# OpenTallas memory compiler (tools/mem_compiler), ASAP7 abstract view
VERSION 5.7 ;
BUSBITCHARS "[]" ;
DIVIDERCHAR "/" ;
PROPERTYDEFINITIONS
  MACRO width INTEGER ;
  MACRO depth INTEGER ;
  MACRO banks INTEGER ;
END PROPERTYDEFINITIONS
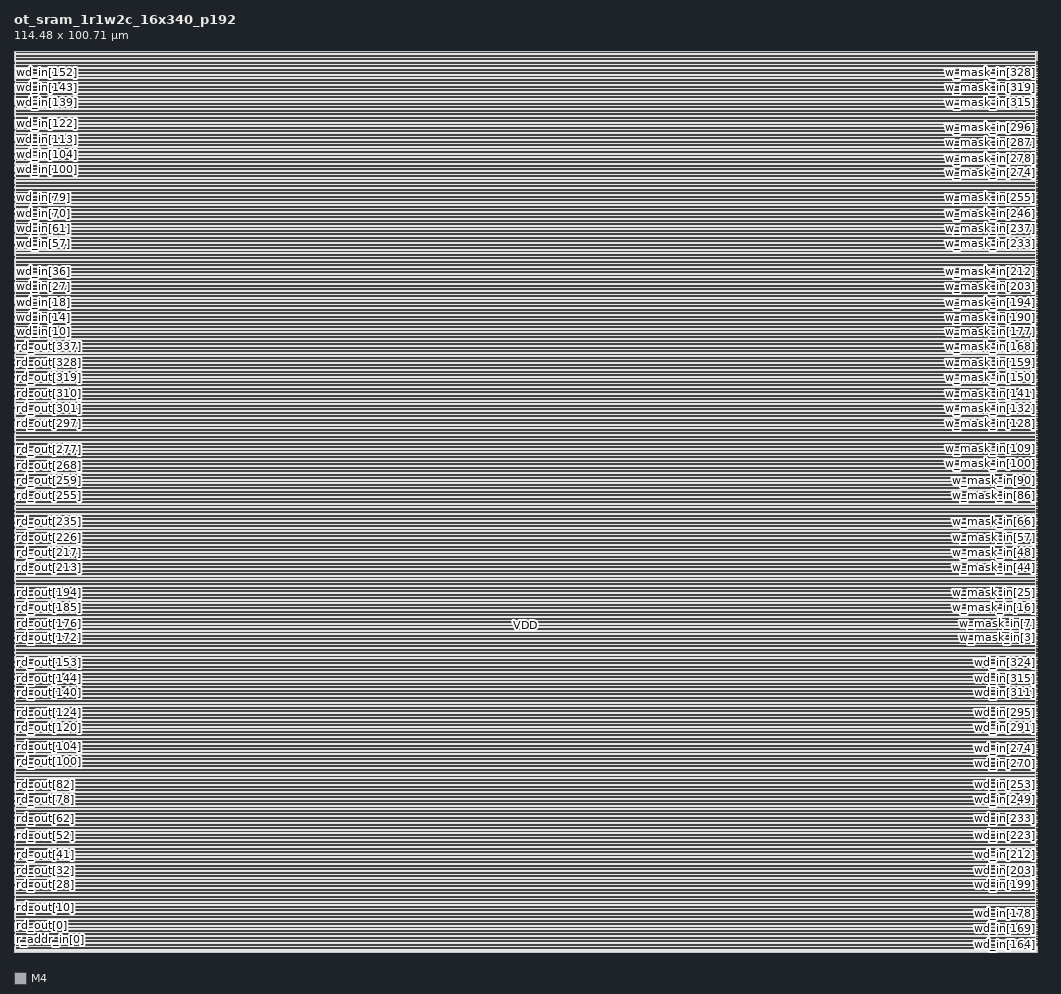
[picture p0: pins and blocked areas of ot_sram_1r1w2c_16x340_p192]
MACRO ot_sram_1r1w2c_16x340_p192
  PROPERTY width 340 ;
  PROPERTY depth 16 ;
  PROPERTY banks 1 ;
  FOREIGN ot_sram_1r1w2c_16x340_p192 0 0 ;
  SYMMETRY X Y R90 ;
  SIZE 114.480 BY 100.710 ;
  CLASS BLOCK ;
  PIN wclk
    DIRECTION INPUT ;
    USE CLOCK ;
    SHAPE ABUTMENT ;
    PORT
      LAYER M4 ;
      RECT 0.000 0.768 0.024 0.792 ;
    END
  END wclk
  PIN rclk
    DIRECTION INPUT ;
    USE CLOCK ;
    SHAPE ABUTMENT ;
    PORT
      LAYER M4 ;
      RECT 0.000 0.960 0.024 0.984 ;
    END
  END rclk
  PIN r_ce_in
    DIRECTION INPUT ;
    USE SIGNAL ;
    SHAPE ABUTMENT ;
    PORT
      LAYER M4 ;
      RECT 0.000 1.152 0.024 1.176 ;
    END
  END r_ce_in
  PIN r_addr_in[0]
    DIRECTION INPUT ;
    USE SIGNAL ;
    SHAPE ABUTMENT ;
    PORT
      LAYER M4 ;
      RECT 0.000 1.344 0.024 1.368 ;
    END
  END r_addr_in[0]
  PIN r_addr_in[1]
    DIRECTION INPUT ;
    USE SIGNAL ;
    SHAPE ABUTMENT ;
    PORT
      LAYER M4 ;
      RECT 0.000 1.536 0.024 1.560 ;
    END
  END r_addr_in[1]
  PIN r_addr_in[2]
    DIRECTION INPUT ;
    USE SIGNAL ;
    SHAPE ABUTMENT ;
    PORT
      LAYER M4 ;
      RECT 0.000 1.728 0.024 1.752 ;
    END
  END r_addr_in[2]
  PIN r_addr_in[3]
    DIRECTION INPUT ;
    USE SIGNAL ;
    SHAPE ABUTMENT ;
    PORT
      LAYER M4 ;
      RECT 0.000 1.920 0.024 1.944 ;
    END
  END r_addr_in[3]
  PIN rd_out[0]
    DIRECTION OUTPUT ;
    USE SIGNAL ;
    SHAPE ABUTMENT ;
    PORT
      LAYER M4 ;
      RECT 0.000 2.112 0.024 2.136 ;
    END
  END rd_out[0]
  PIN rd_out[1]
    DIRECTION OUTPUT ;
    USE SIGNAL ;
    SHAPE ABUTMENT ;
    PORT
      LAYER M4 ;
      RECT 0.000 2.304 0.024 2.328 ;
    END
  END rd_out[1]
  PIN rd_out[2]
    DIRECTION OUTPUT ;
    USE SIGNAL ;
    SHAPE ABUTMENT ;
    PORT
      LAYER M4 ;
      RECT 0.000 2.496 0.024 2.520 ;
    END
  END rd_out[2]
  PIN rd_out[3]
    DIRECTION OUTPUT ;
    USE SIGNAL ;
    SHAPE ABUTMENT ;
    PORT
      LAYER M4 ;
      RECT 0.000 2.688 0.024 2.712 ;
    END
  END rd_out[3]
  PIN rd_out[4]
    DIRECTION OUTPUT ;
    USE SIGNAL ;
    SHAPE ABUTMENT ;
    PORT
      LAYER M4 ;
      RECT 0.000 2.880 0.024 2.904 ;
    END
  END rd_out[4]
  PIN rd_out[5]
    DIRECTION OUTPUT ;
    USE SIGNAL ;
    SHAPE ABUTMENT ;
    PORT
      LAYER M4 ;
      RECT 0.000 3.072 0.024 3.096 ;
    END
  END rd_out[5]
  PIN rd_out[6]
    DIRECTION OUTPUT ;
    USE SIGNAL ;
    SHAPE ABUTMENT ;
    PORT
      LAYER M4 ;
      RECT 0.000 3.264 0.024 3.288 ;
    END
  END rd_out[6]
  PIN rd_out[7]
    DIRECTION OUTPUT ;
    USE SIGNAL ;
    SHAPE ABUTMENT ;
    PORT
      LAYER M4 ;
      RECT 0.000 3.456 0.024 3.480 ;
    END
  END rd_out[7]
  PIN rd_out[8]
    DIRECTION OUTPUT ;
    USE SIGNAL ;
    SHAPE ABUTMENT ;
    PORT
      LAYER M4 ;
      RECT 0.000 3.648 0.024 3.672 ;
    END
  END rd_out[8]
  PIN rd_out[9]
    DIRECTION OUTPUT ;
    USE SIGNAL ;
    SHAPE ABUTMENT ;
    PORT
      LAYER M4 ;
      RECT 0.000 3.840 0.024 3.864 ;
    END
  END rd_out[9]
  PIN rd_out[10]
    DIRECTION OUTPUT ;
    USE SIGNAL ;
    SHAPE ABUTMENT ;
    PORT
      LAYER M4 ;
      RECT 0.000 4.032 0.024 4.056 ;
    END
  END rd_out[10]
  PIN rd_out[11]
    DIRECTION OUTPUT ;
    USE SIGNAL ;
    SHAPE ABUTMENT ;
    PORT
      LAYER M4 ;
      RECT 0.000 4.224 0.024 4.248 ;
    END
  END rd_out[11]
  PIN rd_out[12]
    DIRECTION OUTPUT ;
    USE SIGNAL ;
    SHAPE ABUTMENT ;
    PORT
      LAYER M4 ;
      RECT 0.000 4.416 0.024 4.440 ;
    END
  END rd_out[12]
  PIN rd_out[13]
    DIRECTION OUTPUT ;
    USE SIGNAL ;
    SHAPE ABUTMENT ;
    PORT
      LAYER M4 ;
      RECT 0.000 4.608 0.024 4.632 ;
    END
  END rd_out[13]
  PIN rd_out[14]
    DIRECTION OUTPUT ;
    USE SIGNAL ;
    SHAPE ABUTMENT ;
    PORT
      LAYER M4 ;
      RECT 0.000 4.800 0.024 4.824 ;
    END
  END rd_out[14]
  PIN rd_out[15]
    DIRECTION OUTPUT ;
    USE SIGNAL ;
    SHAPE ABUTMENT ;
    PORT
      LAYER M4 ;
      RECT 0.000 4.992 0.024 5.016 ;
    END
  END rd_out[15]
  PIN rd_out[16]
    DIRECTION OUTPUT ;
    USE SIGNAL ;
    SHAPE ABUTMENT ;
    PORT
      LAYER M4 ;
      RECT 0.000 5.184 0.024 5.208 ;
    END
  END rd_out[16]
  PIN rd_out[17]
    DIRECTION OUTPUT ;
    USE SIGNAL ;
    SHAPE ABUTMENT ;
    PORT
      LAYER M4 ;
      RECT 0.000 5.376 0.024 5.400 ;
    END
  END rd_out[17]
  PIN rd_out[18]
    DIRECTION OUTPUT ;
    USE SIGNAL ;
    SHAPE ABUTMENT ;
    PORT
      LAYER M4 ;
      RECT 0.000 5.568 0.024 5.592 ;
    END
  END rd_out[18]
  PIN rd_out[19]
    DIRECTION OUTPUT ;
    USE SIGNAL ;
    SHAPE ABUTMENT ;
    PORT
      LAYER M4 ;
      RECT 0.000 5.760 0.024 5.784 ;
    END
  END rd_out[19]
  PIN rd_out[20]
    DIRECTION OUTPUT ;
    USE SIGNAL ;
    SHAPE ABUTMENT ;
    PORT
      LAYER M4 ;
      RECT 0.000 5.952 0.024 5.976 ;
    END
  END rd_out[20]
  PIN rd_out[21]
    DIRECTION OUTPUT ;
    USE SIGNAL ;
    SHAPE ABUTMENT ;
    PORT
      LAYER M4 ;
      RECT 0.000 6.144 0.024 6.168 ;
    END
  END rd_out[21]
  PIN rd_out[22]
    DIRECTION OUTPUT ;
    USE SIGNAL ;
    SHAPE ABUTMENT ;
    PORT
      LAYER M4 ;
      RECT 0.000 6.336 0.024 6.360 ;
    END
  END rd_out[22]
  PIN rd_out[23]
    DIRECTION OUTPUT ;
    USE SIGNAL ;
    SHAPE ABUTMENT ;
    PORT
      LAYER M4 ;
      RECT 0.000 6.528 0.024 6.552 ;
    END
  END rd_out[23]
  PIN rd_out[24]
    DIRECTION OUTPUT ;
    USE SIGNAL ;
    SHAPE ABUTMENT ;
    PORT
      LAYER M4 ;
      RECT 0.000 6.720 0.024 6.744 ;
    END
  END rd_out[24]
  PIN rd_out[25]
    DIRECTION OUTPUT ;
    USE SIGNAL ;
    SHAPE ABUTMENT ;
    PORT
      LAYER M4 ;
      RECT 0.000 6.912 0.024 6.936 ;
    END
  END rd_out[25]
  PIN rd_out[26]
    DIRECTION OUTPUT ;
    USE SIGNAL ;
    SHAPE ABUTMENT ;
    PORT
      LAYER M4 ;
      RECT 0.000 7.104 0.024 7.128 ;
    END
  END rd_out[26]
  PIN rd_out[27]
    DIRECTION OUTPUT ;
    USE SIGNAL ;
    SHAPE ABUTMENT ;
    PORT
      LAYER M4 ;
      RECT 0.000 7.296 0.024 7.320 ;
    END
  END rd_out[27]
  PIN rd_out[28]
    DIRECTION OUTPUT ;
    USE SIGNAL ;
    SHAPE ABUTMENT ;
    PORT
      LAYER M4 ;
      RECT 0.000 7.488 0.024 7.512 ;
    END
  END rd_out[28]
  PIN rd_out[29]
    DIRECTION OUTPUT ;
    USE SIGNAL ;
    SHAPE ABUTMENT ;
    PORT
      LAYER M4 ;
      RECT 0.000 7.680 0.024 7.704 ;
    END
  END rd_out[29]
  PIN rd_out[30]
    DIRECTION OUTPUT ;
    USE SIGNAL ;
    SHAPE ABUTMENT ;
    PORT
      LAYER M4 ;
      RECT 0.000 7.872 0.024 7.896 ;
    END
  END rd_out[30]
  PIN rd_out[31]
    DIRECTION OUTPUT ;
    USE SIGNAL ;
    SHAPE ABUTMENT ;
    PORT
      LAYER M4 ;
      RECT 0.000 8.064 0.024 8.088 ;
    END
  END rd_out[31]
  PIN rd_out[32]
    DIRECTION OUTPUT ;
    USE SIGNAL ;
    SHAPE ABUTMENT ;
    PORT
      LAYER M4 ;
      RECT 0.000 8.256 0.024 8.280 ;
    END
  END rd_out[32]
  PIN rd_out[33]
    DIRECTION OUTPUT ;
    USE SIGNAL ;
    SHAPE ABUTMENT ;
    PORT
      LAYER M4 ;
      RECT 0.000 8.448 0.024 8.472 ;
    END
  END rd_out[33]
  PIN rd_out[34]
    DIRECTION OUTPUT ;
    USE SIGNAL ;
    SHAPE ABUTMENT ;
    PORT
      LAYER M4 ;
      RECT 0.000 8.640 0.024 8.664 ;
    END
  END rd_out[34]
  PIN rd_out[35]
    DIRECTION OUTPUT ;
    USE SIGNAL ;
    SHAPE ABUTMENT ;
    PORT
      LAYER M4 ;
      RECT 0.000 8.832 0.024 8.856 ;
    END
  END rd_out[35]
  PIN rd_out[36]
    DIRECTION OUTPUT ;
    USE SIGNAL ;
    SHAPE ABUTMENT ;
    PORT
      LAYER M4 ;
      RECT 0.000 9.024 0.024 9.048 ;
    END
  END rd_out[36]
  PIN rd_out[37]
    DIRECTION OUTPUT ;
    USE SIGNAL ;
    SHAPE ABUTMENT ;
    PORT
      LAYER M4 ;
      RECT 0.000 9.216 0.024 9.240 ;
    END
  END rd_out[37]
  PIN rd_out[38]
    DIRECTION OUTPUT ;
    USE SIGNAL ;
    SHAPE ABUTMENT ;
    PORT
      LAYER M4 ;
      RECT 0.000 9.408 0.024 9.432 ;
    END
  END rd_out[38]
  PIN rd_out[39]
    DIRECTION OUTPUT ;
    USE SIGNAL ;
    SHAPE ABUTMENT ;
    PORT
      LAYER M4 ;
      RECT 0.000 9.600 0.024 9.624 ;
    END
  END rd_out[39]
  PIN rd_out[40]
    DIRECTION OUTPUT ;
    USE SIGNAL ;
    SHAPE ABUTMENT ;
    PORT
      LAYER M4 ;
      RECT 0.000 9.792 0.024 9.816 ;
    END
  END rd_out[40]
  PIN rd_out[41]
    DIRECTION OUTPUT ;
    USE SIGNAL ;
    SHAPE ABUTMENT ;
    PORT
      LAYER M4 ;
      RECT 0.000 9.984 0.024 10.008 ;
    END
  END rd_out[41]
  PIN rd_out[42]
    DIRECTION OUTPUT ;
    USE SIGNAL ;
    SHAPE ABUTMENT ;
    PORT
      LAYER M4 ;
      RECT 0.000 10.176 0.024 10.200 ;
    END
  END rd_out[42]
  PIN rd_out[43]
    DIRECTION OUTPUT ;
    USE SIGNAL ;
    SHAPE ABUTMENT ;
    PORT
      LAYER M4 ;
      RECT 0.000 10.368 0.024 10.392 ;
    END
  END rd_out[43]
  PIN rd_out[44]
    DIRECTION OUTPUT ;
    USE SIGNAL ;
    SHAPE ABUTMENT ;
    PORT
      LAYER M4 ;
      RECT 0.000 10.560 0.024 10.584 ;
    END
  END rd_out[44]
  PIN rd_out[45]
    DIRECTION OUTPUT ;
    USE SIGNAL ;
    SHAPE ABUTMENT ;
    PORT
      LAYER M4 ;
      RECT 0.000 10.752 0.024 10.776 ;
    END
  END rd_out[45]
  PIN rd_out[46]
    DIRECTION OUTPUT ;
    USE SIGNAL ;
    SHAPE ABUTMENT ;
    PORT
      LAYER M4 ;
      RECT 0.000 10.944 0.024 10.968 ;
    END
  END rd_out[46]
  PIN rd_out[47]
    DIRECTION OUTPUT ;
    USE SIGNAL ;
    SHAPE ABUTMENT ;
    PORT
      LAYER M4 ;
      RECT 0.000 11.136 0.024 11.160 ;
    END
  END rd_out[47]
  PIN rd_out[48]
    DIRECTION OUTPUT ;
    USE SIGNAL ;
    SHAPE ABUTMENT ;
    PORT
      LAYER M4 ;
      RECT 0.000 11.328 0.024 11.352 ;
    END
  END rd_out[48]
  PIN rd_out[49]
    DIRECTION OUTPUT ;
    USE SIGNAL ;
    SHAPE ABUTMENT ;
    PORT
      LAYER M4 ;
      RECT 0.000 11.520 0.024 11.544 ;
    END
  END rd_out[49]
  PIN rd_out[50]
    DIRECTION OUTPUT ;
    USE SIGNAL ;
    SHAPE ABUTMENT ;
    PORT
      LAYER M4 ;
      RECT 0.000 11.712 0.024 11.736 ;
    END
  END rd_out[50]
  PIN rd_out[51]
    DIRECTION OUTPUT ;
    USE SIGNAL ;
    SHAPE ABUTMENT ;
    PORT
      LAYER M4 ;
      RECT 0.000 11.904 0.024 11.928 ;
    END
  END rd_out[51]
  PIN rd_out[52]
    DIRECTION OUTPUT ;
    USE SIGNAL ;
    SHAPE ABUTMENT ;
    PORT
      LAYER M4 ;
      RECT 0.000 12.096 0.024 12.120 ;
    END
  END rd_out[52]
  PIN rd_out[53]
    DIRECTION OUTPUT ;
    USE SIGNAL ;
    SHAPE ABUTMENT ;
    PORT
      LAYER M4 ;
      RECT 0.000 12.288 0.024 12.312 ;
    END
  END rd_out[53]
  PIN rd_out[54]
    DIRECTION OUTPUT ;
    USE SIGNAL ;
    SHAPE ABUTMENT ;
    PORT
      LAYER M4 ;
      RECT 0.000 12.480 0.024 12.504 ;
    END
  END rd_out[54]
  PIN rd_out[55]
    DIRECTION OUTPUT ;
    USE SIGNAL ;
    SHAPE ABUTMENT ;
    PORT
      LAYER M4 ;
      RECT 0.000 12.672 0.024 12.696 ;
    END
  END rd_out[55]
  PIN rd_out[56]
    DIRECTION OUTPUT ;
    USE SIGNAL ;
    SHAPE ABUTMENT ;
    PORT
      LAYER M4 ;
      RECT 0.000 12.864 0.024 12.888 ;
    END
  END rd_out[56]
  PIN rd_out[57]
    DIRECTION OUTPUT ;
    USE SIGNAL ;
    SHAPE ABUTMENT ;
    PORT
      LAYER M4 ;
      RECT 0.000 13.056 0.024 13.080 ;
    END
  END rd_out[57]
  PIN rd_out[58]
    DIRECTION OUTPUT ;
    USE SIGNAL ;
    SHAPE ABUTMENT ;
    PORT
      LAYER M4 ;
      RECT 0.000 13.248 0.024 13.272 ;
    END
  END rd_out[58]
  PIN rd_out[59]
    DIRECTION OUTPUT ;
    USE SIGNAL ;
    SHAPE ABUTMENT ;
    PORT
      LAYER M4 ;
      RECT 0.000 13.440 0.024 13.464 ;
    END
  END rd_out[59]
  PIN rd_out[60]
    DIRECTION OUTPUT ;
    USE SIGNAL ;
    SHAPE ABUTMENT ;
    PORT
      LAYER M4 ;
      RECT 0.000 13.632 0.024 13.656 ;
    END
  END rd_out[60]
  PIN rd_out[61]
    DIRECTION OUTPUT ;
    USE SIGNAL ;
    SHAPE ABUTMENT ;
    PORT
      LAYER M4 ;
      RECT 0.000 13.824 0.024 13.848 ;
    END
  END rd_out[61]
  PIN rd_out[62]
    DIRECTION OUTPUT ;
    USE SIGNAL ;
    SHAPE ABUTMENT ;
    PORT
      LAYER M4 ;
      RECT 0.000 14.016 0.024 14.040 ;
    END
  END rd_out[62]
  PIN rd_out[63]
    DIRECTION OUTPUT ;
    USE SIGNAL ;
    SHAPE ABUTMENT ;
    PORT
      LAYER M4 ;
      RECT 0.000 14.208 0.024 14.232 ;
    END
  END rd_out[63]
  PIN rd_out[64]
    DIRECTION OUTPUT ;
    USE SIGNAL ;
    SHAPE ABUTMENT ;
    PORT
      LAYER M4 ;
      RECT 0.000 14.400 0.024 14.424 ;
    END
  END rd_out[64]
  PIN rd_out[65]
    DIRECTION OUTPUT ;
    USE SIGNAL ;
    SHAPE ABUTMENT ;
    PORT
      LAYER M4 ;
      RECT 0.000 14.592 0.024 14.616 ;
    END
  END rd_out[65]
  PIN rd_out[66]
    DIRECTION OUTPUT ;
    USE SIGNAL ;
    SHAPE ABUTMENT ;
    PORT
      LAYER M4 ;
      RECT 0.000 14.784 0.024 14.808 ;
    END
  END rd_out[66]
  PIN rd_out[67]
    DIRECTION OUTPUT ;
    USE SIGNAL ;
    SHAPE ABUTMENT ;
    PORT
      LAYER M4 ;
      RECT 0.000 14.976 0.024 15.000 ;
    END
  END rd_out[67]
  PIN rd_out[68]
    DIRECTION OUTPUT ;
    USE SIGNAL ;
    SHAPE ABUTMENT ;
    PORT
      LAYER M4 ;
      RECT 0.000 15.168 0.024 15.192 ;
    END
  END rd_out[68]
  PIN rd_out[69]
    DIRECTION OUTPUT ;
    USE SIGNAL ;
    SHAPE ABUTMENT ;
    PORT
      LAYER M4 ;
      RECT 0.000 15.360 0.024 15.384 ;
    END
  END rd_out[69]
  PIN rd_out[70]
    DIRECTION OUTPUT ;
    USE SIGNAL ;
    SHAPE ABUTMENT ;
    PORT
      LAYER M4 ;
      RECT 0.000 15.552 0.024 15.576 ;
    END
  END rd_out[70]
  PIN rd_out[71]
    DIRECTION OUTPUT ;
    USE SIGNAL ;
    SHAPE ABUTMENT ;
    PORT
      LAYER M4 ;
      RECT 0.000 15.744 0.024 15.768 ;
    END
  END rd_out[71]
  PIN rd_out[72]
    DIRECTION OUTPUT ;
    USE SIGNAL ;
    SHAPE ABUTMENT ;
    PORT
      LAYER M4 ;
      RECT 0.000 15.936 0.024 15.960 ;
    END
  END rd_out[72]
  PIN rd_out[73]
    DIRECTION OUTPUT ;
    USE SIGNAL ;
    SHAPE ABUTMENT ;
    PORT
      LAYER M4 ;
      RECT 0.000 16.128 0.024 16.152 ;
    END
  END rd_out[73]
  PIN rd_out[74]
    DIRECTION OUTPUT ;
    USE SIGNAL ;
    SHAPE ABUTMENT ;
    PORT
      LAYER M4 ;
      RECT 0.000 16.320 0.024 16.344 ;
    END
  END rd_out[74]
  PIN rd_out[75]
    DIRECTION OUTPUT ;
    USE SIGNAL ;
    SHAPE ABUTMENT ;
    PORT
      LAYER M4 ;
      RECT 0.000 16.512 0.024 16.536 ;
    END
  END rd_out[75]
  PIN rd_out[76]
    DIRECTION OUTPUT ;
    USE SIGNAL ;
    SHAPE ABUTMENT ;
    PORT
      LAYER M4 ;
      RECT 0.000 16.704 0.024 16.728 ;
    END
  END rd_out[76]
  PIN rd_out[77]
    DIRECTION OUTPUT ;
    USE SIGNAL ;
    SHAPE ABUTMENT ;
    PORT
      LAYER M4 ;
      RECT 0.000 16.896 0.024 16.920 ;
    END
  END rd_out[77]
  PIN rd_out[78]
    DIRECTION OUTPUT ;
    USE SIGNAL ;
    SHAPE ABUTMENT ;
    PORT
      LAYER M4 ;
      RECT 0.000 17.088 0.024 17.112 ;
    END
  END rd_out[78]
  PIN rd_out[79]
    DIRECTION OUTPUT ;
    USE SIGNAL ;
    SHAPE ABUTMENT ;
    PORT
      LAYER M4 ;
      RECT 0.000 17.280 0.024 17.304 ;
    END
  END rd_out[79]
  PIN rd_out[80]
    DIRECTION OUTPUT ;
    USE SIGNAL ;
    SHAPE ABUTMENT ;
    PORT
      LAYER M4 ;
      RECT 0.000 17.472 0.024 17.496 ;
    END
  END rd_out[80]
  PIN rd_out[81]
    DIRECTION OUTPUT ;
    USE SIGNAL ;
    SHAPE ABUTMENT ;
    PORT
      LAYER M4 ;
      RECT 0.000 17.664 0.024 17.688 ;
    END
  END rd_out[81]
  PIN rd_out[82]
    DIRECTION OUTPUT ;
    USE SIGNAL ;
    SHAPE ABUTMENT ;
    PORT
      LAYER M4 ;
      RECT 0.000 17.856 0.024 17.880 ;
    END
  END rd_out[82]
  PIN rd_out[83]
    DIRECTION OUTPUT ;
    USE SIGNAL ;
    SHAPE ABUTMENT ;
    PORT
      LAYER M4 ;
      RECT 0.000 18.048 0.024 18.072 ;
    END
  END rd_out[83]
  PIN rd_out[84]
    DIRECTION OUTPUT ;
    USE SIGNAL ;
    SHAPE ABUTMENT ;
    PORT
      LAYER M4 ;
      RECT 0.000 18.240 0.024 18.264 ;
    END
  END rd_out[84]
  PIN rd_out[85]
    DIRECTION OUTPUT ;
    USE SIGNAL ;
    SHAPE ABUTMENT ;
    PORT
      LAYER M4 ;
      RECT 0.000 18.432 0.024 18.456 ;
    END
  END rd_out[85]
  PIN rd_out[86]
    DIRECTION OUTPUT ;
    USE SIGNAL ;
    SHAPE ABUTMENT ;
    PORT
      LAYER M4 ;
      RECT 0.000 18.624 0.024 18.648 ;
    END
  END rd_out[86]
  PIN rd_out[87]
    DIRECTION OUTPUT ;
    USE SIGNAL ;
    SHAPE ABUTMENT ;
    PORT
      LAYER M4 ;
      RECT 0.000 18.816 0.024 18.840 ;
    END
  END rd_out[87]
  PIN rd_out[88]
    DIRECTION OUTPUT ;
    USE SIGNAL ;
    SHAPE ABUTMENT ;
    PORT
      LAYER M4 ;
      RECT 0.000 19.008 0.024 19.032 ;
    END
  END rd_out[88]
  PIN rd_out[89]
    DIRECTION OUTPUT ;
    USE SIGNAL ;
    SHAPE ABUTMENT ;
    PORT
      LAYER M4 ;
      RECT 0.000 19.200 0.024 19.224 ;
    END
  END rd_out[89]
  PIN rd_out[90]
    DIRECTION OUTPUT ;
    USE SIGNAL ;
    SHAPE ABUTMENT ;
    PORT
      LAYER M4 ;
      RECT 0.000 19.392 0.024 19.416 ;
    END
  END rd_out[90]
  PIN rd_out[91]
    DIRECTION OUTPUT ;
    USE SIGNAL ;
    SHAPE ABUTMENT ;
    PORT
      LAYER M4 ;
      RECT 0.000 19.584 0.024 19.608 ;
    END
  END rd_out[91]
  PIN rd_out[92]
    DIRECTION OUTPUT ;
    USE SIGNAL ;
    SHAPE ABUTMENT ;
    PORT
      LAYER M4 ;
      RECT 0.000 19.776 0.024 19.800 ;
    END
  END rd_out[92]
  PIN rd_out[93]
    DIRECTION OUTPUT ;
    USE SIGNAL ;
    SHAPE ABUTMENT ;
    PORT
      LAYER M4 ;
      RECT 0.000 19.968 0.024 19.992 ;
    END
  END rd_out[93]
  PIN rd_out[94]
    DIRECTION OUTPUT ;
    USE SIGNAL ;
    SHAPE ABUTMENT ;
    PORT
      LAYER M4 ;
      RECT 0.000 20.160 0.024 20.184 ;
    END
  END rd_out[94]
  PIN rd_out[95]
    DIRECTION OUTPUT ;
    USE SIGNAL ;
    SHAPE ABUTMENT ;
    PORT
      LAYER M4 ;
      RECT 0.000 20.352 0.024 20.376 ;
    END
  END rd_out[95]
  PIN rd_out[96]
    DIRECTION OUTPUT ;
    USE SIGNAL ;
    SHAPE ABUTMENT ;
    PORT
      LAYER M4 ;
      RECT 0.000 20.544 0.024 20.568 ;
    END
  END rd_out[96]
  PIN rd_out[97]
    DIRECTION OUTPUT ;
    USE SIGNAL ;
    SHAPE ABUTMENT ;
    PORT
      LAYER M4 ;
      RECT 0.000 20.736 0.024 20.760 ;
    END
  END rd_out[97]
  PIN rd_out[98]
    DIRECTION OUTPUT ;
    USE SIGNAL ;
    SHAPE ABUTMENT ;
    PORT
      LAYER M4 ;
      RECT 0.000 20.928 0.024 20.952 ;
    END
  END rd_out[98]
  PIN rd_out[99]
    DIRECTION OUTPUT ;
    USE SIGNAL ;
    SHAPE ABUTMENT ;
    PORT
      LAYER M4 ;
      RECT 0.000 21.120 0.024 21.144 ;
    END
  END rd_out[99]
  PIN rd_out[100]
    DIRECTION OUTPUT ;
    USE SIGNAL ;
    SHAPE ABUTMENT ;
    PORT
      LAYER M4 ;
      RECT 0.000 21.312 0.024 21.336 ;
    END
  END rd_out[100]
  PIN rd_out[101]
    DIRECTION OUTPUT ;
    USE SIGNAL ;
    SHAPE ABUTMENT ;
    PORT
      LAYER M4 ;
      RECT 0.000 21.504 0.024 21.528 ;
    END
  END rd_out[101]
  PIN rd_out[102]
    DIRECTION OUTPUT ;
    USE SIGNAL ;
    SHAPE ABUTMENT ;
    PORT
      LAYER M4 ;
      RECT 0.000 21.696 0.024 21.720 ;
    END
  END rd_out[102]
  PIN rd_out[103]
    DIRECTION OUTPUT ;
    USE SIGNAL ;
    SHAPE ABUTMENT ;
    PORT
      LAYER M4 ;
      RECT 0.000 21.888 0.024 21.912 ;
    END
  END rd_out[103]
  PIN rd_out[104]
    DIRECTION OUTPUT ;
    USE SIGNAL ;
    SHAPE ABUTMENT ;
    PORT
      LAYER M4 ;
      RECT 0.000 22.080 0.024 22.104 ;
    END
  END rd_out[104]
  PIN rd_out[105]
    DIRECTION OUTPUT ;
    USE SIGNAL ;
    SHAPE ABUTMENT ;
    PORT
      LAYER M4 ;
      RECT 0.000 22.272 0.024 22.296 ;
    END
  END rd_out[105]
  PIN rd_out[106]
    DIRECTION OUTPUT ;
    USE SIGNAL ;
    SHAPE ABUTMENT ;
    PORT
      LAYER M4 ;
      RECT 0.000 22.464 0.024 22.488 ;
    END
  END rd_out[106]
  PIN rd_out[107]
    DIRECTION OUTPUT ;
    USE SIGNAL ;
    SHAPE ABUTMENT ;
    PORT
      LAYER M4 ;
      RECT 0.000 22.656 0.024 22.680 ;
    END
  END rd_out[107]
  PIN rd_out[108]
    DIRECTION OUTPUT ;
    USE SIGNAL ;
    SHAPE ABUTMENT ;
    PORT
      LAYER M4 ;
      RECT 0.000 22.848 0.024 22.872 ;
    END
  END rd_out[108]
  PIN rd_out[109]
    DIRECTION OUTPUT ;
    USE SIGNAL ;
    SHAPE ABUTMENT ;
    PORT
      LAYER M4 ;
      RECT 0.000 23.040 0.024 23.064 ;
    END
  END rd_out[109]
  PIN rd_out[110]
    DIRECTION OUTPUT ;
    USE SIGNAL ;
    SHAPE ABUTMENT ;
    PORT
      LAYER M4 ;
      RECT 0.000 23.232 0.024 23.256 ;
    END
  END rd_out[110]
  PIN rd_out[111]
    DIRECTION OUTPUT ;
    USE SIGNAL ;
    SHAPE ABUTMENT ;
    PORT
      LAYER M4 ;
      RECT 0.000 23.424 0.024 23.448 ;
    END
  END rd_out[111]
  PIN rd_out[112]
    DIRECTION OUTPUT ;
    USE SIGNAL ;
    SHAPE ABUTMENT ;
    PORT
      LAYER M4 ;
      RECT 0.000 23.616 0.024 23.640 ;
    END
  END rd_out[112]
  PIN rd_out[113]
    DIRECTION OUTPUT ;
    USE SIGNAL ;
    SHAPE ABUTMENT ;
    PORT
      LAYER M4 ;
      RECT 0.000 23.808 0.024 23.832 ;
    END
  END rd_out[113]
  PIN rd_out[114]
    DIRECTION OUTPUT ;
    USE SIGNAL ;
    SHAPE ABUTMENT ;
    PORT
      LAYER M4 ;
      RECT 0.000 24.000 0.024 24.024 ;
    END
  END rd_out[114]
  PIN rd_out[115]
    DIRECTION OUTPUT ;
    USE SIGNAL ;
    SHAPE ABUTMENT ;
    PORT
      LAYER M4 ;
      RECT 0.000 24.192 0.024 24.216 ;
    END
  END rd_out[115]
  PIN rd_out[116]
    DIRECTION OUTPUT ;
    USE SIGNAL ;
    SHAPE ABUTMENT ;
    PORT
      LAYER M4 ;
      RECT 0.000 24.384 0.024 24.408 ;
    END
  END rd_out[116]
  PIN rd_out[117]
    DIRECTION OUTPUT ;
    USE SIGNAL ;
    SHAPE ABUTMENT ;
    PORT
      LAYER M4 ;
      RECT 0.000 24.576 0.024 24.600 ;
    END
  END rd_out[117]
  PIN rd_out[118]
    DIRECTION OUTPUT ;
    USE SIGNAL ;
    SHAPE ABUTMENT ;
    PORT
      LAYER M4 ;
      RECT 0.000 24.768 0.024 24.792 ;
    END
  END rd_out[118]
  PIN rd_out[119]
    DIRECTION OUTPUT ;
    USE SIGNAL ;
    SHAPE ABUTMENT ;
    PORT
      LAYER M4 ;
      RECT 0.000 24.960 0.024 24.984 ;
    END
  END rd_out[119]
  PIN rd_out[120]
    DIRECTION OUTPUT ;
    USE SIGNAL ;
    SHAPE ABUTMENT ;
    PORT
      LAYER M4 ;
      RECT 0.000 25.152 0.024 25.176 ;
    END
  END rd_out[120]
  PIN rd_out[121]
    DIRECTION OUTPUT ;
    USE SIGNAL ;
    SHAPE ABUTMENT ;
    PORT
      LAYER M4 ;
      RECT 0.000 25.344 0.024 25.368 ;
    END
  END rd_out[121]
  PIN rd_out[122]
    DIRECTION OUTPUT ;
    USE SIGNAL ;
    SHAPE ABUTMENT ;
    PORT
      LAYER M4 ;
      RECT 0.000 25.536 0.024 25.560 ;
    END
  END rd_out[122]
  PIN rd_out[123]
    DIRECTION OUTPUT ;
    USE SIGNAL ;
    SHAPE ABUTMENT ;
    PORT
      LAYER M4 ;
      RECT 0.000 25.728 0.024 25.752 ;
    END
  END rd_out[123]
  PIN rd_out[124]
    DIRECTION OUTPUT ;
    USE SIGNAL ;
    SHAPE ABUTMENT ;
    PORT
      LAYER M4 ;
      RECT 0.000 25.920 0.024 25.944 ;
    END
  END rd_out[124]
  PIN rd_out[125]
    DIRECTION OUTPUT ;
    USE SIGNAL ;
    SHAPE ABUTMENT ;
    PORT
      LAYER M4 ;
      RECT 0.000 26.112 0.024 26.136 ;
    END
  END rd_out[125]
  PIN rd_out[126]
    DIRECTION OUTPUT ;
    USE SIGNAL ;
    SHAPE ABUTMENT ;
    PORT
      LAYER M4 ;
      RECT 0.000 26.304 0.024 26.328 ;
    END
  END rd_out[126]
  PIN rd_out[127]
    DIRECTION OUTPUT ;
    USE SIGNAL ;
    SHAPE ABUTMENT ;
    PORT
      LAYER M4 ;
      RECT 0.000 26.496 0.024 26.520 ;
    END
  END rd_out[127]
  PIN rd_out[128]
    DIRECTION OUTPUT ;
    USE SIGNAL ;
    SHAPE ABUTMENT ;
    PORT
      LAYER M4 ;
      RECT 0.000 26.688 0.024 26.712 ;
    END
  END rd_out[128]
  PIN rd_out[129]
    DIRECTION OUTPUT ;
    USE SIGNAL ;
    SHAPE ABUTMENT ;
    PORT
      LAYER M4 ;
      RECT 0.000 26.880 0.024 26.904 ;
    END
  END rd_out[129]
  PIN rd_out[130]
    DIRECTION OUTPUT ;
    USE SIGNAL ;
    SHAPE ABUTMENT ;
    PORT
      LAYER M4 ;
      RECT 0.000 27.072 0.024 27.096 ;
    END
  END rd_out[130]
  PIN rd_out[131]
    DIRECTION OUTPUT ;
    USE SIGNAL ;
    SHAPE ABUTMENT ;
    PORT
      LAYER M4 ;
      RECT 0.000 27.264 0.024 27.288 ;
    END
  END rd_out[131]
  PIN rd_out[132]
    DIRECTION OUTPUT ;
    USE SIGNAL ;
    SHAPE ABUTMENT ;
    PORT
      LAYER M4 ;
      RECT 0.000 27.456 0.024 27.480 ;
    END
  END rd_out[132]
  PIN rd_out[133]
    DIRECTION OUTPUT ;
    USE SIGNAL ;
    SHAPE ABUTMENT ;
    PORT
      LAYER M4 ;
      RECT 0.000 27.648 0.024 27.672 ;
    END
  END rd_out[133]
  PIN rd_out[134]
    DIRECTION OUTPUT ;
    USE SIGNAL ;
    SHAPE ABUTMENT ;
    PORT
      LAYER M4 ;
      RECT 0.000 27.840 0.024 27.864 ;
    END
  END rd_out[134]
  PIN rd_out[135]
    DIRECTION OUTPUT ;
    USE SIGNAL ;
    SHAPE ABUTMENT ;
    PORT
      LAYER M4 ;
      RECT 0.000 28.032 0.024 28.056 ;
    END
  END rd_out[135]
  PIN rd_out[136]
    DIRECTION OUTPUT ;
    USE SIGNAL ;
    SHAPE ABUTMENT ;
    PORT
      LAYER M4 ;
      RECT 0.000 28.224 0.024 28.248 ;
    END
  END rd_out[136]
  PIN rd_out[137]
    DIRECTION OUTPUT ;
    USE SIGNAL ;
    SHAPE ABUTMENT ;
    PORT
      LAYER M4 ;
      RECT 0.000 28.416 0.024 28.440 ;
    END
  END rd_out[137]
  PIN rd_out[138]
    DIRECTION OUTPUT ;
    USE SIGNAL ;
    SHAPE ABUTMENT ;
    PORT
      LAYER M4 ;
      RECT 0.000 28.608 0.024 28.632 ;
    END
  END rd_out[138]
  PIN rd_out[139]
    DIRECTION OUTPUT ;
    USE SIGNAL ;
    SHAPE ABUTMENT ;
    PORT
      LAYER M4 ;
      RECT 0.000 28.800 0.024 28.824 ;
    END
  END rd_out[139]
  PIN rd_out[140]
    DIRECTION OUTPUT ;
    USE SIGNAL ;
    SHAPE ABUTMENT ;
    PORT
      LAYER M4 ;
      RECT 0.000 28.992 0.024 29.016 ;
    END
  END rd_out[140]
  PIN rd_out[141]
    DIRECTION OUTPUT ;
    USE SIGNAL ;
    SHAPE ABUTMENT ;
    PORT
      LAYER M4 ;
      RECT 0.000 29.184 0.024 29.208 ;
    END
  END rd_out[141]
  PIN rd_out[142]
    DIRECTION OUTPUT ;
    USE SIGNAL ;
    SHAPE ABUTMENT ;
    PORT
      LAYER M4 ;
      RECT 0.000 29.376 0.024 29.400 ;
    END
  END rd_out[142]
  PIN rd_out[143]
    DIRECTION OUTPUT ;
    USE SIGNAL ;
    SHAPE ABUTMENT ;
    PORT
      LAYER M4 ;
      RECT 0.000 29.568 0.024 29.592 ;
    END
  END rd_out[143]
  PIN rd_out[144]
    DIRECTION OUTPUT ;
    USE SIGNAL ;
    SHAPE ABUTMENT ;
    PORT
      LAYER M4 ;
      RECT 0.000 29.760 0.024 29.784 ;
    END
  END rd_out[144]
  PIN rd_out[145]
    DIRECTION OUTPUT ;
    USE SIGNAL ;
    SHAPE ABUTMENT ;
    PORT
      LAYER M4 ;
      RECT 0.000 29.952 0.024 29.976 ;
    END
  END rd_out[145]
  PIN rd_out[146]
    DIRECTION OUTPUT ;
    USE SIGNAL ;
    SHAPE ABUTMENT ;
    PORT
      LAYER M4 ;
      RECT 0.000 30.144 0.024 30.168 ;
    END
  END rd_out[146]
  PIN rd_out[147]
    DIRECTION OUTPUT ;
    USE SIGNAL ;
    SHAPE ABUTMENT ;
    PORT
      LAYER M4 ;
      RECT 0.000 30.336 0.024 30.360 ;
    END
  END rd_out[147]
  PIN rd_out[148]
    DIRECTION OUTPUT ;
    USE SIGNAL ;
    SHAPE ABUTMENT ;
    PORT
      LAYER M4 ;
      RECT 0.000 30.528 0.024 30.552 ;
    END
  END rd_out[148]
  PIN rd_out[149]
    DIRECTION OUTPUT ;
    USE SIGNAL ;
    SHAPE ABUTMENT ;
    PORT
      LAYER M4 ;
      RECT 0.000 30.720 0.024 30.744 ;
    END
  END rd_out[149]
  PIN rd_out[150]
    DIRECTION OUTPUT ;
    USE SIGNAL ;
    SHAPE ABUTMENT ;
    PORT
      LAYER M4 ;
      RECT 0.000 30.912 0.024 30.936 ;
    END
  END rd_out[150]
  PIN rd_out[151]
    DIRECTION OUTPUT ;
    USE SIGNAL ;
    SHAPE ABUTMENT ;
    PORT
      LAYER M4 ;
      RECT 0.000 31.104 0.024 31.128 ;
    END
  END rd_out[151]
  PIN rd_out[152]
    DIRECTION OUTPUT ;
    USE SIGNAL ;
    SHAPE ABUTMENT ;
    PORT
      LAYER M4 ;
      RECT 0.000 31.296 0.024 31.320 ;
    END
  END rd_out[152]
  PIN rd_out[153]
    DIRECTION OUTPUT ;
    USE SIGNAL ;
    SHAPE ABUTMENT ;
    PORT
      LAYER M4 ;
      RECT 0.000 31.488 0.024 31.512 ;
    END
  END rd_out[153]
  PIN rd_out[154]
    DIRECTION OUTPUT ;
    USE SIGNAL ;
    SHAPE ABUTMENT ;
    PORT
      LAYER M4 ;
      RECT 0.000 31.680 0.024 31.704 ;
    END
  END rd_out[154]
  PIN rd_out[155]
    DIRECTION OUTPUT ;
    USE SIGNAL ;
    SHAPE ABUTMENT ;
    PORT
      LAYER M4 ;
      RECT 0.000 31.872 0.024 31.896 ;
    END
  END rd_out[155]
  PIN rd_out[156]
    DIRECTION OUTPUT ;
    USE SIGNAL ;
    SHAPE ABUTMENT ;
    PORT
      LAYER M4 ;
      RECT 0.000 32.064 0.024 32.088 ;
    END
  END rd_out[156]
  PIN rd_out[157]
    DIRECTION OUTPUT ;
    USE SIGNAL ;
    SHAPE ABUTMENT ;
    PORT
      LAYER M4 ;
      RECT 0.000 32.256 0.024 32.280 ;
    END
  END rd_out[157]
  PIN rd_out[158]
    DIRECTION OUTPUT ;
    USE SIGNAL ;
    SHAPE ABUTMENT ;
    PORT
      LAYER M4 ;
      RECT 0.000 32.448 0.024 32.472 ;
    END
  END rd_out[158]
  PIN rd_out[159]
    DIRECTION OUTPUT ;
    USE SIGNAL ;
    SHAPE ABUTMENT ;
    PORT
      LAYER M4 ;
      RECT 0.000 32.640 0.024 32.664 ;
    END
  END rd_out[159]
  PIN rd_out[160]
    DIRECTION OUTPUT ;
    USE SIGNAL ;
    SHAPE ABUTMENT ;
    PORT
      LAYER M4 ;
      RECT 0.000 32.832 0.024 32.856 ;
    END
  END rd_out[160]
  PIN rd_out[161]
    DIRECTION OUTPUT ;
    USE SIGNAL ;
    SHAPE ABUTMENT ;
    PORT
      LAYER M4 ;
      RECT 0.000 33.024 0.024 33.048 ;
    END
  END rd_out[161]
  PIN rd_out[162]
    DIRECTION OUTPUT ;
    USE SIGNAL ;
    SHAPE ABUTMENT ;
    PORT
      LAYER M4 ;
      RECT 0.000 33.216 0.024 33.240 ;
    END
  END rd_out[162]
  PIN rd_out[163]
    DIRECTION OUTPUT ;
    USE SIGNAL ;
    SHAPE ABUTMENT ;
    PORT
      LAYER M4 ;
      RECT 0.000 33.408 0.024 33.432 ;
    END
  END rd_out[163]
  PIN rd_out[164]
    DIRECTION OUTPUT ;
    USE SIGNAL ;
    SHAPE ABUTMENT ;
    PORT
      LAYER M4 ;
      RECT 0.000 33.600 0.024 33.624 ;
    END
  END rd_out[164]
  PIN rd_out[165]
    DIRECTION OUTPUT ;
    USE SIGNAL ;
    SHAPE ABUTMENT ;
    PORT
      LAYER M4 ;
      RECT 0.000 33.792 0.024 33.816 ;
    END
  END rd_out[165]
  PIN rd_out[166]
    DIRECTION OUTPUT ;
    USE SIGNAL ;
    SHAPE ABUTMENT ;
    PORT
      LAYER M4 ;
      RECT 0.000 33.984 0.024 34.008 ;
    END
  END rd_out[166]
  PIN rd_out[167]
    DIRECTION OUTPUT ;
    USE SIGNAL ;
    SHAPE ABUTMENT ;
    PORT
      LAYER M4 ;
      RECT 0.000 34.176 0.024 34.200 ;
    END
  END rd_out[167]
  PIN rd_out[168]
    DIRECTION OUTPUT ;
    USE SIGNAL ;
    SHAPE ABUTMENT ;
    PORT
      LAYER M4 ;
      RECT 0.000 34.368 0.024 34.392 ;
    END
  END rd_out[168]
  PIN rd_out[169]
    DIRECTION OUTPUT ;
    USE SIGNAL ;
    SHAPE ABUTMENT ;
    PORT
      LAYER M4 ;
      RECT 0.000 34.560 0.024 34.584 ;
    END
  END rd_out[169]
  PIN rd_out[170]
    DIRECTION OUTPUT ;
    USE SIGNAL ;
    SHAPE ABUTMENT ;
    PORT
      LAYER M4 ;
      RECT 0.000 34.752 0.024 34.776 ;
    END
  END rd_out[170]
  PIN rd_out[171]
    DIRECTION OUTPUT ;
    USE SIGNAL ;
    SHAPE ABUTMENT ;
    PORT
      LAYER M4 ;
      RECT 0.000 34.944 0.024 34.968 ;
    END
  END rd_out[171]
  PIN rd_out[172]
    DIRECTION OUTPUT ;
    USE SIGNAL ;
    SHAPE ABUTMENT ;
    PORT
      LAYER M4 ;
      RECT 0.000 35.136 0.024 35.160 ;
    END
  END rd_out[172]
  PIN rd_out[173]
    DIRECTION OUTPUT ;
    USE SIGNAL ;
    SHAPE ABUTMENT ;
    PORT
      LAYER M4 ;
      RECT 0.000 35.328 0.024 35.352 ;
    END
  END rd_out[173]
  PIN rd_out[174]
    DIRECTION OUTPUT ;
    USE SIGNAL ;
    SHAPE ABUTMENT ;
    PORT
      LAYER M4 ;
      RECT 0.000 35.520 0.024 35.544 ;
    END
  END rd_out[174]
  PIN rd_out[175]
    DIRECTION OUTPUT ;
    USE SIGNAL ;
    SHAPE ABUTMENT ;
    PORT
      LAYER M4 ;
      RECT 0.000 35.712 0.024 35.736 ;
    END
  END rd_out[175]
  PIN rd_out[176]
    DIRECTION OUTPUT ;
    USE SIGNAL ;
    SHAPE ABUTMENT ;
    PORT
      LAYER M4 ;
      RECT 0.000 35.904 0.024 35.928 ;
    END
  END rd_out[176]
  PIN rd_out[177]
    DIRECTION OUTPUT ;
    USE SIGNAL ;
    SHAPE ABUTMENT ;
    PORT
      LAYER M4 ;
      RECT 0.000 36.096 0.024 36.120 ;
    END
  END rd_out[177]
  PIN rd_out[178]
    DIRECTION OUTPUT ;
    USE SIGNAL ;
    SHAPE ABUTMENT ;
    PORT
      LAYER M4 ;
      RECT 0.000 36.288 0.024 36.312 ;
    END
  END rd_out[178]
  PIN rd_out[179]
    DIRECTION OUTPUT ;
    USE SIGNAL ;
    SHAPE ABUTMENT ;
    PORT
      LAYER M4 ;
      RECT 0.000 36.480 0.024 36.504 ;
    END
  END rd_out[179]
  PIN rd_out[180]
    DIRECTION OUTPUT ;
    USE SIGNAL ;
    SHAPE ABUTMENT ;
    PORT
      LAYER M4 ;
      RECT 0.000 36.672 0.024 36.696 ;
    END
  END rd_out[180]
  PIN rd_out[181]
    DIRECTION OUTPUT ;
    USE SIGNAL ;
    SHAPE ABUTMENT ;
    PORT
      LAYER M4 ;
      RECT 0.000 36.864 0.024 36.888 ;
    END
  END rd_out[181]
  PIN rd_out[182]
    DIRECTION OUTPUT ;
    USE SIGNAL ;
    SHAPE ABUTMENT ;
    PORT
      LAYER M4 ;
      RECT 0.000 37.056 0.024 37.080 ;
    END
  END rd_out[182]
  PIN rd_out[183]
    DIRECTION OUTPUT ;
    USE SIGNAL ;
    SHAPE ABUTMENT ;
    PORT
      LAYER M4 ;
      RECT 0.000 37.248 0.024 37.272 ;
    END
  END rd_out[183]
  PIN rd_out[184]
    DIRECTION OUTPUT ;
    USE SIGNAL ;
    SHAPE ABUTMENT ;
    PORT
      LAYER M4 ;
      RECT 0.000 37.440 0.024 37.464 ;
    END
  END rd_out[184]
  PIN rd_out[185]
    DIRECTION OUTPUT ;
    USE SIGNAL ;
    SHAPE ABUTMENT ;
    PORT
      LAYER M4 ;
      RECT 0.000 37.632 0.024 37.656 ;
    END
  END rd_out[185]
  PIN rd_out[186]
    DIRECTION OUTPUT ;
    USE SIGNAL ;
    SHAPE ABUTMENT ;
    PORT
      LAYER M4 ;
      RECT 0.000 37.824 0.024 37.848 ;
    END
  END rd_out[186]
  PIN rd_out[187]
    DIRECTION OUTPUT ;
    USE SIGNAL ;
    SHAPE ABUTMENT ;
    PORT
      LAYER M4 ;
      RECT 0.000 38.016 0.024 38.040 ;
    END
  END rd_out[187]
  PIN rd_out[188]
    DIRECTION OUTPUT ;
    USE SIGNAL ;
    SHAPE ABUTMENT ;
    PORT
      LAYER M4 ;
      RECT 0.000 38.208 0.024 38.232 ;
    END
  END rd_out[188]
  PIN rd_out[189]
    DIRECTION OUTPUT ;
    USE SIGNAL ;
    SHAPE ABUTMENT ;
    PORT
      LAYER M4 ;
      RECT 0.000 38.400 0.024 38.424 ;
    END
  END rd_out[189]
  PIN rd_out[190]
    DIRECTION OUTPUT ;
    USE SIGNAL ;
    SHAPE ABUTMENT ;
    PORT
      LAYER M4 ;
      RECT 0.000 38.592 0.024 38.616 ;
    END
  END rd_out[190]
  PIN rd_out[191]
    DIRECTION OUTPUT ;
    USE SIGNAL ;
    SHAPE ABUTMENT ;
    PORT
      LAYER M4 ;
      RECT 0.000 38.784 0.024 38.808 ;
    END
  END rd_out[191]
  PIN rd_out[192]
    DIRECTION OUTPUT ;
    USE SIGNAL ;
    SHAPE ABUTMENT ;
    PORT
      LAYER M4 ;
      RECT 0.000 38.976 0.024 39.000 ;
    END
  END rd_out[192]
  PIN rd_out[193]
    DIRECTION OUTPUT ;
    USE SIGNAL ;
    SHAPE ABUTMENT ;
    PORT
      LAYER M4 ;
      RECT 0.000 39.168 0.024 39.192 ;
    END
  END rd_out[193]
  PIN rd_out[194]
    DIRECTION OUTPUT ;
    USE SIGNAL ;
    SHAPE ABUTMENT ;
    PORT
      LAYER M4 ;
      RECT 0.000 39.360 0.024 39.384 ;
    END
  END rd_out[194]
  PIN rd_out[195]
    DIRECTION OUTPUT ;
    USE SIGNAL ;
    SHAPE ABUTMENT ;
    PORT
      LAYER M4 ;
      RECT 0.000 39.552 0.024 39.576 ;
    END
  END rd_out[195]
  PIN rd_out[196]
    DIRECTION OUTPUT ;
    USE SIGNAL ;
    SHAPE ABUTMENT ;
    PORT
      LAYER M4 ;
      RECT 0.000 39.744 0.024 39.768 ;
    END
  END rd_out[196]
  PIN rd_out[197]
    DIRECTION OUTPUT ;
    USE SIGNAL ;
    SHAPE ABUTMENT ;
    PORT
      LAYER M4 ;
      RECT 0.000 39.936 0.024 39.960 ;
    END
  END rd_out[197]
  PIN rd_out[198]
    DIRECTION OUTPUT ;
    USE SIGNAL ;
    SHAPE ABUTMENT ;
    PORT
      LAYER M4 ;
      RECT 0.000 40.128 0.024 40.152 ;
    END
  END rd_out[198]
  PIN rd_out[199]
    DIRECTION OUTPUT ;
    USE SIGNAL ;
    SHAPE ABUTMENT ;
    PORT
      LAYER M4 ;
      RECT 0.000 40.320 0.024 40.344 ;
    END
  END rd_out[199]
  PIN rd_out[200]
    DIRECTION OUTPUT ;
    USE SIGNAL ;
    SHAPE ABUTMENT ;
    PORT
      LAYER M4 ;
      RECT 0.000 40.512 0.024 40.536 ;
    END
  END rd_out[200]
  PIN rd_out[201]
    DIRECTION OUTPUT ;
    USE SIGNAL ;
    SHAPE ABUTMENT ;
    PORT
      LAYER M4 ;
      RECT 0.000 40.704 0.024 40.728 ;
    END
  END rd_out[201]
  PIN rd_out[202]
    DIRECTION OUTPUT ;
    USE SIGNAL ;
    SHAPE ABUTMENT ;
    PORT
      LAYER M4 ;
      RECT 0.000 40.896 0.024 40.920 ;
    END
  END rd_out[202]
  PIN rd_out[203]
    DIRECTION OUTPUT ;
    USE SIGNAL ;
    SHAPE ABUTMENT ;
    PORT
      LAYER M4 ;
      RECT 0.000 41.088 0.024 41.112 ;
    END
  END rd_out[203]
  PIN rd_out[204]
    DIRECTION OUTPUT ;
    USE SIGNAL ;
    SHAPE ABUTMENT ;
    PORT
      LAYER M4 ;
      RECT 0.000 41.280 0.024 41.304 ;
    END
  END rd_out[204]
  PIN rd_out[205]
    DIRECTION OUTPUT ;
    USE SIGNAL ;
    SHAPE ABUTMENT ;
    PORT
      LAYER M4 ;
      RECT 0.000 41.472 0.024 41.496 ;
    END
  END rd_out[205]
  PIN rd_out[206]
    DIRECTION OUTPUT ;
    USE SIGNAL ;
    SHAPE ABUTMENT ;
    PORT
      LAYER M4 ;
      RECT 0.000 41.664 0.024 41.688 ;
    END
  END rd_out[206]
  PIN rd_out[207]
    DIRECTION OUTPUT ;
    USE SIGNAL ;
    SHAPE ABUTMENT ;
    PORT
      LAYER M4 ;
      RECT 0.000 41.856 0.024 41.880 ;
    END
  END rd_out[207]
  PIN rd_out[208]
    DIRECTION OUTPUT ;
    USE SIGNAL ;
    SHAPE ABUTMENT ;
    PORT
      LAYER M4 ;
      RECT 0.000 42.048 0.024 42.072 ;
    END
  END rd_out[208]
  PIN rd_out[209]
    DIRECTION OUTPUT ;
    USE SIGNAL ;
    SHAPE ABUTMENT ;
    PORT
      LAYER M4 ;
      RECT 0.000 42.240 0.024 42.264 ;
    END
  END rd_out[209]
  PIN rd_out[210]
    DIRECTION OUTPUT ;
    USE SIGNAL ;
    SHAPE ABUTMENT ;
    PORT
      LAYER M4 ;
      RECT 0.000 42.432 0.024 42.456 ;
    END
  END rd_out[210]
  PIN rd_out[211]
    DIRECTION OUTPUT ;
    USE SIGNAL ;
    SHAPE ABUTMENT ;
    PORT
      LAYER M4 ;
      RECT 0.000 42.624 0.024 42.648 ;
    END
  END rd_out[211]
  PIN rd_out[212]
    DIRECTION OUTPUT ;
    USE SIGNAL ;
    SHAPE ABUTMENT ;
    PORT
      LAYER M4 ;
      RECT 0.000 42.816 0.024 42.840 ;
    END
  END rd_out[212]
  PIN rd_out[213]
    DIRECTION OUTPUT ;
    USE SIGNAL ;
    SHAPE ABUTMENT ;
    PORT
      LAYER M4 ;
      RECT 0.000 43.008 0.024 43.032 ;
    END
  END rd_out[213]
  PIN rd_out[214]
    DIRECTION OUTPUT ;
    USE SIGNAL ;
    SHAPE ABUTMENT ;
    PORT
      LAYER M4 ;
      RECT 0.000 43.200 0.024 43.224 ;
    END
  END rd_out[214]
  PIN rd_out[215]
    DIRECTION OUTPUT ;
    USE SIGNAL ;
    SHAPE ABUTMENT ;
    PORT
      LAYER M4 ;
      RECT 0.000 43.392 0.024 43.416 ;
    END
  END rd_out[215]
  PIN rd_out[216]
    DIRECTION OUTPUT ;
    USE SIGNAL ;
    SHAPE ABUTMENT ;
    PORT
      LAYER M4 ;
      RECT 0.000 43.584 0.024 43.608 ;
    END
  END rd_out[216]
  PIN rd_out[217]
    DIRECTION OUTPUT ;
    USE SIGNAL ;
    SHAPE ABUTMENT ;
    PORT
      LAYER M4 ;
      RECT 0.000 43.776 0.024 43.800 ;
    END
  END rd_out[217]
  PIN rd_out[218]
    DIRECTION OUTPUT ;
    USE SIGNAL ;
    SHAPE ABUTMENT ;
    PORT
      LAYER M4 ;
      RECT 0.000 43.968 0.024 43.992 ;
    END
  END rd_out[218]
  PIN rd_out[219]
    DIRECTION OUTPUT ;
    USE SIGNAL ;
    SHAPE ABUTMENT ;
    PORT
      LAYER M4 ;
      RECT 0.000 44.160 0.024 44.184 ;
    END
  END rd_out[219]
  PIN rd_out[220]
    DIRECTION OUTPUT ;
    USE SIGNAL ;
    SHAPE ABUTMENT ;
    PORT
      LAYER M4 ;
      RECT 0.000 44.352 0.024 44.376 ;
    END
  END rd_out[220]
  PIN rd_out[221]
    DIRECTION OUTPUT ;
    USE SIGNAL ;
    SHAPE ABUTMENT ;
    PORT
      LAYER M4 ;
      RECT 0.000 44.544 0.024 44.568 ;
    END
  END rd_out[221]
  PIN rd_out[222]
    DIRECTION OUTPUT ;
    USE SIGNAL ;
    SHAPE ABUTMENT ;
    PORT
      LAYER M4 ;
      RECT 0.000 44.736 0.024 44.760 ;
    END
  END rd_out[222]
  PIN rd_out[223]
    DIRECTION OUTPUT ;
    USE SIGNAL ;
    SHAPE ABUTMENT ;
    PORT
      LAYER M4 ;
      RECT 0.000 44.928 0.024 44.952 ;
    END
  END rd_out[223]
  PIN rd_out[224]
    DIRECTION OUTPUT ;
    USE SIGNAL ;
    SHAPE ABUTMENT ;
    PORT
      LAYER M4 ;
      RECT 0.000 45.120 0.024 45.144 ;
    END
  END rd_out[224]
  PIN rd_out[225]
    DIRECTION OUTPUT ;
    USE SIGNAL ;
    SHAPE ABUTMENT ;
    PORT
      LAYER M4 ;
      RECT 0.000 45.312 0.024 45.336 ;
    END
  END rd_out[225]
  PIN rd_out[226]
    DIRECTION OUTPUT ;
    USE SIGNAL ;
    SHAPE ABUTMENT ;
    PORT
      LAYER M4 ;
      RECT 0.000 45.504 0.024 45.528 ;
    END
  END rd_out[226]
  PIN rd_out[227]
    DIRECTION OUTPUT ;
    USE SIGNAL ;
    SHAPE ABUTMENT ;
    PORT
      LAYER M4 ;
      RECT 0.000 45.696 0.024 45.720 ;
    END
  END rd_out[227]
  PIN rd_out[228]
    DIRECTION OUTPUT ;
    USE SIGNAL ;
    SHAPE ABUTMENT ;
    PORT
      LAYER M4 ;
      RECT 0.000 45.888 0.024 45.912 ;
    END
  END rd_out[228]
  PIN rd_out[229]
    DIRECTION OUTPUT ;
    USE SIGNAL ;
    SHAPE ABUTMENT ;
    PORT
      LAYER M4 ;
      RECT 0.000 46.080 0.024 46.104 ;
    END
  END rd_out[229]
  PIN rd_out[230]
    DIRECTION OUTPUT ;
    USE SIGNAL ;
    SHAPE ABUTMENT ;
    PORT
      LAYER M4 ;
      RECT 0.000 46.272 0.024 46.296 ;
    END
  END rd_out[230]
  PIN rd_out[231]
    DIRECTION OUTPUT ;
    USE SIGNAL ;
    SHAPE ABUTMENT ;
    PORT
      LAYER M4 ;
      RECT 0.000 46.464 0.024 46.488 ;
    END
  END rd_out[231]
  PIN rd_out[232]
    DIRECTION OUTPUT ;
    USE SIGNAL ;
    SHAPE ABUTMENT ;
    PORT
      LAYER M4 ;
      RECT 0.000 46.656 0.024 46.680 ;
    END
  END rd_out[232]
  PIN rd_out[233]
    DIRECTION OUTPUT ;
    USE SIGNAL ;
    SHAPE ABUTMENT ;
    PORT
      LAYER M4 ;
      RECT 0.000 46.848 0.024 46.872 ;
    END
  END rd_out[233]
  PIN rd_out[234]
    DIRECTION OUTPUT ;
    USE SIGNAL ;
    SHAPE ABUTMENT ;
    PORT
      LAYER M4 ;
      RECT 0.000 47.040 0.024 47.064 ;
    END
  END rd_out[234]
  PIN rd_out[235]
    DIRECTION OUTPUT ;
    USE SIGNAL ;
    SHAPE ABUTMENT ;
    PORT
      LAYER M4 ;
      RECT 0.000 47.232 0.024 47.256 ;
    END
  END rd_out[235]
  PIN rd_out[236]
    DIRECTION OUTPUT ;
    USE SIGNAL ;
    SHAPE ABUTMENT ;
    PORT
      LAYER M4 ;
      RECT 0.000 47.424 0.024 47.448 ;
    END
  END rd_out[236]
  PIN rd_out[237]
    DIRECTION OUTPUT ;
    USE SIGNAL ;
    SHAPE ABUTMENT ;
    PORT
      LAYER M4 ;
      RECT 0.000 47.616 0.024 47.640 ;
    END
  END rd_out[237]
  PIN rd_out[238]
    DIRECTION OUTPUT ;
    USE SIGNAL ;
    SHAPE ABUTMENT ;
    PORT
      LAYER M4 ;
      RECT 0.000 47.808 0.024 47.832 ;
    END
  END rd_out[238]
  PIN rd_out[239]
    DIRECTION OUTPUT ;
    USE SIGNAL ;
    SHAPE ABUTMENT ;
    PORT
      LAYER M4 ;
      RECT 0.000 48.000 0.024 48.024 ;
    END
  END rd_out[239]
  PIN rd_out[240]
    DIRECTION OUTPUT ;
    USE SIGNAL ;
    SHAPE ABUTMENT ;
    PORT
      LAYER M4 ;
      RECT 0.000 48.192 0.024 48.216 ;
    END
  END rd_out[240]
  PIN rd_out[241]
    DIRECTION OUTPUT ;
    USE SIGNAL ;
    SHAPE ABUTMENT ;
    PORT
      LAYER M4 ;
      RECT 0.000 48.384 0.024 48.408 ;
    END
  END rd_out[241]
  PIN rd_out[242]
    DIRECTION OUTPUT ;
    USE SIGNAL ;
    SHAPE ABUTMENT ;
    PORT
      LAYER M4 ;
      RECT 0.000 48.576 0.024 48.600 ;
    END
  END rd_out[242]
  PIN rd_out[243]
    DIRECTION OUTPUT ;
    USE SIGNAL ;
    SHAPE ABUTMENT ;
    PORT
      LAYER M4 ;
      RECT 0.000 48.768 0.024 48.792 ;
    END
  END rd_out[243]
  PIN rd_out[244]
    DIRECTION OUTPUT ;
    USE SIGNAL ;
    SHAPE ABUTMENT ;
    PORT
      LAYER M4 ;
      RECT 0.000 48.960 0.024 48.984 ;
    END
  END rd_out[244]
  PIN rd_out[245]
    DIRECTION OUTPUT ;
    USE SIGNAL ;
    SHAPE ABUTMENT ;
    PORT
      LAYER M4 ;
      RECT 0.000 49.152 0.024 49.176 ;
    END
  END rd_out[245]
  PIN rd_out[246]
    DIRECTION OUTPUT ;
    USE SIGNAL ;
    SHAPE ABUTMENT ;
    PORT
      LAYER M4 ;
      RECT 0.000 49.344 0.024 49.368 ;
    END
  END rd_out[246]
  PIN rd_out[247]
    DIRECTION OUTPUT ;
    USE SIGNAL ;
    SHAPE ABUTMENT ;
    PORT
      LAYER M4 ;
      RECT 0.000 49.536 0.024 49.560 ;
    END
  END rd_out[247]
  PIN rd_out[248]
    DIRECTION OUTPUT ;
    USE SIGNAL ;
    SHAPE ABUTMENT ;
    PORT
      LAYER M4 ;
      RECT 0.000 49.728 0.024 49.752 ;
    END
  END rd_out[248]
  PIN rd_out[249]
    DIRECTION OUTPUT ;
    USE SIGNAL ;
    SHAPE ABUTMENT ;
    PORT
      LAYER M4 ;
      RECT 0.000 49.920 0.024 49.944 ;
    END
  END rd_out[249]
  PIN rd_out[250]
    DIRECTION OUTPUT ;
    USE SIGNAL ;
    SHAPE ABUTMENT ;
    PORT
      LAYER M4 ;
      RECT 0.000 50.112 0.024 50.136 ;
    END
  END rd_out[250]
  PIN rd_out[251]
    DIRECTION OUTPUT ;
    USE SIGNAL ;
    SHAPE ABUTMENT ;
    PORT
      LAYER M4 ;
      RECT 0.000 50.304 0.024 50.328 ;
    END
  END rd_out[251]
  PIN rd_out[252]
    DIRECTION OUTPUT ;
    USE SIGNAL ;
    SHAPE ABUTMENT ;
    PORT
      LAYER M4 ;
      RECT 0.000 50.496 0.024 50.520 ;
    END
  END rd_out[252]
  PIN rd_out[253]
    DIRECTION OUTPUT ;
    USE SIGNAL ;
    SHAPE ABUTMENT ;
    PORT
      LAYER M4 ;
      RECT 0.000 50.688 0.024 50.712 ;
    END
  END rd_out[253]
  PIN rd_out[254]
    DIRECTION OUTPUT ;
    USE SIGNAL ;
    SHAPE ABUTMENT ;
    PORT
      LAYER M4 ;
      RECT 0.000 50.880 0.024 50.904 ;
    END
  END rd_out[254]
  PIN rd_out[255]
    DIRECTION OUTPUT ;
    USE SIGNAL ;
    SHAPE ABUTMENT ;
    PORT
      LAYER M4 ;
      RECT 0.000 51.072 0.024 51.096 ;
    END
  END rd_out[255]
  PIN rd_out[256]
    DIRECTION OUTPUT ;
    USE SIGNAL ;
    SHAPE ABUTMENT ;
    PORT
      LAYER M4 ;
      RECT 0.000 51.264 0.024 51.288 ;
    END
  END rd_out[256]
  PIN rd_out[257]
    DIRECTION OUTPUT ;
    USE SIGNAL ;
    SHAPE ABUTMENT ;
    PORT
      LAYER M4 ;
      RECT 0.000 51.456 0.024 51.480 ;
    END
  END rd_out[257]
  PIN rd_out[258]
    DIRECTION OUTPUT ;
    USE SIGNAL ;
    SHAPE ABUTMENT ;
    PORT
      LAYER M4 ;
      RECT 0.000 51.648 0.024 51.672 ;
    END
  END rd_out[258]
  PIN rd_out[259]
    DIRECTION OUTPUT ;
    USE SIGNAL ;
    SHAPE ABUTMENT ;
    PORT
      LAYER M4 ;
      RECT 0.000 51.840 0.024 51.864 ;
    END
  END rd_out[259]
  PIN rd_out[260]
    DIRECTION OUTPUT ;
    USE SIGNAL ;
    SHAPE ABUTMENT ;
    PORT
      LAYER M4 ;
      RECT 0.000 52.032 0.024 52.056 ;
    END
  END rd_out[260]
  PIN rd_out[261]
    DIRECTION OUTPUT ;
    USE SIGNAL ;
    SHAPE ABUTMENT ;
    PORT
      LAYER M4 ;
      RECT 0.000 52.224 0.024 52.248 ;
    END
  END rd_out[261]
  PIN rd_out[262]
    DIRECTION OUTPUT ;
    USE SIGNAL ;
    SHAPE ABUTMENT ;
    PORT
      LAYER M4 ;
      RECT 0.000 52.416 0.024 52.440 ;
    END
  END rd_out[262]
  PIN rd_out[263]
    DIRECTION OUTPUT ;
    USE SIGNAL ;
    SHAPE ABUTMENT ;
    PORT
      LAYER M4 ;
      RECT 0.000 52.608 0.024 52.632 ;
    END
  END rd_out[263]
  PIN rd_out[264]
    DIRECTION OUTPUT ;
    USE SIGNAL ;
    SHAPE ABUTMENT ;
    PORT
      LAYER M4 ;
      RECT 0.000 52.800 0.024 52.824 ;
    END
  END rd_out[264]
  PIN rd_out[265]
    DIRECTION OUTPUT ;
    USE SIGNAL ;
    SHAPE ABUTMENT ;
    PORT
      LAYER M4 ;
      RECT 0.000 52.992 0.024 53.016 ;
    END
  END rd_out[265]
  PIN rd_out[266]
    DIRECTION OUTPUT ;
    USE SIGNAL ;
    SHAPE ABUTMENT ;
    PORT
      LAYER M4 ;
      RECT 0.000 53.184 0.024 53.208 ;
    END
  END rd_out[266]
  PIN rd_out[267]
    DIRECTION OUTPUT ;
    USE SIGNAL ;
    SHAPE ABUTMENT ;
    PORT
      LAYER M4 ;
      RECT 0.000 53.376 0.024 53.400 ;
    END
  END rd_out[267]
  PIN rd_out[268]
    DIRECTION OUTPUT ;
    USE SIGNAL ;
    SHAPE ABUTMENT ;
    PORT
      LAYER M4 ;
      RECT 0.000 53.568 0.024 53.592 ;
    END
  END rd_out[268]
  PIN rd_out[269]
    DIRECTION OUTPUT ;
    USE SIGNAL ;
    SHAPE ABUTMENT ;
    PORT
      LAYER M4 ;
      RECT 0.000 53.760 0.024 53.784 ;
    END
  END rd_out[269]
  PIN rd_out[270]
    DIRECTION OUTPUT ;
    USE SIGNAL ;
    SHAPE ABUTMENT ;
    PORT
      LAYER M4 ;
      RECT 0.000 53.952 0.024 53.976 ;
    END
  END rd_out[270]
  PIN rd_out[271]
    DIRECTION OUTPUT ;
    USE SIGNAL ;
    SHAPE ABUTMENT ;
    PORT
      LAYER M4 ;
      RECT 0.000 54.144 0.024 54.168 ;
    END
  END rd_out[271]
  PIN rd_out[272]
    DIRECTION OUTPUT ;
    USE SIGNAL ;
    SHAPE ABUTMENT ;
    PORT
      LAYER M4 ;
      RECT 0.000 54.336 0.024 54.360 ;
    END
  END rd_out[272]
  PIN rd_out[273]
    DIRECTION OUTPUT ;
    USE SIGNAL ;
    SHAPE ABUTMENT ;
    PORT
      LAYER M4 ;
      RECT 0.000 54.528 0.024 54.552 ;
    END
  END rd_out[273]
  PIN rd_out[274]
    DIRECTION OUTPUT ;
    USE SIGNAL ;
    SHAPE ABUTMENT ;
    PORT
      LAYER M4 ;
      RECT 0.000 54.720 0.024 54.744 ;
    END
  END rd_out[274]
  PIN rd_out[275]
    DIRECTION OUTPUT ;
    USE SIGNAL ;
    SHAPE ABUTMENT ;
    PORT
      LAYER M4 ;
      RECT 0.000 54.912 0.024 54.936 ;
    END
  END rd_out[275]
  PIN rd_out[276]
    DIRECTION OUTPUT ;
    USE SIGNAL ;
    SHAPE ABUTMENT ;
    PORT
      LAYER M4 ;
      RECT 0.000 55.104 0.024 55.128 ;
    END
  END rd_out[276]
  PIN rd_out[277]
    DIRECTION OUTPUT ;
    USE SIGNAL ;
    SHAPE ABUTMENT ;
    PORT
      LAYER M4 ;
      RECT 0.000 55.296 0.024 55.320 ;
    END
  END rd_out[277]
  PIN rd_out[278]
    DIRECTION OUTPUT ;
    USE SIGNAL ;
    SHAPE ABUTMENT ;
    PORT
      LAYER M4 ;
      RECT 0.000 55.488 0.024 55.512 ;
    END
  END rd_out[278]
  PIN rd_out[279]
    DIRECTION OUTPUT ;
    USE SIGNAL ;
    SHAPE ABUTMENT ;
    PORT
      LAYER M4 ;
      RECT 0.000 55.680 0.024 55.704 ;
    END
  END rd_out[279]
  PIN rd_out[280]
    DIRECTION OUTPUT ;
    USE SIGNAL ;
    SHAPE ABUTMENT ;
    PORT
      LAYER M4 ;
      RECT 0.000 55.872 0.024 55.896 ;
    END
  END rd_out[280]
  PIN rd_out[281]
    DIRECTION OUTPUT ;
    USE SIGNAL ;
    SHAPE ABUTMENT ;
    PORT
      LAYER M4 ;
      RECT 0.000 56.064 0.024 56.088 ;
    END
  END rd_out[281]
  PIN rd_out[282]
    DIRECTION OUTPUT ;
    USE SIGNAL ;
    SHAPE ABUTMENT ;
    PORT
      LAYER M4 ;
      RECT 0.000 56.256 0.024 56.280 ;
    END
  END rd_out[282]
  PIN rd_out[283]
    DIRECTION OUTPUT ;
    USE SIGNAL ;
    SHAPE ABUTMENT ;
    PORT
      LAYER M4 ;
      RECT 0.000 56.448 0.024 56.472 ;
    END
  END rd_out[283]
  PIN rd_out[284]
    DIRECTION OUTPUT ;
    USE SIGNAL ;
    SHAPE ABUTMENT ;
    PORT
      LAYER M4 ;
      RECT 0.000 56.640 0.024 56.664 ;
    END
  END rd_out[284]
  PIN rd_out[285]
    DIRECTION OUTPUT ;
    USE SIGNAL ;
    SHAPE ABUTMENT ;
    PORT
      LAYER M4 ;
      RECT 0.000 56.832 0.024 56.856 ;
    END
  END rd_out[285]
  PIN rd_out[286]
    DIRECTION OUTPUT ;
    USE SIGNAL ;
    SHAPE ABUTMENT ;
    PORT
      LAYER M4 ;
      RECT 0.000 57.024 0.024 57.048 ;
    END
  END rd_out[286]
  PIN rd_out[287]
    DIRECTION OUTPUT ;
    USE SIGNAL ;
    SHAPE ABUTMENT ;
    PORT
      LAYER M4 ;
      RECT 0.000 57.216 0.024 57.240 ;
    END
  END rd_out[287]
  PIN rd_out[288]
    DIRECTION OUTPUT ;
    USE SIGNAL ;
    SHAPE ABUTMENT ;
    PORT
      LAYER M4 ;
      RECT 0.000 57.408 0.024 57.432 ;
    END
  END rd_out[288]
  PIN rd_out[289]
    DIRECTION OUTPUT ;
    USE SIGNAL ;
    SHAPE ABUTMENT ;
    PORT
      LAYER M4 ;
      RECT 0.000 57.600 0.024 57.624 ;
    END
  END rd_out[289]
  PIN rd_out[290]
    DIRECTION OUTPUT ;
    USE SIGNAL ;
    SHAPE ABUTMENT ;
    PORT
      LAYER M4 ;
      RECT 0.000 57.792 0.024 57.816 ;
    END
  END rd_out[290]
  PIN rd_out[291]
    DIRECTION OUTPUT ;
    USE SIGNAL ;
    SHAPE ABUTMENT ;
    PORT
      LAYER M4 ;
      RECT 0.000 57.984 0.024 58.008 ;
    END
  END rd_out[291]
  PIN rd_out[292]
    DIRECTION OUTPUT ;
    USE SIGNAL ;
    SHAPE ABUTMENT ;
    PORT
      LAYER M4 ;
      RECT 0.000 58.176 0.024 58.200 ;
    END
  END rd_out[292]
  PIN rd_out[293]
    DIRECTION OUTPUT ;
    USE SIGNAL ;
    SHAPE ABUTMENT ;
    PORT
      LAYER M4 ;
      RECT 0.000 58.368 0.024 58.392 ;
    END
  END rd_out[293]
  PIN rd_out[294]
    DIRECTION OUTPUT ;
    USE SIGNAL ;
    SHAPE ABUTMENT ;
    PORT
      LAYER M4 ;
      RECT 0.000 58.560 0.024 58.584 ;
    END
  END rd_out[294]
  PIN rd_out[295]
    DIRECTION OUTPUT ;
    USE SIGNAL ;
    SHAPE ABUTMENT ;
    PORT
      LAYER M4 ;
      RECT 0.000 58.752 0.024 58.776 ;
    END
  END rd_out[295]
  PIN rd_out[296]
    DIRECTION OUTPUT ;
    USE SIGNAL ;
    SHAPE ABUTMENT ;
    PORT
      LAYER M4 ;
      RECT 0.000 58.944 0.024 58.968 ;
    END
  END rd_out[296]
  PIN rd_out[297]
    DIRECTION OUTPUT ;
    USE SIGNAL ;
    SHAPE ABUTMENT ;
    PORT
      LAYER M4 ;
      RECT 0.000 59.136 0.024 59.160 ;
    END
  END rd_out[297]
  PIN rd_out[298]
    DIRECTION OUTPUT ;
    USE SIGNAL ;
    SHAPE ABUTMENT ;
    PORT
      LAYER M4 ;
      RECT 0.000 59.328 0.024 59.352 ;
    END
  END rd_out[298]
  PIN rd_out[299]
    DIRECTION OUTPUT ;
    USE SIGNAL ;
    SHAPE ABUTMENT ;
    PORT
      LAYER M4 ;
      RECT 0.000 59.520 0.024 59.544 ;
    END
  END rd_out[299]
  PIN rd_out[300]
    DIRECTION OUTPUT ;
    USE SIGNAL ;
    SHAPE ABUTMENT ;
    PORT
      LAYER M4 ;
      RECT 0.000 59.712 0.024 59.736 ;
    END
  END rd_out[300]
  PIN rd_out[301]
    DIRECTION OUTPUT ;
    USE SIGNAL ;
    SHAPE ABUTMENT ;
    PORT
      LAYER M4 ;
      RECT 0.000 59.904 0.024 59.928 ;
    END
  END rd_out[301]
  PIN rd_out[302]
    DIRECTION OUTPUT ;
    USE SIGNAL ;
    SHAPE ABUTMENT ;
    PORT
      LAYER M4 ;
      RECT 0.000 60.096 0.024 60.120 ;
    END
  END rd_out[302]
  PIN rd_out[303]
    DIRECTION OUTPUT ;
    USE SIGNAL ;
    SHAPE ABUTMENT ;
    PORT
      LAYER M4 ;
      RECT 0.000 60.288 0.024 60.312 ;
    END
  END rd_out[303]
  PIN rd_out[304]
    DIRECTION OUTPUT ;
    USE SIGNAL ;
    SHAPE ABUTMENT ;
    PORT
      LAYER M4 ;
      RECT 0.000 60.480 0.024 60.504 ;
    END
  END rd_out[304]
  PIN rd_out[305]
    DIRECTION OUTPUT ;
    USE SIGNAL ;
    SHAPE ABUTMENT ;
    PORT
      LAYER M4 ;
      RECT 0.000 60.672 0.024 60.696 ;
    END
  END rd_out[305]
  PIN rd_out[306]
    DIRECTION OUTPUT ;
    USE SIGNAL ;
    SHAPE ABUTMENT ;
    PORT
      LAYER M4 ;
      RECT 0.000 60.864 0.024 60.888 ;
    END
  END rd_out[306]
  PIN rd_out[307]
    DIRECTION OUTPUT ;
    USE SIGNAL ;
    SHAPE ABUTMENT ;
    PORT
      LAYER M4 ;
      RECT 0.000 61.056 0.024 61.080 ;
    END
  END rd_out[307]
  PIN rd_out[308]
    DIRECTION OUTPUT ;
    USE SIGNAL ;
    SHAPE ABUTMENT ;
    PORT
      LAYER M4 ;
      RECT 0.000 61.248 0.024 61.272 ;
    END
  END rd_out[308]
  PIN rd_out[309]
    DIRECTION OUTPUT ;
    USE SIGNAL ;
    SHAPE ABUTMENT ;
    PORT
      LAYER M4 ;
      RECT 0.000 61.440 0.024 61.464 ;
    END
  END rd_out[309]
  PIN rd_out[310]
    DIRECTION OUTPUT ;
    USE SIGNAL ;
    SHAPE ABUTMENT ;
    PORT
      LAYER M4 ;
      RECT 0.000 61.632 0.024 61.656 ;
    END
  END rd_out[310]
  PIN rd_out[311]
    DIRECTION OUTPUT ;
    USE SIGNAL ;
    SHAPE ABUTMENT ;
    PORT
      LAYER M4 ;
      RECT 0.000 61.824 0.024 61.848 ;
    END
  END rd_out[311]
  PIN rd_out[312]
    DIRECTION OUTPUT ;
    USE SIGNAL ;
    SHAPE ABUTMENT ;
    PORT
      LAYER M4 ;
      RECT 0.000 62.016 0.024 62.040 ;
    END
  END rd_out[312]
  PIN rd_out[313]
    DIRECTION OUTPUT ;
    USE SIGNAL ;
    SHAPE ABUTMENT ;
    PORT
      LAYER M4 ;
      RECT 0.000 62.208 0.024 62.232 ;
    END
  END rd_out[313]
  PIN rd_out[314]
    DIRECTION OUTPUT ;
    USE SIGNAL ;
    SHAPE ABUTMENT ;
    PORT
      LAYER M4 ;
      RECT 0.000 62.400 0.024 62.424 ;
    END
  END rd_out[314]
  PIN rd_out[315]
    DIRECTION OUTPUT ;
    USE SIGNAL ;
    SHAPE ABUTMENT ;
    PORT
      LAYER M4 ;
      RECT 0.000 62.592 0.024 62.616 ;
    END
  END rd_out[315]
  PIN rd_out[316]
    DIRECTION OUTPUT ;
    USE SIGNAL ;
    SHAPE ABUTMENT ;
    PORT
      LAYER M4 ;
      RECT 0.000 62.784 0.024 62.808 ;
    END
  END rd_out[316]
  PIN rd_out[317]
    DIRECTION OUTPUT ;
    USE SIGNAL ;
    SHAPE ABUTMENT ;
    PORT
      LAYER M4 ;
      RECT 0.000 62.976 0.024 63.000 ;
    END
  END rd_out[317]
  PIN rd_out[318]
    DIRECTION OUTPUT ;
    USE SIGNAL ;
    SHAPE ABUTMENT ;
    PORT
      LAYER M4 ;
      RECT 0.000 63.168 0.024 63.192 ;
    END
  END rd_out[318]
  PIN rd_out[319]
    DIRECTION OUTPUT ;
    USE SIGNAL ;
    SHAPE ABUTMENT ;
    PORT
      LAYER M4 ;
      RECT 0.000 63.360 0.024 63.384 ;
    END
  END rd_out[319]
  PIN rd_out[320]
    DIRECTION OUTPUT ;
    USE SIGNAL ;
    SHAPE ABUTMENT ;
    PORT
      LAYER M4 ;
      RECT 0.000 63.552 0.024 63.576 ;
    END
  END rd_out[320]
  PIN rd_out[321]
    DIRECTION OUTPUT ;
    USE SIGNAL ;
    SHAPE ABUTMENT ;
    PORT
      LAYER M4 ;
      RECT 0.000 63.744 0.024 63.768 ;
    END
  END rd_out[321]
  PIN rd_out[322]
    DIRECTION OUTPUT ;
    USE SIGNAL ;
    SHAPE ABUTMENT ;
    PORT
      LAYER M4 ;
      RECT 0.000 63.936 0.024 63.960 ;
    END
  END rd_out[322]
  PIN rd_out[323]
    DIRECTION OUTPUT ;
    USE SIGNAL ;
    SHAPE ABUTMENT ;
    PORT
      LAYER M4 ;
      RECT 0.000 64.128 0.024 64.152 ;
    END
  END rd_out[323]
  PIN rd_out[324]
    DIRECTION OUTPUT ;
    USE SIGNAL ;
    SHAPE ABUTMENT ;
    PORT
      LAYER M4 ;
      RECT 0.000 64.320 0.024 64.344 ;
    END
  END rd_out[324]
  PIN rd_out[325]
    DIRECTION OUTPUT ;
    USE SIGNAL ;
    SHAPE ABUTMENT ;
    PORT
      LAYER M4 ;
      RECT 0.000 64.512 0.024 64.536 ;
    END
  END rd_out[325]
  PIN rd_out[326]
    DIRECTION OUTPUT ;
    USE SIGNAL ;
    SHAPE ABUTMENT ;
    PORT
      LAYER M4 ;
      RECT 0.000 64.704 0.024 64.728 ;
    END
  END rd_out[326]
  PIN rd_out[327]
    DIRECTION OUTPUT ;
    USE SIGNAL ;
    SHAPE ABUTMENT ;
    PORT
      LAYER M4 ;
      RECT 0.000 64.896 0.024 64.920 ;
    END
  END rd_out[327]
  PIN rd_out[328]
    DIRECTION OUTPUT ;
    USE SIGNAL ;
    SHAPE ABUTMENT ;
    PORT
      LAYER M4 ;
      RECT 0.000 65.088 0.024 65.112 ;
    END
  END rd_out[328]
  PIN rd_out[329]
    DIRECTION OUTPUT ;
    USE SIGNAL ;
    SHAPE ABUTMENT ;
    PORT
      LAYER M4 ;
      RECT 0.000 65.280 0.024 65.304 ;
    END
  END rd_out[329]
  PIN rd_out[330]
    DIRECTION OUTPUT ;
    USE SIGNAL ;
    SHAPE ABUTMENT ;
    PORT
      LAYER M4 ;
      RECT 0.000 65.472 0.024 65.496 ;
    END
  END rd_out[330]
  PIN rd_out[331]
    DIRECTION OUTPUT ;
    USE SIGNAL ;
    SHAPE ABUTMENT ;
    PORT
      LAYER M4 ;
      RECT 0.000 65.664 0.024 65.688 ;
    END
  END rd_out[331]
  PIN rd_out[332]
    DIRECTION OUTPUT ;
    USE SIGNAL ;
    SHAPE ABUTMENT ;
    PORT
      LAYER M4 ;
      RECT 0.000 65.856 0.024 65.880 ;
    END
  END rd_out[332]
  PIN rd_out[333]
    DIRECTION OUTPUT ;
    USE SIGNAL ;
    SHAPE ABUTMENT ;
    PORT
      LAYER M4 ;
      RECT 0.000 66.048 0.024 66.072 ;
    END
  END rd_out[333]
  PIN rd_out[334]
    DIRECTION OUTPUT ;
    USE SIGNAL ;
    SHAPE ABUTMENT ;
    PORT
      LAYER M4 ;
      RECT 0.000 66.240 0.024 66.264 ;
    END
  END rd_out[334]
  PIN rd_out[335]
    DIRECTION OUTPUT ;
    USE SIGNAL ;
    SHAPE ABUTMENT ;
    PORT
      LAYER M4 ;
      RECT 0.000 66.432 0.024 66.456 ;
    END
  END rd_out[335]
  PIN rd_out[336]
    DIRECTION OUTPUT ;
    USE SIGNAL ;
    SHAPE ABUTMENT ;
    PORT
      LAYER M4 ;
      RECT 0.000 66.624 0.024 66.648 ;
    END
  END rd_out[336]
  PIN rd_out[337]
    DIRECTION OUTPUT ;
    USE SIGNAL ;
    SHAPE ABUTMENT ;
    PORT
      LAYER M4 ;
      RECT 0.000 66.816 0.024 66.840 ;
    END
  END rd_out[337]
  PIN rd_out[338]
    DIRECTION OUTPUT ;
    USE SIGNAL ;
    SHAPE ABUTMENT ;
    PORT
      LAYER M4 ;
      RECT 0.000 67.008 0.024 67.032 ;
    END
  END rd_out[338]
  PIN rd_out[339]
    DIRECTION OUTPUT ;
    USE SIGNAL ;
    SHAPE ABUTMENT ;
    PORT
      LAYER M4 ;
      RECT 0.000 67.200 0.024 67.224 ;
    END
  END rd_out[339]
  PIN w_ce_in
    DIRECTION INPUT ;
    USE SIGNAL ;
    SHAPE ABUTMENT ;
    PORT
      LAYER M4 ;
      RECT 0.000 67.392 0.024 67.416 ;
    END
  END w_ce_in
  PIN w_addr_in[0]
    DIRECTION INPUT ;
    USE SIGNAL ;
    SHAPE ABUTMENT ;
    PORT
      LAYER M4 ;
      RECT 0.000 67.584 0.024 67.608 ;
    END
  END w_addr_in[0]
  PIN w_addr_in[1]
    DIRECTION INPUT ;
    USE SIGNAL ;
    SHAPE ABUTMENT ;
    PORT
      LAYER M4 ;
      RECT 0.000 67.776 0.024 67.800 ;
    END
  END w_addr_in[1]
  PIN w_addr_in[2]
    DIRECTION INPUT ;
    USE SIGNAL ;
    SHAPE ABUTMENT ;
    PORT
      LAYER M4 ;
      RECT 0.000 67.968 0.024 67.992 ;
    END
  END w_addr_in[2]
  PIN w_addr_in[3]
    DIRECTION INPUT ;
    USE SIGNAL ;
    SHAPE ABUTMENT ;
    PORT
      LAYER M4 ;
      RECT 0.000 68.160 0.024 68.184 ;
    END
  END w_addr_in[3]
  PIN wd_in[0]
    DIRECTION INPUT ;
    USE SIGNAL ;
    SHAPE ABUTMENT ;
    PORT
      LAYER M4 ;
      RECT 0.000 68.352 0.024 68.376 ;
    END
  END wd_in[0]
  PIN wd_in[1]
    DIRECTION INPUT ;
    USE SIGNAL ;
    SHAPE ABUTMENT ;
    PORT
      LAYER M4 ;
      RECT 0.000 68.544 0.024 68.568 ;
    END
  END wd_in[1]
  PIN wd_in[2]
    DIRECTION INPUT ;
    USE SIGNAL ;
    SHAPE ABUTMENT ;
    PORT
      LAYER M4 ;
      RECT 0.000 68.736 0.024 68.760 ;
    END
  END wd_in[2]
  PIN wd_in[3]
    DIRECTION INPUT ;
    USE SIGNAL ;
    SHAPE ABUTMENT ;
    PORT
      LAYER M4 ;
      RECT 0.000 68.928 0.024 68.952 ;
    END
  END wd_in[3]
  PIN wd_in[4]
    DIRECTION INPUT ;
    USE SIGNAL ;
    SHAPE ABUTMENT ;
    PORT
      LAYER M4 ;
      RECT 0.000 69.120 0.024 69.144 ;
    END
  END wd_in[4]
  PIN wd_in[5]
    DIRECTION INPUT ;
    USE SIGNAL ;
    SHAPE ABUTMENT ;
    PORT
      LAYER M4 ;
      RECT 0.000 69.312 0.024 69.336 ;
    END
  END wd_in[5]
  PIN wd_in[6]
    DIRECTION INPUT ;
    USE SIGNAL ;
    SHAPE ABUTMENT ;
    PORT
      LAYER M4 ;
      RECT 0.000 69.504 0.024 69.528 ;
    END
  END wd_in[6]
  PIN wd_in[7]
    DIRECTION INPUT ;
    USE SIGNAL ;
    SHAPE ABUTMENT ;
    PORT
      LAYER M4 ;
      RECT 0.000 69.696 0.024 69.720 ;
    END
  END wd_in[7]
  PIN wd_in[8]
    DIRECTION INPUT ;
    USE SIGNAL ;
    SHAPE ABUTMENT ;
    PORT
      LAYER M4 ;
      RECT 0.000 69.888 0.024 69.912 ;
    END
  END wd_in[8]
  PIN wd_in[9]
    DIRECTION INPUT ;
    USE SIGNAL ;
    SHAPE ABUTMENT ;
    PORT
      LAYER M4 ;
      RECT 0.000 70.080 0.024 70.104 ;
    END
  END wd_in[9]
  PIN wd_in[10]
    DIRECTION INPUT ;
    USE SIGNAL ;
    SHAPE ABUTMENT ;
    PORT
      LAYER M4 ;
      RECT 0.000 70.272 0.024 70.296 ;
    END
  END wd_in[10]
  PIN wd_in[11]
    DIRECTION INPUT ;
    USE SIGNAL ;
    SHAPE ABUTMENT ;
    PORT
      LAYER M4 ;
      RECT 0.000 70.464 0.024 70.488 ;
    END
  END wd_in[11]
  PIN wd_in[12]
    DIRECTION INPUT ;
    USE SIGNAL ;
    SHAPE ABUTMENT ;
    PORT
      LAYER M4 ;
      RECT 0.000 70.656 0.024 70.680 ;
    END
  END wd_in[12]
  PIN wd_in[13]
    DIRECTION INPUT ;
    USE SIGNAL ;
    SHAPE ABUTMENT ;
    PORT
      LAYER M4 ;
      RECT 0.000 70.848 0.024 70.872 ;
    END
  END wd_in[13]
  PIN wd_in[14]
    DIRECTION INPUT ;
    USE SIGNAL ;
    SHAPE ABUTMENT ;
    PORT
      LAYER M4 ;
      RECT 0.000 71.040 0.024 71.064 ;
    END
  END wd_in[14]
  PIN wd_in[15]
    DIRECTION INPUT ;
    USE SIGNAL ;
    SHAPE ABUTMENT ;
    PORT
      LAYER M4 ;
      RECT 0.000 71.232 0.024 71.256 ;
    END
  END wd_in[15]
  PIN wd_in[16]
    DIRECTION INPUT ;
    USE SIGNAL ;
    SHAPE ABUTMENT ;
    PORT
      LAYER M4 ;
      RECT 0.000 71.424 0.024 71.448 ;
    END
  END wd_in[16]
  PIN wd_in[17]
    DIRECTION INPUT ;
    USE SIGNAL ;
    SHAPE ABUTMENT ;
    PORT
      LAYER M4 ;
      RECT 0.000 71.616 0.024 71.640 ;
    END
  END wd_in[17]
  PIN wd_in[18]
    DIRECTION INPUT ;
    USE SIGNAL ;
    SHAPE ABUTMENT ;
    PORT
      LAYER M4 ;
      RECT 0.000 71.808 0.024 71.832 ;
    END
  END wd_in[18]
  PIN wd_in[19]
    DIRECTION INPUT ;
    USE SIGNAL ;
    SHAPE ABUTMENT ;
    PORT
      LAYER M4 ;
      RECT 0.000 72.000 0.024 72.024 ;
    END
  END wd_in[19]
  PIN wd_in[20]
    DIRECTION INPUT ;
    USE SIGNAL ;
    SHAPE ABUTMENT ;
    PORT
      LAYER M4 ;
      RECT 0.000 72.192 0.024 72.216 ;
    END
  END wd_in[20]
  PIN wd_in[21]
    DIRECTION INPUT ;
    USE SIGNAL ;
    SHAPE ABUTMENT ;
    PORT
      LAYER M4 ;
      RECT 0.000 72.384 0.024 72.408 ;
    END
  END wd_in[21]
  PIN wd_in[22]
    DIRECTION INPUT ;
    USE SIGNAL ;
    SHAPE ABUTMENT ;
    PORT
      LAYER M4 ;
      RECT 0.000 72.576 0.024 72.600 ;
    END
  END wd_in[22]
  PIN wd_in[23]
    DIRECTION INPUT ;
    USE SIGNAL ;
    SHAPE ABUTMENT ;
    PORT
      LAYER M4 ;
      RECT 0.000 72.768 0.024 72.792 ;
    END
  END wd_in[23]
  PIN wd_in[24]
    DIRECTION INPUT ;
    USE SIGNAL ;
    SHAPE ABUTMENT ;
    PORT
      LAYER M4 ;
      RECT 0.000 72.960 0.024 72.984 ;
    END
  END wd_in[24]
  PIN wd_in[25]
    DIRECTION INPUT ;
    USE SIGNAL ;
    SHAPE ABUTMENT ;
    PORT
      LAYER M4 ;
      RECT 0.000 73.152 0.024 73.176 ;
    END
  END wd_in[25]
  PIN wd_in[26]
    DIRECTION INPUT ;
    USE SIGNAL ;
    SHAPE ABUTMENT ;
    PORT
      LAYER M4 ;
      RECT 0.000 73.344 0.024 73.368 ;
    END
  END wd_in[26]
  PIN wd_in[27]
    DIRECTION INPUT ;
    USE SIGNAL ;
    SHAPE ABUTMENT ;
    PORT
      LAYER M4 ;
      RECT 0.000 73.536 0.024 73.560 ;
    END
  END wd_in[27]
  PIN wd_in[28]
    DIRECTION INPUT ;
    USE SIGNAL ;
    SHAPE ABUTMENT ;
    PORT
      LAYER M4 ;
      RECT 0.000 73.728 0.024 73.752 ;
    END
  END wd_in[28]
  PIN wd_in[29]
    DIRECTION INPUT ;
    USE SIGNAL ;
    SHAPE ABUTMENT ;
    PORT
      LAYER M4 ;
      RECT 0.000 73.920 0.024 73.944 ;
    END
  END wd_in[29]
  PIN wd_in[30]
    DIRECTION INPUT ;
    USE SIGNAL ;
    SHAPE ABUTMENT ;
    PORT
      LAYER M4 ;
      RECT 0.000 74.112 0.024 74.136 ;
    END
  END wd_in[30]
  PIN wd_in[31]
    DIRECTION INPUT ;
    USE SIGNAL ;
    SHAPE ABUTMENT ;
    PORT
      LAYER M4 ;
      RECT 0.000 74.304 0.024 74.328 ;
    END
  END wd_in[31]
  PIN wd_in[32]
    DIRECTION INPUT ;
    USE SIGNAL ;
    SHAPE ABUTMENT ;
    PORT
      LAYER M4 ;
      RECT 0.000 74.496 0.024 74.520 ;
    END
  END wd_in[32]
  PIN wd_in[33]
    DIRECTION INPUT ;
    USE SIGNAL ;
    SHAPE ABUTMENT ;
    PORT
      LAYER M4 ;
      RECT 0.000 74.688 0.024 74.712 ;
    END
  END wd_in[33]
  PIN wd_in[34]
    DIRECTION INPUT ;
    USE SIGNAL ;
    SHAPE ABUTMENT ;
    PORT
      LAYER M4 ;
      RECT 0.000 74.880 0.024 74.904 ;
    END
  END wd_in[34]
  PIN wd_in[35]
    DIRECTION INPUT ;
    USE SIGNAL ;
    SHAPE ABUTMENT ;
    PORT
      LAYER M4 ;
      RECT 0.000 75.072 0.024 75.096 ;
    END
  END wd_in[35]
  PIN wd_in[36]
    DIRECTION INPUT ;
    USE SIGNAL ;
    SHAPE ABUTMENT ;
    PORT
      LAYER M4 ;
      RECT 0.000 75.264 0.024 75.288 ;
    END
  END wd_in[36]
  PIN wd_in[37]
    DIRECTION INPUT ;
    USE SIGNAL ;
    SHAPE ABUTMENT ;
    PORT
      LAYER M4 ;
      RECT 0.000 75.456 0.024 75.480 ;
    END
  END wd_in[37]
  PIN wd_in[38]
    DIRECTION INPUT ;
    USE SIGNAL ;
    SHAPE ABUTMENT ;
    PORT
      LAYER M4 ;
      RECT 0.000 75.648 0.024 75.672 ;
    END
  END wd_in[38]
  PIN wd_in[39]
    DIRECTION INPUT ;
    USE SIGNAL ;
    SHAPE ABUTMENT ;
    PORT
      LAYER M4 ;
      RECT 0.000 75.840 0.024 75.864 ;
    END
  END wd_in[39]
  PIN wd_in[40]
    DIRECTION INPUT ;
    USE SIGNAL ;
    SHAPE ABUTMENT ;
    PORT
      LAYER M4 ;
      RECT 0.000 76.032 0.024 76.056 ;
    END
  END wd_in[40]
  PIN wd_in[41]
    DIRECTION INPUT ;
    USE SIGNAL ;
    SHAPE ABUTMENT ;
    PORT
      LAYER M4 ;
      RECT 0.000 76.224 0.024 76.248 ;
    END
  END wd_in[41]
  PIN wd_in[42]
    DIRECTION INPUT ;
    USE SIGNAL ;
    SHAPE ABUTMENT ;
    PORT
      LAYER M4 ;
      RECT 0.000 76.416 0.024 76.440 ;
    END
  END wd_in[42]
  PIN wd_in[43]
    DIRECTION INPUT ;
    USE SIGNAL ;
    SHAPE ABUTMENT ;
    PORT
      LAYER M4 ;
      RECT 0.000 76.608 0.024 76.632 ;
    END
  END wd_in[43]
  PIN wd_in[44]
    DIRECTION INPUT ;
    USE SIGNAL ;
    SHAPE ABUTMENT ;
    PORT
      LAYER M4 ;
      RECT 0.000 76.800 0.024 76.824 ;
    END
  END wd_in[44]
  PIN wd_in[45]
    DIRECTION INPUT ;
    USE SIGNAL ;
    SHAPE ABUTMENT ;
    PORT
      LAYER M4 ;
      RECT 0.000 76.992 0.024 77.016 ;
    END
  END wd_in[45]
  PIN wd_in[46]
    DIRECTION INPUT ;
    USE SIGNAL ;
    SHAPE ABUTMENT ;
    PORT
      LAYER M4 ;
      RECT 0.000 77.184 0.024 77.208 ;
    END
  END wd_in[46]
  PIN wd_in[47]
    DIRECTION INPUT ;
    USE SIGNAL ;
    SHAPE ABUTMENT ;
    PORT
      LAYER M4 ;
      RECT 0.000 77.376 0.024 77.400 ;
    END
  END wd_in[47]
  PIN wd_in[48]
    DIRECTION INPUT ;
    USE SIGNAL ;
    SHAPE ABUTMENT ;
    PORT
      LAYER M4 ;
      RECT 0.000 77.568 0.024 77.592 ;
    END
  END wd_in[48]
  PIN wd_in[49]
    DIRECTION INPUT ;
    USE SIGNAL ;
    SHAPE ABUTMENT ;
    PORT
      LAYER M4 ;
      RECT 0.000 77.760 0.024 77.784 ;
    END
  END wd_in[49]
  PIN wd_in[50]
    DIRECTION INPUT ;
    USE SIGNAL ;
    SHAPE ABUTMENT ;
    PORT
      LAYER M4 ;
      RECT 0.000 77.952 0.024 77.976 ;
    END
  END wd_in[50]
  PIN wd_in[51]
    DIRECTION INPUT ;
    USE SIGNAL ;
    SHAPE ABUTMENT ;
    PORT
      LAYER M4 ;
      RECT 0.000 78.144 0.024 78.168 ;
    END
  END wd_in[51]
  PIN wd_in[52]
    DIRECTION INPUT ;
    USE SIGNAL ;
    SHAPE ABUTMENT ;
    PORT
      LAYER M4 ;
      RECT 0.000 78.336 0.024 78.360 ;
    END
  END wd_in[52]
  PIN wd_in[53]
    DIRECTION INPUT ;
    USE SIGNAL ;
    SHAPE ABUTMENT ;
    PORT
      LAYER M4 ;
      RECT 0.000 78.528 0.024 78.552 ;
    END
  END wd_in[53]
  PIN wd_in[54]
    DIRECTION INPUT ;
    USE SIGNAL ;
    SHAPE ABUTMENT ;
    PORT
      LAYER M4 ;
      RECT 0.000 78.720 0.024 78.744 ;
    END
  END wd_in[54]
  PIN wd_in[55]
    DIRECTION INPUT ;
    USE SIGNAL ;
    SHAPE ABUTMENT ;
    PORT
      LAYER M4 ;
      RECT 0.000 78.912 0.024 78.936 ;
    END
  END wd_in[55]
  PIN wd_in[56]
    DIRECTION INPUT ;
    USE SIGNAL ;
    SHAPE ABUTMENT ;
    PORT
      LAYER M4 ;
      RECT 0.000 79.104 0.024 79.128 ;
    END
  END wd_in[56]
  PIN wd_in[57]
    DIRECTION INPUT ;
    USE SIGNAL ;
    SHAPE ABUTMENT ;
    PORT
      LAYER M4 ;
      RECT 0.000 79.296 0.024 79.320 ;
    END
  END wd_in[57]
  PIN wd_in[58]
    DIRECTION INPUT ;
    USE SIGNAL ;
    SHAPE ABUTMENT ;
    PORT
      LAYER M4 ;
      RECT 0.000 79.488 0.024 79.512 ;
    END
  END wd_in[58]
  PIN wd_in[59]
    DIRECTION INPUT ;
    USE SIGNAL ;
    SHAPE ABUTMENT ;
    PORT
      LAYER M4 ;
      RECT 0.000 79.680 0.024 79.704 ;
    END
  END wd_in[59]
  PIN wd_in[60]
    DIRECTION INPUT ;
    USE SIGNAL ;
    SHAPE ABUTMENT ;
    PORT
      LAYER M4 ;
      RECT 0.000 79.872 0.024 79.896 ;
    END
  END wd_in[60]
  PIN wd_in[61]
    DIRECTION INPUT ;
    USE SIGNAL ;
    SHAPE ABUTMENT ;
    PORT
      LAYER M4 ;
      RECT 0.000 80.064 0.024 80.088 ;
    END
  END wd_in[61]
  PIN wd_in[62]
    DIRECTION INPUT ;
    USE SIGNAL ;
    SHAPE ABUTMENT ;
    PORT
      LAYER M4 ;
      RECT 0.000 80.256 0.024 80.280 ;
    END
  END wd_in[62]
  PIN wd_in[63]
    DIRECTION INPUT ;
    USE SIGNAL ;
    SHAPE ABUTMENT ;
    PORT
      LAYER M4 ;
      RECT 0.000 80.448 0.024 80.472 ;
    END
  END wd_in[63]
  PIN wd_in[64]
    DIRECTION INPUT ;
    USE SIGNAL ;
    SHAPE ABUTMENT ;
    PORT
      LAYER M4 ;
      RECT 0.000 80.640 0.024 80.664 ;
    END
  END wd_in[64]
  PIN wd_in[65]
    DIRECTION INPUT ;
    USE SIGNAL ;
    SHAPE ABUTMENT ;
    PORT
      LAYER M4 ;
      RECT 0.000 80.832 0.024 80.856 ;
    END
  END wd_in[65]
  PIN wd_in[66]
    DIRECTION INPUT ;
    USE SIGNAL ;
    SHAPE ABUTMENT ;
    PORT
      LAYER M4 ;
      RECT 0.000 81.024 0.024 81.048 ;
    END
  END wd_in[66]
  PIN wd_in[67]
    DIRECTION INPUT ;
    USE SIGNAL ;
    SHAPE ABUTMENT ;
    PORT
      LAYER M4 ;
      RECT 0.000 81.216 0.024 81.240 ;
    END
  END wd_in[67]
  PIN wd_in[68]
    DIRECTION INPUT ;
    USE SIGNAL ;
    SHAPE ABUTMENT ;
    PORT
      LAYER M4 ;
      RECT 0.000 81.408 0.024 81.432 ;
    END
  END wd_in[68]
  PIN wd_in[69]
    DIRECTION INPUT ;
    USE SIGNAL ;
    SHAPE ABUTMENT ;
    PORT
      LAYER M4 ;
      RECT 0.000 81.600 0.024 81.624 ;
    END
  END wd_in[69]
  PIN wd_in[70]
    DIRECTION INPUT ;
    USE SIGNAL ;
    SHAPE ABUTMENT ;
    PORT
      LAYER M4 ;
      RECT 0.000 81.792 0.024 81.816 ;
    END
  END wd_in[70]
  PIN wd_in[71]
    DIRECTION INPUT ;
    USE SIGNAL ;
    SHAPE ABUTMENT ;
    PORT
      LAYER M4 ;
      RECT 0.000 81.984 0.024 82.008 ;
    END
  END wd_in[71]
  PIN wd_in[72]
    DIRECTION INPUT ;
    USE SIGNAL ;
    SHAPE ABUTMENT ;
    PORT
      LAYER M4 ;
      RECT 0.000 82.176 0.024 82.200 ;
    END
  END wd_in[72]
  PIN wd_in[73]
    DIRECTION INPUT ;
    USE SIGNAL ;
    SHAPE ABUTMENT ;
    PORT
      LAYER M4 ;
      RECT 0.000 82.368 0.024 82.392 ;
    END
  END wd_in[73]
  PIN wd_in[74]
    DIRECTION INPUT ;
    USE SIGNAL ;
    SHAPE ABUTMENT ;
    PORT
      LAYER M4 ;
      RECT 0.000 82.560 0.024 82.584 ;
    END
  END wd_in[74]
  PIN wd_in[75]
    DIRECTION INPUT ;
    USE SIGNAL ;
    SHAPE ABUTMENT ;
    PORT
      LAYER M4 ;
      RECT 0.000 82.752 0.024 82.776 ;
    END
  END wd_in[75]
  PIN wd_in[76]
    DIRECTION INPUT ;
    USE SIGNAL ;
    SHAPE ABUTMENT ;
    PORT
      LAYER M4 ;
      RECT 0.000 82.944 0.024 82.968 ;
    END
  END wd_in[76]
  PIN wd_in[77]
    DIRECTION INPUT ;
    USE SIGNAL ;
    SHAPE ABUTMENT ;
    PORT
      LAYER M4 ;
      RECT 0.000 83.136 0.024 83.160 ;
    END
  END wd_in[77]
  PIN wd_in[78]
    DIRECTION INPUT ;
    USE SIGNAL ;
    SHAPE ABUTMENT ;
    PORT
      LAYER M4 ;
      RECT 0.000 83.328 0.024 83.352 ;
    END
  END wd_in[78]
  PIN wd_in[79]
    DIRECTION INPUT ;
    USE SIGNAL ;
    SHAPE ABUTMENT ;
    PORT
      LAYER M4 ;
      RECT 0.000 83.520 0.024 83.544 ;
    END
  END wd_in[79]
  PIN wd_in[80]
    DIRECTION INPUT ;
    USE SIGNAL ;
    SHAPE ABUTMENT ;
    PORT
      LAYER M4 ;
      RECT 0.000 83.712 0.024 83.736 ;
    END
  END wd_in[80]
  PIN wd_in[81]
    DIRECTION INPUT ;
    USE SIGNAL ;
    SHAPE ABUTMENT ;
    PORT
      LAYER M4 ;
      RECT 0.000 83.904 0.024 83.928 ;
    END
  END wd_in[81]
  PIN wd_in[82]
    DIRECTION INPUT ;
    USE SIGNAL ;
    SHAPE ABUTMENT ;
    PORT
      LAYER M4 ;
      RECT 0.000 84.096 0.024 84.120 ;
    END
  END wd_in[82]
  PIN wd_in[83]
    DIRECTION INPUT ;
    USE SIGNAL ;
    SHAPE ABUTMENT ;
    PORT
      LAYER M4 ;
      RECT 0.000 84.288 0.024 84.312 ;
    END
  END wd_in[83]
  PIN wd_in[84]
    DIRECTION INPUT ;
    USE SIGNAL ;
    SHAPE ABUTMENT ;
    PORT
      LAYER M4 ;
      RECT 0.000 84.480 0.024 84.504 ;
    END
  END wd_in[84]
  PIN wd_in[85]
    DIRECTION INPUT ;
    USE SIGNAL ;
    SHAPE ABUTMENT ;
    PORT
      LAYER M4 ;
      RECT 0.000 84.672 0.024 84.696 ;
    END
  END wd_in[85]
  PIN wd_in[86]
    DIRECTION INPUT ;
    USE SIGNAL ;
    SHAPE ABUTMENT ;
    PORT
      LAYER M4 ;
      RECT 0.000 84.864 0.024 84.888 ;
    END
  END wd_in[86]
  PIN wd_in[87]
    DIRECTION INPUT ;
    USE SIGNAL ;
    SHAPE ABUTMENT ;
    PORT
      LAYER M4 ;
      RECT 0.000 85.056 0.024 85.080 ;
    END
  END wd_in[87]
  PIN wd_in[88]
    DIRECTION INPUT ;
    USE SIGNAL ;
    SHAPE ABUTMENT ;
    PORT
      LAYER M4 ;
      RECT 0.000 85.248 0.024 85.272 ;
    END
  END wd_in[88]
  PIN wd_in[89]
    DIRECTION INPUT ;
    USE SIGNAL ;
    SHAPE ABUTMENT ;
    PORT
      LAYER M4 ;
      RECT 0.000 85.440 0.024 85.464 ;
    END
  END wd_in[89]
  PIN wd_in[90]
    DIRECTION INPUT ;
    USE SIGNAL ;
    SHAPE ABUTMENT ;
    PORT
      LAYER M4 ;
      RECT 0.000 85.632 0.024 85.656 ;
    END
  END wd_in[90]
  PIN wd_in[91]
    DIRECTION INPUT ;
    USE SIGNAL ;
    SHAPE ABUTMENT ;
    PORT
      LAYER M4 ;
      RECT 0.000 85.824 0.024 85.848 ;
    END
  END wd_in[91]
  PIN wd_in[92]
    DIRECTION INPUT ;
    USE SIGNAL ;
    SHAPE ABUTMENT ;
    PORT
      LAYER M4 ;
      RECT 0.000 86.016 0.024 86.040 ;
    END
  END wd_in[92]
  PIN wd_in[93]
    DIRECTION INPUT ;
    USE SIGNAL ;
    SHAPE ABUTMENT ;
    PORT
      LAYER M4 ;
      RECT 0.000 86.208 0.024 86.232 ;
    END
  END wd_in[93]
  PIN wd_in[94]
    DIRECTION INPUT ;
    USE SIGNAL ;
    SHAPE ABUTMENT ;
    PORT
      LAYER M4 ;
      RECT 0.000 86.400 0.024 86.424 ;
    END
  END wd_in[94]
  PIN wd_in[95]
    DIRECTION INPUT ;
    USE SIGNAL ;
    SHAPE ABUTMENT ;
    PORT
      LAYER M4 ;
      RECT 0.000 86.592 0.024 86.616 ;
    END
  END wd_in[95]
  PIN wd_in[96]
    DIRECTION INPUT ;
    USE SIGNAL ;
    SHAPE ABUTMENT ;
    PORT
      LAYER M4 ;
      RECT 0.000 86.784 0.024 86.808 ;
    END
  END wd_in[96]
  PIN wd_in[97]
    DIRECTION INPUT ;
    USE SIGNAL ;
    SHAPE ABUTMENT ;
    PORT
      LAYER M4 ;
      RECT 0.000 86.976 0.024 87.000 ;
    END
  END wd_in[97]
  PIN wd_in[98]
    DIRECTION INPUT ;
    USE SIGNAL ;
    SHAPE ABUTMENT ;
    PORT
      LAYER M4 ;
      RECT 0.000 87.168 0.024 87.192 ;
    END
  END wd_in[98]
  PIN wd_in[99]
    DIRECTION INPUT ;
    USE SIGNAL ;
    SHAPE ABUTMENT ;
    PORT
      LAYER M4 ;
      RECT 0.000 87.360 0.024 87.384 ;
    END
  END wd_in[99]
  PIN wd_in[100]
    DIRECTION INPUT ;
    USE SIGNAL ;
    SHAPE ABUTMENT ;
    PORT
      LAYER M4 ;
      RECT 0.000 87.552 0.024 87.576 ;
    END
  END wd_in[100]
  PIN wd_in[101]
    DIRECTION INPUT ;
    USE SIGNAL ;
    SHAPE ABUTMENT ;
    PORT
      LAYER M4 ;
      RECT 0.000 87.744 0.024 87.768 ;
    END
  END wd_in[101]
  PIN wd_in[102]
    DIRECTION INPUT ;
    USE SIGNAL ;
    SHAPE ABUTMENT ;
    PORT
      LAYER M4 ;
      RECT 0.000 87.936 0.024 87.960 ;
    END
  END wd_in[102]
  PIN wd_in[103]
    DIRECTION INPUT ;
    USE SIGNAL ;
    SHAPE ABUTMENT ;
    PORT
      LAYER M4 ;
      RECT 0.000 88.128 0.024 88.152 ;
    END
  END wd_in[103]
  PIN wd_in[104]
    DIRECTION INPUT ;
    USE SIGNAL ;
    SHAPE ABUTMENT ;
    PORT
      LAYER M4 ;
      RECT 0.000 88.320 0.024 88.344 ;
    END
  END wd_in[104]
  PIN wd_in[105]
    DIRECTION INPUT ;
    USE SIGNAL ;
    SHAPE ABUTMENT ;
    PORT
      LAYER M4 ;
      RECT 0.000 88.512 0.024 88.536 ;
    END
  END wd_in[105]
  PIN wd_in[106]
    DIRECTION INPUT ;
    USE SIGNAL ;
    SHAPE ABUTMENT ;
    PORT
      LAYER M4 ;
      RECT 0.000 88.704 0.024 88.728 ;
    END
  END wd_in[106]
  PIN wd_in[107]
    DIRECTION INPUT ;
    USE SIGNAL ;
    SHAPE ABUTMENT ;
    PORT
      LAYER M4 ;
      RECT 0.000 88.896 0.024 88.920 ;
    END
  END wd_in[107]
  PIN wd_in[108]
    DIRECTION INPUT ;
    USE SIGNAL ;
    SHAPE ABUTMENT ;
    PORT
      LAYER M4 ;
      RECT 0.000 89.088 0.024 89.112 ;
    END
  END wd_in[108]
  PIN wd_in[109]
    DIRECTION INPUT ;
    USE SIGNAL ;
    SHAPE ABUTMENT ;
    PORT
      LAYER M4 ;
      RECT 0.000 89.280 0.024 89.304 ;
    END
  END wd_in[109]
  PIN wd_in[110]
    DIRECTION INPUT ;
    USE SIGNAL ;
    SHAPE ABUTMENT ;
    PORT
      LAYER M4 ;
      RECT 0.000 89.472 0.024 89.496 ;
    END
  END wd_in[110]
  PIN wd_in[111]
    DIRECTION INPUT ;
    USE SIGNAL ;
    SHAPE ABUTMENT ;
    PORT
      LAYER M4 ;
      RECT 0.000 89.664 0.024 89.688 ;
    END
  END wd_in[111]
  PIN wd_in[112]
    DIRECTION INPUT ;
    USE SIGNAL ;
    SHAPE ABUTMENT ;
    PORT
      LAYER M4 ;
      RECT 0.000 89.856 0.024 89.880 ;
    END
  END wd_in[112]
  PIN wd_in[113]
    DIRECTION INPUT ;
    USE SIGNAL ;
    SHAPE ABUTMENT ;
    PORT
      LAYER M4 ;
      RECT 0.000 90.048 0.024 90.072 ;
    END
  END wd_in[113]
  PIN wd_in[114]
    DIRECTION INPUT ;
    USE SIGNAL ;
    SHAPE ABUTMENT ;
    PORT
      LAYER M4 ;
      RECT 0.000 90.240 0.024 90.264 ;
    END
  END wd_in[114]
  PIN wd_in[115]
    DIRECTION INPUT ;
    USE SIGNAL ;
    SHAPE ABUTMENT ;
    PORT
      LAYER M4 ;
      RECT 0.000 90.432 0.024 90.456 ;
    END
  END wd_in[115]
  PIN wd_in[116]
    DIRECTION INPUT ;
    USE SIGNAL ;
    SHAPE ABUTMENT ;
    PORT
      LAYER M4 ;
      RECT 0.000 90.624 0.024 90.648 ;
    END
  END wd_in[116]
  PIN wd_in[117]
    DIRECTION INPUT ;
    USE SIGNAL ;
    SHAPE ABUTMENT ;
    PORT
      LAYER M4 ;
      RECT 0.000 90.816 0.024 90.840 ;
    END
  END wd_in[117]
  PIN wd_in[118]
    DIRECTION INPUT ;
    USE SIGNAL ;
    SHAPE ABUTMENT ;
    PORT
      LAYER M4 ;
      RECT 0.000 91.008 0.024 91.032 ;
    END
  END wd_in[118]
  PIN wd_in[119]
    DIRECTION INPUT ;
    USE SIGNAL ;
    SHAPE ABUTMENT ;
    PORT
      LAYER M4 ;
      RECT 0.000 91.200 0.024 91.224 ;
    END
  END wd_in[119]
  PIN wd_in[120]
    DIRECTION INPUT ;
    USE SIGNAL ;
    SHAPE ABUTMENT ;
    PORT
      LAYER M4 ;
      RECT 0.000 91.392 0.024 91.416 ;
    END
  END wd_in[120]
  PIN wd_in[121]
    DIRECTION INPUT ;
    USE SIGNAL ;
    SHAPE ABUTMENT ;
    PORT
      LAYER M4 ;
      RECT 0.000 91.584 0.024 91.608 ;
    END
  END wd_in[121]
  PIN wd_in[122]
    DIRECTION INPUT ;
    USE SIGNAL ;
    SHAPE ABUTMENT ;
    PORT
      LAYER M4 ;
      RECT 0.000 91.776 0.024 91.800 ;
    END
  END wd_in[122]
  PIN wd_in[123]
    DIRECTION INPUT ;
    USE SIGNAL ;
    SHAPE ABUTMENT ;
    PORT
      LAYER M4 ;
      RECT 0.000 91.968 0.024 91.992 ;
    END
  END wd_in[123]
  PIN wd_in[124]
    DIRECTION INPUT ;
    USE SIGNAL ;
    SHAPE ABUTMENT ;
    PORT
      LAYER M4 ;
      RECT 0.000 92.160 0.024 92.184 ;
    END
  END wd_in[124]
  PIN wd_in[125]
    DIRECTION INPUT ;
    USE SIGNAL ;
    SHAPE ABUTMENT ;
    PORT
      LAYER M4 ;
      RECT 0.000 92.352 0.024 92.376 ;
    END
  END wd_in[125]
  PIN wd_in[126]
    DIRECTION INPUT ;
    USE SIGNAL ;
    SHAPE ABUTMENT ;
    PORT
      LAYER M4 ;
      RECT 0.000 92.544 0.024 92.568 ;
    END
  END wd_in[126]
  PIN wd_in[127]
    DIRECTION INPUT ;
    USE SIGNAL ;
    SHAPE ABUTMENT ;
    PORT
      LAYER M4 ;
      RECT 0.000 92.736 0.024 92.760 ;
    END
  END wd_in[127]
  PIN wd_in[128]
    DIRECTION INPUT ;
    USE SIGNAL ;
    SHAPE ABUTMENT ;
    PORT
      LAYER M4 ;
      RECT 0.000 92.928 0.024 92.952 ;
    END
  END wd_in[128]
  PIN wd_in[129]
    DIRECTION INPUT ;
    USE SIGNAL ;
    SHAPE ABUTMENT ;
    PORT
      LAYER M4 ;
      RECT 0.000 93.120 0.024 93.144 ;
    END
  END wd_in[129]
  PIN wd_in[130]
    DIRECTION INPUT ;
    USE SIGNAL ;
    SHAPE ABUTMENT ;
    PORT
      LAYER M4 ;
      RECT 0.000 93.312 0.024 93.336 ;
    END
  END wd_in[130]
  PIN wd_in[131]
    DIRECTION INPUT ;
    USE SIGNAL ;
    SHAPE ABUTMENT ;
    PORT
      LAYER M4 ;
      RECT 0.000 93.504 0.024 93.528 ;
    END
  END wd_in[131]
  PIN wd_in[132]
    DIRECTION INPUT ;
    USE SIGNAL ;
    SHAPE ABUTMENT ;
    PORT
      LAYER M4 ;
      RECT 0.000 93.696 0.024 93.720 ;
    END
  END wd_in[132]
  PIN wd_in[133]
    DIRECTION INPUT ;
    USE SIGNAL ;
    SHAPE ABUTMENT ;
    PORT
      LAYER M4 ;
      RECT 0.000 93.888 0.024 93.912 ;
    END
  END wd_in[133]
  PIN wd_in[134]
    DIRECTION INPUT ;
    USE SIGNAL ;
    SHAPE ABUTMENT ;
    PORT
      LAYER M4 ;
      RECT 0.000 94.080 0.024 94.104 ;
    END
  END wd_in[134]
  PIN wd_in[135]
    DIRECTION INPUT ;
    USE SIGNAL ;
    SHAPE ABUTMENT ;
    PORT
      LAYER M4 ;
      RECT 0.000 94.272 0.024 94.296 ;
    END
  END wd_in[135]
  PIN wd_in[136]
    DIRECTION INPUT ;
    USE SIGNAL ;
    SHAPE ABUTMENT ;
    PORT
      LAYER M4 ;
      RECT 0.000 94.464 0.024 94.488 ;
    END
  END wd_in[136]
  PIN wd_in[137]
    DIRECTION INPUT ;
    USE SIGNAL ;
    SHAPE ABUTMENT ;
    PORT
      LAYER M4 ;
      RECT 0.000 94.656 0.024 94.680 ;
    END
  END wd_in[137]
  PIN wd_in[138]
    DIRECTION INPUT ;
    USE SIGNAL ;
    SHAPE ABUTMENT ;
    PORT
      LAYER M4 ;
      RECT 0.000 94.848 0.024 94.872 ;
    END
  END wd_in[138]
  PIN wd_in[139]
    DIRECTION INPUT ;
    USE SIGNAL ;
    SHAPE ABUTMENT ;
    PORT
      LAYER M4 ;
      RECT 0.000 95.040 0.024 95.064 ;
    END
  END wd_in[139]
  PIN wd_in[140]
    DIRECTION INPUT ;
    USE SIGNAL ;
    SHAPE ABUTMENT ;
    PORT
      LAYER M4 ;
      RECT 0.000 95.232 0.024 95.256 ;
    END
  END wd_in[140]
  PIN wd_in[141]
    DIRECTION INPUT ;
    USE SIGNAL ;
    SHAPE ABUTMENT ;
    PORT
      LAYER M4 ;
      RECT 0.000 95.424 0.024 95.448 ;
    END
  END wd_in[141]
  PIN wd_in[142]
    DIRECTION INPUT ;
    USE SIGNAL ;
    SHAPE ABUTMENT ;
    PORT
      LAYER M4 ;
      RECT 0.000 95.616 0.024 95.640 ;
    END
  END wd_in[142]
  PIN wd_in[143]
    DIRECTION INPUT ;
    USE SIGNAL ;
    SHAPE ABUTMENT ;
    PORT
      LAYER M4 ;
      RECT 0.000 95.808 0.024 95.832 ;
    END
  END wd_in[143]
  PIN wd_in[144]
    DIRECTION INPUT ;
    USE SIGNAL ;
    SHAPE ABUTMENT ;
    PORT
      LAYER M4 ;
      RECT 0.000 96.000 0.024 96.024 ;
    END
  END wd_in[144]
  PIN wd_in[145]
    DIRECTION INPUT ;
    USE SIGNAL ;
    SHAPE ABUTMENT ;
    PORT
      LAYER M4 ;
      RECT 0.000 96.192 0.024 96.216 ;
    END
  END wd_in[145]
  PIN wd_in[146]
    DIRECTION INPUT ;
    USE SIGNAL ;
    SHAPE ABUTMENT ;
    PORT
      LAYER M4 ;
      RECT 0.000 96.384 0.024 96.408 ;
    END
  END wd_in[146]
  PIN wd_in[147]
    DIRECTION INPUT ;
    USE SIGNAL ;
    SHAPE ABUTMENT ;
    PORT
      LAYER M4 ;
      RECT 0.000 96.576 0.024 96.600 ;
    END
  END wd_in[147]
  PIN wd_in[148]
    DIRECTION INPUT ;
    USE SIGNAL ;
    SHAPE ABUTMENT ;
    PORT
      LAYER M4 ;
      RECT 0.000 96.768 0.024 96.792 ;
    END
  END wd_in[148]
  PIN wd_in[149]
    DIRECTION INPUT ;
    USE SIGNAL ;
    SHAPE ABUTMENT ;
    PORT
      LAYER M4 ;
      RECT 0.000 96.960 0.024 96.984 ;
    END
  END wd_in[149]
  PIN wd_in[150]
    DIRECTION INPUT ;
    USE SIGNAL ;
    SHAPE ABUTMENT ;
    PORT
      LAYER M4 ;
      RECT 0.000 97.152 0.024 97.176 ;
    END
  END wd_in[150]
  PIN wd_in[151]
    DIRECTION INPUT ;
    USE SIGNAL ;
    SHAPE ABUTMENT ;
    PORT
      LAYER M4 ;
      RECT 0.000 97.344 0.024 97.368 ;
    END
  END wd_in[151]
  PIN wd_in[152]
    DIRECTION INPUT ;
    USE SIGNAL ;
    SHAPE ABUTMENT ;
    PORT
      LAYER M4 ;
      RECT 0.000 97.536 0.024 97.560 ;
    END
  END wd_in[152]
  PIN wd_in[153]
    DIRECTION INPUT ;
    USE SIGNAL ;
    SHAPE ABUTMENT ;
    PORT
      LAYER M4 ;
      RECT 0.000 97.728 0.024 97.752 ;
    END
  END wd_in[153]
  PIN wd_in[154]
    DIRECTION INPUT ;
    USE SIGNAL ;
    SHAPE ABUTMENT ;
    PORT
      LAYER M4 ;
      RECT 0.000 97.920 0.024 97.944 ;
    END
  END wd_in[154]
  PIN wd_in[155]
    DIRECTION INPUT ;
    USE SIGNAL ;
    SHAPE ABUTMENT ;
    PORT
      LAYER M4 ;
      RECT 0.000 98.112 0.024 98.136 ;
    END
  END wd_in[155]
  PIN wd_in[156]
    DIRECTION INPUT ;
    USE SIGNAL ;
    SHAPE ABUTMENT ;
    PORT
      LAYER M4 ;
      RECT 0.000 98.304 0.024 98.328 ;
    END
  END wd_in[156]
  PIN wd_in[157]
    DIRECTION INPUT ;
    USE SIGNAL ;
    SHAPE ABUTMENT ;
    PORT
      LAYER M4 ;
      RECT 0.000 98.496 0.024 98.520 ;
    END
  END wd_in[157]
  PIN wd_in[158]
    DIRECTION INPUT ;
    USE SIGNAL ;
    SHAPE ABUTMENT ;
    PORT
      LAYER M4 ;
      RECT 0.000 98.688 0.024 98.712 ;
    END
  END wd_in[158]
  PIN wd_in[159]
    DIRECTION INPUT ;
    USE SIGNAL ;
    SHAPE ABUTMENT ;
    PORT
      LAYER M4 ;
      RECT 0.000 98.880 0.024 98.904 ;
    END
  END wd_in[159]
  PIN wd_in[160]
    DIRECTION INPUT ;
    USE SIGNAL ;
    SHAPE ABUTMENT ;
    PORT
      LAYER M4 ;
      RECT 0.000 99.072 0.024 99.096 ;
    END
  END wd_in[160]
  PIN wd_in[161]
    DIRECTION INPUT ;
    USE SIGNAL ;
    SHAPE ABUTMENT ;
    PORT
      LAYER M4 ;
      RECT 0.000 99.264 0.024 99.288 ;
    END
  END wd_in[161]
  PIN wd_in[162]
    DIRECTION INPUT ;
    USE SIGNAL ;
    SHAPE ABUTMENT ;
    PORT
      LAYER M4 ;
      RECT 0.000 99.456 0.024 99.480 ;
    END
  END wd_in[162]
  PIN wd_in[163]
    DIRECTION INPUT ;
    USE SIGNAL ;
    SHAPE ABUTMENT ;
    PORT
      LAYER M4 ;
      RECT 0.000 99.648 0.024 99.672 ;
    END
  END wd_in[163]
  PIN wd_in[164]
    DIRECTION INPUT ;
    USE SIGNAL ;
    SHAPE ABUTMENT ;
    PORT
      LAYER M4 ;
      RECT 114.456 0.768 114.480 0.792 ;
    END
  END wd_in[164]
  PIN wd_in[165]
    DIRECTION INPUT ;
    USE SIGNAL ;
    SHAPE ABUTMENT ;
    PORT
      LAYER M4 ;
      RECT 114.456 0.960 114.480 0.984 ;
    END
  END wd_in[165]
  PIN wd_in[166]
    DIRECTION INPUT ;
    USE SIGNAL ;
    SHAPE ABUTMENT ;
    PORT
      LAYER M4 ;
      RECT 114.456 1.152 114.480 1.176 ;
    END
  END wd_in[166]
  PIN wd_in[167]
    DIRECTION INPUT ;
    USE SIGNAL ;
    SHAPE ABUTMENT ;
    PORT
      LAYER M4 ;
      RECT 114.456 1.344 114.480 1.368 ;
    END
  END wd_in[167]
  PIN wd_in[168]
    DIRECTION INPUT ;
    USE SIGNAL ;
    SHAPE ABUTMENT ;
    PORT
      LAYER M4 ;
      RECT 114.456 1.536 114.480 1.560 ;
    END
  END wd_in[168]
  PIN wd_in[169]
    DIRECTION INPUT ;
    USE SIGNAL ;
    SHAPE ABUTMENT ;
    PORT
      LAYER M4 ;
      RECT 114.456 1.728 114.480 1.752 ;
    END
  END wd_in[169]
  PIN wd_in[170]
    DIRECTION INPUT ;
    USE SIGNAL ;
    SHAPE ABUTMENT ;
    PORT
      LAYER M4 ;
      RECT 114.456 1.920 114.480 1.944 ;
    END
  END wd_in[170]
  PIN wd_in[171]
    DIRECTION INPUT ;
    USE SIGNAL ;
    SHAPE ABUTMENT ;
    PORT
      LAYER M4 ;
      RECT 114.456 2.112 114.480 2.136 ;
    END
  END wd_in[171]
  PIN wd_in[172]
    DIRECTION INPUT ;
    USE SIGNAL ;
    SHAPE ABUTMENT ;
    PORT
      LAYER M4 ;
      RECT 114.456 2.304 114.480 2.328 ;
    END
  END wd_in[172]
  PIN wd_in[173]
    DIRECTION INPUT ;
    USE SIGNAL ;
    SHAPE ABUTMENT ;
    PORT
      LAYER M4 ;
      RECT 114.456 2.496 114.480 2.520 ;
    END
  END wd_in[173]
  PIN wd_in[174]
    DIRECTION INPUT ;
    USE SIGNAL ;
    SHAPE ABUTMENT ;
    PORT
      LAYER M4 ;
      RECT 114.456 2.688 114.480 2.712 ;
    END
  END wd_in[174]
  PIN wd_in[175]
    DIRECTION INPUT ;
    USE SIGNAL ;
    SHAPE ABUTMENT ;
    PORT
      LAYER M4 ;
      RECT 114.456 2.880 114.480 2.904 ;
    END
  END wd_in[175]
  PIN wd_in[176]
    DIRECTION INPUT ;
    USE SIGNAL ;
    SHAPE ABUTMENT ;
    PORT
      LAYER M4 ;
      RECT 114.456 3.072 114.480 3.096 ;
    END
  END wd_in[176]
  PIN wd_in[177]
    DIRECTION INPUT ;
    USE SIGNAL ;
    SHAPE ABUTMENT ;
    PORT
      LAYER M4 ;
      RECT 114.456 3.264 114.480 3.288 ;
    END
  END wd_in[177]
  PIN wd_in[178]
    DIRECTION INPUT ;
    USE SIGNAL ;
    SHAPE ABUTMENT ;
    PORT
      LAYER M4 ;
      RECT 114.456 3.456 114.480 3.480 ;
    END
  END wd_in[178]
  PIN wd_in[179]
    DIRECTION INPUT ;
    USE SIGNAL ;
    SHAPE ABUTMENT ;
    PORT
      LAYER M4 ;
      RECT 114.456 3.648 114.480 3.672 ;
    END
  END wd_in[179]
  PIN wd_in[180]
    DIRECTION INPUT ;
    USE SIGNAL ;
    SHAPE ABUTMENT ;
    PORT
      LAYER M4 ;
      RECT 114.456 3.840 114.480 3.864 ;
    END
  END wd_in[180]
  PIN wd_in[181]
    DIRECTION INPUT ;
    USE SIGNAL ;
    SHAPE ABUTMENT ;
    PORT
      LAYER M4 ;
      RECT 114.456 4.032 114.480 4.056 ;
    END
  END wd_in[181]
  PIN wd_in[182]
    DIRECTION INPUT ;
    USE SIGNAL ;
    SHAPE ABUTMENT ;
    PORT
      LAYER M4 ;
      RECT 114.456 4.224 114.480 4.248 ;
    END
  END wd_in[182]
  PIN wd_in[183]
    DIRECTION INPUT ;
    USE SIGNAL ;
    SHAPE ABUTMENT ;
    PORT
      LAYER M4 ;
      RECT 114.456 4.416 114.480 4.440 ;
    END
  END wd_in[183]
  PIN wd_in[184]
    DIRECTION INPUT ;
    USE SIGNAL ;
    SHAPE ABUTMENT ;
    PORT
      LAYER M4 ;
      RECT 114.456 4.608 114.480 4.632 ;
    END
  END wd_in[184]
  PIN wd_in[185]
    DIRECTION INPUT ;
    USE SIGNAL ;
    SHAPE ABUTMENT ;
    PORT
      LAYER M4 ;
      RECT 114.456 4.800 114.480 4.824 ;
    END
  END wd_in[185]
  PIN wd_in[186]
    DIRECTION INPUT ;
    USE SIGNAL ;
    SHAPE ABUTMENT ;
    PORT
      LAYER M4 ;
      RECT 114.456 4.992 114.480 5.016 ;
    END
  END wd_in[186]
  PIN wd_in[187]
    DIRECTION INPUT ;
    USE SIGNAL ;
    SHAPE ABUTMENT ;
    PORT
      LAYER M4 ;
      RECT 114.456 5.184 114.480 5.208 ;
    END
  END wd_in[187]
  PIN wd_in[188]
    DIRECTION INPUT ;
    USE SIGNAL ;
    SHAPE ABUTMENT ;
    PORT
      LAYER M4 ;
      RECT 114.456 5.376 114.480 5.400 ;
    END
  END wd_in[188]
  PIN wd_in[189]
    DIRECTION INPUT ;
    USE SIGNAL ;
    SHAPE ABUTMENT ;
    PORT
      LAYER M4 ;
      RECT 114.456 5.568 114.480 5.592 ;
    END
  END wd_in[189]
  PIN wd_in[190]
    DIRECTION INPUT ;
    USE SIGNAL ;
    SHAPE ABUTMENT ;
    PORT
      LAYER M4 ;
      RECT 114.456 5.760 114.480 5.784 ;
    END
  END wd_in[190]
  PIN wd_in[191]
    DIRECTION INPUT ;
    USE SIGNAL ;
    SHAPE ABUTMENT ;
    PORT
      LAYER M4 ;
      RECT 114.456 5.952 114.480 5.976 ;
    END
  END wd_in[191]
  PIN wd_in[192]
    DIRECTION INPUT ;
    USE SIGNAL ;
    SHAPE ABUTMENT ;
    PORT
      LAYER M4 ;
      RECT 114.456 6.144 114.480 6.168 ;
    END
  END wd_in[192]
  PIN wd_in[193]
    DIRECTION INPUT ;
    USE SIGNAL ;
    SHAPE ABUTMENT ;
    PORT
      LAYER M4 ;
      RECT 114.456 6.336 114.480 6.360 ;
    END
  END wd_in[193]
  PIN wd_in[194]
    DIRECTION INPUT ;
    USE SIGNAL ;
    SHAPE ABUTMENT ;
    PORT
      LAYER M4 ;
      RECT 114.456 6.528 114.480 6.552 ;
    END
  END wd_in[194]
  PIN wd_in[195]
    DIRECTION INPUT ;
    USE SIGNAL ;
    SHAPE ABUTMENT ;
    PORT
      LAYER M4 ;
      RECT 114.456 6.720 114.480 6.744 ;
    END
  END wd_in[195]
  PIN wd_in[196]
    DIRECTION INPUT ;
    USE SIGNAL ;
    SHAPE ABUTMENT ;
    PORT
      LAYER M4 ;
      RECT 114.456 6.912 114.480 6.936 ;
    END
  END wd_in[196]
  PIN wd_in[197]
    DIRECTION INPUT ;
    USE SIGNAL ;
    SHAPE ABUTMENT ;
    PORT
      LAYER M4 ;
      RECT 114.456 7.104 114.480 7.128 ;
    END
  END wd_in[197]
  PIN wd_in[198]
    DIRECTION INPUT ;
    USE SIGNAL ;
    SHAPE ABUTMENT ;
    PORT
      LAYER M4 ;
      RECT 114.456 7.296 114.480 7.320 ;
    END
  END wd_in[198]
  PIN wd_in[199]
    DIRECTION INPUT ;
    USE SIGNAL ;
    SHAPE ABUTMENT ;
    PORT
      LAYER M4 ;
      RECT 114.456 7.488 114.480 7.512 ;
    END
  END wd_in[199]
  PIN wd_in[200]
    DIRECTION INPUT ;
    USE SIGNAL ;
    SHAPE ABUTMENT ;
    PORT
      LAYER M4 ;
      RECT 114.456 7.680 114.480 7.704 ;
    END
  END wd_in[200]
  PIN wd_in[201]
    DIRECTION INPUT ;
    USE SIGNAL ;
    SHAPE ABUTMENT ;
    PORT
      LAYER M4 ;
      RECT 114.456 7.872 114.480 7.896 ;
    END
  END wd_in[201]
  PIN wd_in[202]
    DIRECTION INPUT ;
    USE SIGNAL ;
    SHAPE ABUTMENT ;
    PORT
      LAYER M4 ;
      RECT 114.456 8.064 114.480 8.088 ;
    END
  END wd_in[202]
  PIN wd_in[203]
    DIRECTION INPUT ;
    USE SIGNAL ;
    SHAPE ABUTMENT ;
    PORT
      LAYER M4 ;
      RECT 114.456 8.256 114.480 8.280 ;
    END
  END wd_in[203]
  PIN wd_in[204]
    DIRECTION INPUT ;
    USE SIGNAL ;
    SHAPE ABUTMENT ;
    PORT
      LAYER M4 ;
      RECT 114.456 8.448 114.480 8.472 ;
    END
  END wd_in[204]
  PIN wd_in[205]
    DIRECTION INPUT ;
    USE SIGNAL ;
    SHAPE ABUTMENT ;
    PORT
      LAYER M4 ;
      RECT 114.456 8.640 114.480 8.664 ;
    END
  END wd_in[205]
  PIN wd_in[206]
    DIRECTION INPUT ;
    USE SIGNAL ;
    SHAPE ABUTMENT ;
    PORT
      LAYER M4 ;
      RECT 114.456 8.832 114.480 8.856 ;
    END
  END wd_in[206]
  PIN wd_in[207]
    DIRECTION INPUT ;
    USE SIGNAL ;
    SHAPE ABUTMENT ;
    PORT
      LAYER M4 ;
      RECT 114.456 9.024 114.480 9.048 ;
    END
  END wd_in[207]
  PIN wd_in[208]
    DIRECTION INPUT ;
    USE SIGNAL ;
    SHAPE ABUTMENT ;
    PORT
      LAYER M4 ;
      RECT 114.456 9.216 114.480 9.240 ;
    END
  END wd_in[208]
  PIN wd_in[209]
    DIRECTION INPUT ;
    USE SIGNAL ;
    SHAPE ABUTMENT ;
    PORT
      LAYER M4 ;
      RECT 114.456 9.408 114.480 9.432 ;
    END
  END wd_in[209]
  PIN wd_in[210]
    DIRECTION INPUT ;
    USE SIGNAL ;
    SHAPE ABUTMENT ;
    PORT
      LAYER M4 ;
      RECT 114.456 9.600 114.480 9.624 ;
    END
  END wd_in[210]
  PIN wd_in[211]
    DIRECTION INPUT ;
    USE SIGNAL ;
    SHAPE ABUTMENT ;
    PORT
      LAYER M4 ;
      RECT 114.456 9.792 114.480 9.816 ;
    END
  END wd_in[211]
  PIN wd_in[212]
    DIRECTION INPUT ;
    USE SIGNAL ;
    SHAPE ABUTMENT ;
    PORT
      LAYER M4 ;
      RECT 114.456 9.984 114.480 10.008 ;
    END
  END wd_in[212]
  PIN wd_in[213]
    DIRECTION INPUT ;
    USE SIGNAL ;
    SHAPE ABUTMENT ;
    PORT
      LAYER M4 ;
      RECT 114.456 10.176 114.480 10.200 ;
    END
  END wd_in[213]
  PIN wd_in[214]
    DIRECTION INPUT ;
    USE SIGNAL ;
    SHAPE ABUTMENT ;
    PORT
      LAYER M4 ;
      RECT 114.456 10.368 114.480 10.392 ;
    END
  END wd_in[214]
  PIN wd_in[215]
    DIRECTION INPUT ;
    USE SIGNAL ;
    SHAPE ABUTMENT ;
    PORT
      LAYER M4 ;
      RECT 114.456 10.560 114.480 10.584 ;
    END
  END wd_in[215]
  PIN wd_in[216]
    DIRECTION INPUT ;
    USE SIGNAL ;
    SHAPE ABUTMENT ;
    PORT
      LAYER M4 ;
      RECT 114.456 10.752 114.480 10.776 ;
    END
  END wd_in[216]
  PIN wd_in[217]
    DIRECTION INPUT ;
    USE SIGNAL ;
    SHAPE ABUTMENT ;
    PORT
      LAYER M4 ;
      RECT 114.456 10.944 114.480 10.968 ;
    END
  END wd_in[217]
  PIN wd_in[218]
    DIRECTION INPUT ;
    USE SIGNAL ;
    SHAPE ABUTMENT ;
    PORT
      LAYER M4 ;
      RECT 114.456 11.136 114.480 11.160 ;
    END
  END wd_in[218]
  PIN wd_in[219]
    DIRECTION INPUT ;
    USE SIGNAL ;
    SHAPE ABUTMENT ;
    PORT
      LAYER M4 ;
      RECT 114.456 11.328 114.480 11.352 ;
    END
  END wd_in[219]
  PIN wd_in[220]
    DIRECTION INPUT ;
    USE SIGNAL ;
    SHAPE ABUTMENT ;
    PORT
      LAYER M4 ;
      RECT 114.456 11.520 114.480 11.544 ;
    END
  END wd_in[220]
  PIN wd_in[221]
    DIRECTION INPUT ;
    USE SIGNAL ;
    SHAPE ABUTMENT ;
    PORT
      LAYER M4 ;
      RECT 114.456 11.712 114.480 11.736 ;
    END
  END wd_in[221]
  PIN wd_in[222]
    DIRECTION INPUT ;
    USE SIGNAL ;
    SHAPE ABUTMENT ;
    PORT
      LAYER M4 ;
      RECT 114.456 11.904 114.480 11.928 ;
    END
  END wd_in[222]
  PIN wd_in[223]
    DIRECTION INPUT ;
    USE SIGNAL ;
    SHAPE ABUTMENT ;
    PORT
      LAYER M4 ;
      RECT 114.456 12.096 114.480 12.120 ;
    END
  END wd_in[223]
  PIN wd_in[224]
    DIRECTION INPUT ;
    USE SIGNAL ;
    SHAPE ABUTMENT ;
    PORT
      LAYER M4 ;
      RECT 114.456 12.288 114.480 12.312 ;
    END
  END wd_in[224]
  PIN wd_in[225]
    DIRECTION INPUT ;
    USE SIGNAL ;
    SHAPE ABUTMENT ;
    PORT
      LAYER M4 ;
      RECT 114.456 12.480 114.480 12.504 ;
    END
  END wd_in[225]
  PIN wd_in[226]
    DIRECTION INPUT ;
    USE SIGNAL ;
    SHAPE ABUTMENT ;
    PORT
      LAYER M4 ;
      RECT 114.456 12.672 114.480 12.696 ;
    END
  END wd_in[226]
  PIN wd_in[227]
    DIRECTION INPUT ;
    USE SIGNAL ;
    SHAPE ABUTMENT ;
    PORT
      LAYER M4 ;
      RECT 114.456 12.864 114.480 12.888 ;
    END
  END wd_in[227]
  PIN wd_in[228]
    DIRECTION INPUT ;
    USE SIGNAL ;
    SHAPE ABUTMENT ;
    PORT
      LAYER M4 ;
      RECT 114.456 13.056 114.480 13.080 ;
    END
  END wd_in[228]
  PIN wd_in[229]
    DIRECTION INPUT ;
    USE SIGNAL ;
    SHAPE ABUTMENT ;
    PORT
      LAYER M4 ;
      RECT 114.456 13.248 114.480 13.272 ;
    END
  END wd_in[229]
  PIN wd_in[230]
    DIRECTION INPUT ;
    USE SIGNAL ;
    SHAPE ABUTMENT ;
    PORT
      LAYER M4 ;
      RECT 114.456 13.440 114.480 13.464 ;
    END
  END wd_in[230]
  PIN wd_in[231]
    DIRECTION INPUT ;
    USE SIGNAL ;
    SHAPE ABUTMENT ;
    PORT
      LAYER M4 ;
      RECT 114.456 13.632 114.480 13.656 ;
    END
  END wd_in[231]
  PIN wd_in[232]
    DIRECTION INPUT ;
    USE SIGNAL ;
    SHAPE ABUTMENT ;
    PORT
      LAYER M4 ;
      RECT 114.456 13.824 114.480 13.848 ;
    END
  END wd_in[232]
  PIN wd_in[233]
    DIRECTION INPUT ;
    USE SIGNAL ;
    SHAPE ABUTMENT ;
    PORT
      LAYER M4 ;
      RECT 114.456 14.016 114.480 14.040 ;
    END
  END wd_in[233]
  PIN wd_in[234]
    DIRECTION INPUT ;
    USE SIGNAL ;
    SHAPE ABUTMENT ;
    PORT
      LAYER M4 ;
      RECT 114.456 14.208 114.480 14.232 ;
    END
  END wd_in[234]
  PIN wd_in[235]
    DIRECTION INPUT ;
    USE SIGNAL ;
    SHAPE ABUTMENT ;
    PORT
      LAYER M4 ;
      RECT 114.456 14.400 114.480 14.424 ;
    END
  END wd_in[235]
  PIN wd_in[236]
    DIRECTION INPUT ;
    USE SIGNAL ;
    SHAPE ABUTMENT ;
    PORT
      LAYER M4 ;
      RECT 114.456 14.592 114.480 14.616 ;
    END
  END wd_in[236]
  PIN wd_in[237]
    DIRECTION INPUT ;
    USE SIGNAL ;
    SHAPE ABUTMENT ;
    PORT
      LAYER M4 ;
      RECT 114.456 14.784 114.480 14.808 ;
    END
  END wd_in[237]
  PIN wd_in[238]
    DIRECTION INPUT ;
    USE SIGNAL ;
    SHAPE ABUTMENT ;
    PORT
      LAYER M4 ;
      RECT 114.456 14.976 114.480 15.000 ;
    END
  END wd_in[238]
  PIN wd_in[239]
    DIRECTION INPUT ;
    USE SIGNAL ;
    SHAPE ABUTMENT ;
    PORT
      LAYER M4 ;
      RECT 114.456 15.168 114.480 15.192 ;
    END
  END wd_in[239]
  PIN wd_in[240]
    DIRECTION INPUT ;
    USE SIGNAL ;
    SHAPE ABUTMENT ;
    PORT
      LAYER M4 ;
      RECT 114.456 15.360 114.480 15.384 ;
    END
  END wd_in[240]
  PIN wd_in[241]
    DIRECTION INPUT ;
    USE SIGNAL ;
    SHAPE ABUTMENT ;
    PORT
      LAYER M4 ;
      RECT 114.456 15.552 114.480 15.576 ;
    END
  END wd_in[241]
  PIN wd_in[242]
    DIRECTION INPUT ;
    USE SIGNAL ;
    SHAPE ABUTMENT ;
    PORT
      LAYER M4 ;
      RECT 114.456 15.744 114.480 15.768 ;
    END
  END wd_in[242]
  PIN wd_in[243]
    DIRECTION INPUT ;
    USE SIGNAL ;
    SHAPE ABUTMENT ;
    PORT
      LAYER M4 ;
      RECT 114.456 15.936 114.480 15.960 ;
    END
  END wd_in[243]
  PIN wd_in[244]
    DIRECTION INPUT ;
    USE SIGNAL ;
    SHAPE ABUTMENT ;
    PORT
      LAYER M4 ;
      RECT 114.456 16.128 114.480 16.152 ;
    END
  END wd_in[244]
  PIN wd_in[245]
    DIRECTION INPUT ;
    USE SIGNAL ;
    SHAPE ABUTMENT ;
    PORT
      LAYER M4 ;
      RECT 114.456 16.320 114.480 16.344 ;
    END
  END wd_in[245]
  PIN wd_in[246]
    DIRECTION INPUT ;
    USE SIGNAL ;
    SHAPE ABUTMENT ;
    PORT
      LAYER M4 ;
      RECT 114.456 16.512 114.480 16.536 ;
    END
  END wd_in[246]
  PIN wd_in[247]
    DIRECTION INPUT ;
    USE SIGNAL ;
    SHAPE ABUTMENT ;
    PORT
      LAYER M4 ;
      RECT 114.456 16.704 114.480 16.728 ;
    END
  END wd_in[247]
  PIN wd_in[248]
    DIRECTION INPUT ;
    USE SIGNAL ;
    SHAPE ABUTMENT ;
    PORT
      LAYER M4 ;
      RECT 114.456 16.896 114.480 16.920 ;
    END
  END wd_in[248]
  PIN wd_in[249]
    DIRECTION INPUT ;
    USE SIGNAL ;
    SHAPE ABUTMENT ;
    PORT
      LAYER M4 ;
      RECT 114.456 17.088 114.480 17.112 ;
    END
  END wd_in[249]
  PIN wd_in[250]
    DIRECTION INPUT ;
    USE SIGNAL ;
    SHAPE ABUTMENT ;
    PORT
      LAYER M4 ;
      RECT 114.456 17.280 114.480 17.304 ;
    END
  END wd_in[250]
  PIN wd_in[251]
    DIRECTION INPUT ;
    USE SIGNAL ;
    SHAPE ABUTMENT ;
    PORT
      LAYER M4 ;
      RECT 114.456 17.472 114.480 17.496 ;
    END
  END wd_in[251]
  PIN wd_in[252]
    DIRECTION INPUT ;
    USE SIGNAL ;
    SHAPE ABUTMENT ;
    PORT
      LAYER M4 ;
      RECT 114.456 17.664 114.480 17.688 ;
    END
  END wd_in[252]
  PIN wd_in[253]
    DIRECTION INPUT ;
    USE SIGNAL ;
    SHAPE ABUTMENT ;
    PORT
      LAYER M4 ;
      RECT 114.456 17.856 114.480 17.880 ;
    END
  END wd_in[253]
  PIN wd_in[254]
    DIRECTION INPUT ;
    USE SIGNAL ;
    SHAPE ABUTMENT ;
    PORT
      LAYER M4 ;
      RECT 114.456 18.048 114.480 18.072 ;
    END
  END wd_in[254]
  PIN wd_in[255]
    DIRECTION INPUT ;
    USE SIGNAL ;
    SHAPE ABUTMENT ;
    PORT
      LAYER M4 ;
      RECT 114.456 18.240 114.480 18.264 ;
    END
  END wd_in[255]
  PIN wd_in[256]
    DIRECTION INPUT ;
    USE SIGNAL ;
    SHAPE ABUTMENT ;
    PORT
      LAYER M4 ;
      RECT 114.456 18.432 114.480 18.456 ;
    END
  END wd_in[256]
  PIN wd_in[257]
    DIRECTION INPUT ;
    USE SIGNAL ;
    SHAPE ABUTMENT ;
    PORT
      LAYER M4 ;
      RECT 114.456 18.624 114.480 18.648 ;
    END
  END wd_in[257]
  PIN wd_in[258]
    DIRECTION INPUT ;
    USE SIGNAL ;
    SHAPE ABUTMENT ;
    PORT
      LAYER M4 ;
      RECT 114.456 18.816 114.480 18.840 ;
    END
  END wd_in[258]
  PIN wd_in[259]
    DIRECTION INPUT ;
    USE SIGNAL ;
    SHAPE ABUTMENT ;
    PORT
      LAYER M4 ;
      RECT 114.456 19.008 114.480 19.032 ;
    END
  END wd_in[259]
  PIN wd_in[260]
    DIRECTION INPUT ;
    USE SIGNAL ;
    SHAPE ABUTMENT ;
    PORT
      LAYER M4 ;
      RECT 114.456 19.200 114.480 19.224 ;
    END
  END wd_in[260]
  PIN wd_in[261]
    DIRECTION INPUT ;
    USE SIGNAL ;
    SHAPE ABUTMENT ;
    PORT
      LAYER M4 ;
      RECT 114.456 19.392 114.480 19.416 ;
    END
  END wd_in[261]
  PIN wd_in[262]
    DIRECTION INPUT ;
    USE SIGNAL ;
    SHAPE ABUTMENT ;
    PORT
      LAYER M4 ;
      RECT 114.456 19.584 114.480 19.608 ;
    END
  END wd_in[262]
  PIN wd_in[263]
    DIRECTION INPUT ;
    USE SIGNAL ;
    SHAPE ABUTMENT ;
    PORT
      LAYER M4 ;
      RECT 114.456 19.776 114.480 19.800 ;
    END
  END wd_in[263]
  PIN wd_in[264]
    DIRECTION INPUT ;
    USE SIGNAL ;
    SHAPE ABUTMENT ;
    PORT
      LAYER M4 ;
      RECT 114.456 19.968 114.480 19.992 ;
    END
  END wd_in[264]
  PIN wd_in[265]
    DIRECTION INPUT ;
    USE SIGNAL ;
    SHAPE ABUTMENT ;
    PORT
      LAYER M4 ;
      RECT 114.456 20.160 114.480 20.184 ;
    END
  END wd_in[265]
  PIN wd_in[266]
    DIRECTION INPUT ;
    USE SIGNAL ;
    SHAPE ABUTMENT ;
    PORT
      LAYER M4 ;
      RECT 114.456 20.352 114.480 20.376 ;
    END
  END wd_in[266]
  PIN wd_in[267]
    DIRECTION INPUT ;
    USE SIGNAL ;
    SHAPE ABUTMENT ;
    PORT
      LAYER M4 ;
      RECT 114.456 20.544 114.480 20.568 ;
    END
  END wd_in[267]
  PIN wd_in[268]
    DIRECTION INPUT ;
    USE SIGNAL ;
    SHAPE ABUTMENT ;
    PORT
      LAYER M4 ;
      RECT 114.456 20.736 114.480 20.760 ;
    END
  END wd_in[268]
  PIN wd_in[269]
    DIRECTION INPUT ;
    USE SIGNAL ;
    SHAPE ABUTMENT ;
    PORT
      LAYER M4 ;
      RECT 114.456 20.928 114.480 20.952 ;
    END
  END wd_in[269]
  PIN wd_in[270]
    DIRECTION INPUT ;
    USE SIGNAL ;
    SHAPE ABUTMENT ;
    PORT
      LAYER M4 ;
      RECT 114.456 21.120 114.480 21.144 ;
    END
  END wd_in[270]
  PIN wd_in[271]
    DIRECTION INPUT ;
    USE SIGNAL ;
    SHAPE ABUTMENT ;
    PORT
      LAYER M4 ;
      RECT 114.456 21.312 114.480 21.336 ;
    END
  END wd_in[271]
  PIN wd_in[272]
    DIRECTION INPUT ;
    USE SIGNAL ;
    SHAPE ABUTMENT ;
    PORT
      LAYER M4 ;
      RECT 114.456 21.504 114.480 21.528 ;
    END
  END wd_in[272]
  PIN wd_in[273]
    DIRECTION INPUT ;
    USE SIGNAL ;
    SHAPE ABUTMENT ;
    PORT
      LAYER M4 ;
      RECT 114.456 21.696 114.480 21.720 ;
    END
  END wd_in[273]
  PIN wd_in[274]
    DIRECTION INPUT ;
    USE SIGNAL ;
    SHAPE ABUTMENT ;
    PORT
      LAYER M4 ;
      RECT 114.456 21.888 114.480 21.912 ;
    END
  END wd_in[274]
  PIN wd_in[275]
    DIRECTION INPUT ;
    USE SIGNAL ;
    SHAPE ABUTMENT ;
    PORT
      LAYER M4 ;
      RECT 114.456 22.080 114.480 22.104 ;
    END
  END wd_in[275]
  PIN wd_in[276]
    DIRECTION INPUT ;
    USE SIGNAL ;
    SHAPE ABUTMENT ;
    PORT
      LAYER M4 ;
      RECT 114.456 22.272 114.480 22.296 ;
    END
  END wd_in[276]
  PIN wd_in[277]
    DIRECTION INPUT ;
    USE SIGNAL ;
    SHAPE ABUTMENT ;
    PORT
      LAYER M4 ;
      RECT 114.456 22.464 114.480 22.488 ;
    END
  END wd_in[277]
  PIN wd_in[278]
    DIRECTION INPUT ;
    USE SIGNAL ;
    SHAPE ABUTMENT ;
    PORT
      LAYER M4 ;
      RECT 114.456 22.656 114.480 22.680 ;
    END
  END wd_in[278]
  PIN wd_in[279]
    DIRECTION INPUT ;
    USE SIGNAL ;
    SHAPE ABUTMENT ;
    PORT
      LAYER M4 ;
      RECT 114.456 22.848 114.480 22.872 ;
    END
  END wd_in[279]
  PIN wd_in[280]
    DIRECTION INPUT ;
    USE SIGNAL ;
    SHAPE ABUTMENT ;
    PORT
      LAYER M4 ;
      RECT 114.456 23.040 114.480 23.064 ;
    END
  END wd_in[280]
  PIN wd_in[281]
    DIRECTION INPUT ;
    USE SIGNAL ;
    SHAPE ABUTMENT ;
    PORT
      LAYER M4 ;
      RECT 114.456 23.232 114.480 23.256 ;
    END
  END wd_in[281]
  PIN wd_in[282]
    DIRECTION INPUT ;
    USE SIGNAL ;
    SHAPE ABUTMENT ;
    PORT
      LAYER M4 ;
      RECT 114.456 23.424 114.480 23.448 ;
    END
  END wd_in[282]
  PIN wd_in[283]
    DIRECTION INPUT ;
    USE SIGNAL ;
    SHAPE ABUTMENT ;
    PORT
      LAYER M4 ;
      RECT 114.456 23.616 114.480 23.640 ;
    END
  END wd_in[283]
  PIN wd_in[284]
    DIRECTION INPUT ;
    USE SIGNAL ;
    SHAPE ABUTMENT ;
    PORT
      LAYER M4 ;
      RECT 114.456 23.808 114.480 23.832 ;
    END
  END wd_in[284]
  PIN wd_in[285]
    DIRECTION INPUT ;
    USE SIGNAL ;
    SHAPE ABUTMENT ;
    PORT
      LAYER M4 ;
      RECT 114.456 24.000 114.480 24.024 ;
    END
  END wd_in[285]
  PIN wd_in[286]
    DIRECTION INPUT ;
    USE SIGNAL ;
    SHAPE ABUTMENT ;
    PORT
      LAYER M4 ;
      RECT 114.456 24.192 114.480 24.216 ;
    END
  END wd_in[286]
  PIN wd_in[287]
    DIRECTION INPUT ;
    USE SIGNAL ;
    SHAPE ABUTMENT ;
    PORT
      LAYER M4 ;
      RECT 114.456 24.384 114.480 24.408 ;
    END
  END wd_in[287]
  PIN wd_in[288]
    DIRECTION INPUT ;
    USE SIGNAL ;
    SHAPE ABUTMENT ;
    PORT
      LAYER M4 ;
      RECT 114.456 24.576 114.480 24.600 ;
    END
  END wd_in[288]
  PIN wd_in[289]
    DIRECTION INPUT ;
    USE SIGNAL ;
    SHAPE ABUTMENT ;
    PORT
      LAYER M4 ;
      RECT 114.456 24.768 114.480 24.792 ;
    END
  END wd_in[289]
  PIN wd_in[290]
    DIRECTION INPUT ;
    USE SIGNAL ;
    SHAPE ABUTMENT ;
    PORT
      LAYER M4 ;
      RECT 114.456 24.960 114.480 24.984 ;
    END
  END wd_in[290]
  PIN wd_in[291]
    DIRECTION INPUT ;
    USE SIGNAL ;
    SHAPE ABUTMENT ;
    PORT
      LAYER M4 ;
      RECT 114.456 25.152 114.480 25.176 ;
    END
  END wd_in[291]
  PIN wd_in[292]
    DIRECTION INPUT ;
    USE SIGNAL ;
    SHAPE ABUTMENT ;
    PORT
      LAYER M4 ;
      RECT 114.456 25.344 114.480 25.368 ;
    END
  END wd_in[292]
  PIN wd_in[293]
    DIRECTION INPUT ;
    USE SIGNAL ;
    SHAPE ABUTMENT ;
    PORT
      LAYER M4 ;
      RECT 114.456 25.536 114.480 25.560 ;
    END
  END wd_in[293]
  PIN wd_in[294]
    DIRECTION INPUT ;
    USE SIGNAL ;
    SHAPE ABUTMENT ;
    PORT
      LAYER M4 ;
      RECT 114.456 25.728 114.480 25.752 ;
    END
  END wd_in[294]
  PIN wd_in[295]
    DIRECTION INPUT ;
    USE SIGNAL ;
    SHAPE ABUTMENT ;
    PORT
      LAYER M4 ;
      RECT 114.456 25.920 114.480 25.944 ;
    END
  END wd_in[295]
  PIN wd_in[296]
    DIRECTION INPUT ;
    USE SIGNAL ;
    SHAPE ABUTMENT ;
    PORT
      LAYER M4 ;
      RECT 114.456 26.112 114.480 26.136 ;
    END
  END wd_in[296]
  PIN wd_in[297]
    DIRECTION INPUT ;
    USE SIGNAL ;
    SHAPE ABUTMENT ;
    PORT
      LAYER M4 ;
      RECT 114.456 26.304 114.480 26.328 ;
    END
  END wd_in[297]
  PIN wd_in[298]
    DIRECTION INPUT ;
    USE SIGNAL ;
    SHAPE ABUTMENT ;
    PORT
      LAYER M4 ;
      RECT 114.456 26.496 114.480 26.520 ;
    END
  END wd_in[298]
  PIN wd_in[299]
    DIRECTION INPUT ;
    USE SIGNAL ;
    SHAPE ABUTMENT ;
    PORT
      LAYER M4 ;
      RECT 114.456 26.688 114.480 26.712 ;
    END
  END wd_in[299]
  PIN wd_in[300]
    DIRECTION INPUT ;
    USE SIGNAL ;
    SHAPE ABUTMENT ;
    PORT
      LAYER M4 ;
      RECT 114.456 26.880 114.480 26.904 ;
    END
  END wd_in[300]
  PIN wd_in[301]
    DIRECTION INPUT ;
    USE SIGNAL ;
    SHAPE ABUTMENT ;
    PORT
      LAYER M4 ;
      RECT 114.456 27.072 114.480 27.096 ;
    END
  END wd_in[301]
  PIN wd_in[302]
    DIRECTION INPUT ;
    USE SIGNAL ;
    SHAPE ABUTMENT ;
    PORT
      LAYER M4 ;
      RECT 114.456 27.264 114.480 27.288 ;
    END
  END wd_in[302]
  PIN wd_in[303]
    DIRECTION INPUT ;
    USE SIGNAL ;
    SHAPE ABUTMENT ;
    PORT
      LAYER M4 ;
      RECT 114.456 27.456 114.480 27.480 ;
    END
  END wd_in[303]
  PIN wd_in[304]
    DIRECTION INPUT ;
    USE SIGNAL ;
    SHAPE ABUTMENT ;
    PORT
      LAYER M4 ;
      RECT 114.456 27.648 114.480 27.672 ;
    END
  END wd_in[304]
  PIN wd_in[305]
    DIRECTION INPUT ;
    USE SIGNAL ;
    SHAPE ABUTMENT ;
    PORT
      LAYER M4 ;
      RECT 114.456 27.840 114.480 27.864 ;
    END
  END wd_in[305]
  PIN wd_in[306]
    DIRECTION INPUT ;
    USE SIGNAL ;
    SHAPE ABUTMENT ;
    PORT
      LAYER M4 ;
      RECT 114.456 28.032 114.480 28.056 ;
    END
  END wd_in[306]
  PIN wd_in[307]
    DIRECTION INPUT ;
    USE SIGNAL ;
    SHAPE ABUTMENT ;
    PORT
      LAYER M4 ;
      RECT 114.456 28.224 114.480 28.248 ;
    END
  END wd_in[307]
  PIN wd_in[308]
    DIRECTION INPUT ;
    USE SIGNAL ;
    SHAPE ABUTMENT ;
    PORT
      LAYER M4 ;
      RECT 114.456 28.416 114.480 28.440 ;
    END
  END wd_in[308]
  PIN wd_in[309]
    DIRECTION INPUT ;
    USE SIGNAL ;
    SHAPE ABUTMENT ;
    PORT
      LAYER M4 ;
      RECT 114.456 28.608 114.480 28.632 ;
    END
  END wd_in[309]
  PIN wd_in[310]
    DIRECTION INPUT ;
    USE SIGNAL ;
    SHAPE ABUTMENT ;
    PORT
      LAYER M4 ;
      RECT 114.456 28.800 114.480 28.824 ;
    END
  END wd_in[310]
  PIN wd_in[311]
    DIRECTION INPUT ;
    USE SIGNAL ;
    SHAPE ABUTMENT ;
    PORT
      LAYER M4 ;
      RECT 114.456 28.992 114.480 29.016 ;
    END
  END wd_in[311]
  PIN wd_in[312]
    DIRECTION INPUT ;
    USE SIGNAL ;
    SHAPE ABUTMENT ;
    PORT
      LAYER M4 ;
      RECT 114.456 29.184 114.480 29.208 ;
    END
  END wd_in[312]
  PIN wd_in[313]
    DIRECTION INPUT ;
    USE SIGNAL ;
    SHAPE ABUTMENT ;
    PORT
      LAYER M4 ;
      RECT 114.456 29.376 114.480 29.400 ;
    END
  END wd_in[313]
  PIN wd_in[314]
    DIRECTION INPUT ;
    USE SIGNAL ;
    SHAPE ABUTMENT ;
    PORT
      LAYER M4 ;
      RECT 114.456 29.568 114.480 29.592 ;
    END
  END wd_in[314]
  PIN wd_in[315]
    DIRECTION INPUT ;
    USE SIGNAL ;
    SHAPE ABUTMENT ;
    PORT
      LAYER M4 ;
      RECT 114.456 29.760 114.480 29.784 ;
    END
  END wd_in[315]
  PIN wd_in[316]
    DIRECTION INPUT ;
    USE SIGNAL ;
    SHAPE ABUTMENT ;
    PORT
      LAYER M4 ;
      RECT 114.456 29.952 114.480 29.976 ;
    END
  END wd_in[316]
  PIN wd_in[317]
    DIRECTION INPUT ;
    USE SIGNAL ;
    SHAPE ABUTMENT ;
    PORT
      LAYER M4 ;
      RECT 114.456 30.144 114.480 30.168 ;
    END
  END wd_in[317]
  PIN wd_in[318]
    DIRECTION INPUT ;
    USE SIGNAL ;
    SHAPE ABUTMENT ;
    PORT
      LAYER M4 ;
      RECT 114.456 30.336 114.480 30.360 ;
    END
  END wd_in[318]
  PIN wd_in[319]
    DIRECTION INPUT ;
    USE SIGNAL ;
    SHAPE ABUTMENT ;
    PORT
      LAYER M4 ;
      RECT 114.456 30.528 114.480 30.552 ;
    END
  END wd_in[319]
  PIN wd_in[320]
    DIRECTION INPUT ;
    USE SIGNAL ;
    SHAPE ABUTMENT ;
    PORT
      LAYER M4 ;
      RECT 114.456 30.720 114.480 30.744 ;
    END
  END wd_in[320]
  PIN wd_in[321]
    DIRECTION INPUT ;
    USE SIGNAL ;
    SHAPE ABUTMENT ;
    PORT
      LAYER M4 ;
      RECT 114.456 30.912 114.480 30.936 ;
    END
  END wd_in[321]
  PIN wd_in[322]
    DIRECTION INPUT ;
    USE SIGNAL ;
    SHAPE ABUTMENT ;
    PORT
      LAYER M4 ;
      RECT 114.456 31.104 114.480 31.128 ;
    END
  END wd_in[322]
  PIN wd_in[323]
    DIRECTION INPUT ;
    USE SIGNAL ;
    SHAPE ABUTMENT ;
    PORT
      LAYER M4 ;
      RECT 114.456 31.296 114.480 31.320 ;
    END
  END wd_in[323]
  PIN wd_in[324]
    DIRECTION INPUT ;
    USE SIGNAL ;
    SHAPE ABUTMENT ;
    PORT
      LAYER M4 ;
      RECT 114.456 31.488 114.480 31.512 ;
    END
  END wd_in[324]
  PIN wd_in[325]
    DIRECTION INPUT ;
    USE SIGNAL ;
    SHAPE ABUTMENT ;
    PORT
      LAYER M4 ;
      RECT 114.456 31.680 114.480 31.704 ;
    END
  END wd_in[325]
  PIN wd_in[326]
    DIRECTION INPUT ;
    USE SIGNAL ;
    SHAPE ABUTMENT ;
    PORT
      LAYER M4 ;
      RECT 114.456 31.872 114.480 31.896 ;
    END
  END wd_in[326]
  PIN wd_in[327]
    DIRECTION INPUT ;
    USE SIGNAL ;
    SHAPE ABUTMENT ;
    PORT
      LAYER M4 ;
      RECT 114.456 32.064 114.480 32.088 ;
    END
  END wd_in[327]
  PIN wd_in[328]
    DIRECTION INPUT ;
    USE SIGNAL ;
    SHAPE ABUTMENT ;
    PORT
      LAYER M4 ;
      RECT 114.456 32.256 114.480 32.280 ;
    END
  END wd_in[328]
  PIN wd_in[329]
    DIRECTION INPUT ;
    USE SIGNAL ;
    SHAPE ABUTMENT ;
    PORT
      LAYER M4 ;
      RECT 114.456 32.448 114.480 32.472 ;
    END
  END wd_in[329]
  PIN wd_in[330]
    DIRECTION INPUT ;
    USE SIGNAL ;
    SHAPE ABUTMENT ;
    PORT
      LAYER M4 ;
      RECT 114.456 32.640 114.480 32.664 ;
    END
  END wd_in[330]
  PIN wd_in[331]
    DIRECTION INPUT ;
    USE SIGNAL ;
    SHAPE ABUTMENT ;
    PORT
      LAYER M4 ;
      RECT 114.456 32.832 114.480 32.856 ;
    END
  END wd_in[331]
  PIN wd_in[332]
    DIRECTION INPUT ;
    USE SIGNAL ;
    SHAPE ABUTMENT ;
    PORT
      LAYER M4 ;
      RECT 114.456 33.024 114.480 33.048 ;
    END
  END wd_in[332]
  PIN wd_in[333]
    DIRECTION INPUT ;
    USE SIGNAL ;
    SHAPE ABUTMENT ;
    PORT
      LAYER M4 ;
      RECT 114.456 33.216 114.480 33.240 ;
    END
  END wd_in[333]
  PIN wd_in[334]
    DIRECTION INPUT ;
    USE SIGNAL ;
    SHAPE ABUTMENT ;
    PORT
      LAYER M4 ;
      RECT 114.456 33.408 114.480 33.432 ;
    END
  END wd_in[334]
  PIN wd_in[335]
    DIRECTION INPUT ;
    USE SIGNAL ;
    SHAPE ABUTMENT ;
    PORT
      LAYER M4 ;
      RECT 114.456 33.600 114.480 33.624 ;
    END
  END wd_in[335]
  PIN wd_in[336]
    DIRECTION INPUT ;
    USE SIGNAL ;
    SHAPE ABUTMENT ;
    PORT
      LAYER M4 ;
      RECT 114.456 33.792 114.480 33.816 ;
    END
  END wd_in[336]
  PIN wd_in[337]
    DIRECTION INPUT ;
    USE SIGNAL ;
    SHAPE ABUTMENT ;
    PORT
      LAYER M4 ;
      RECT 114.456 33.984 114.480 34.008 ;
    END
  END wd_in[337]
  PIN wd_in[338]
    DIRECTION INPUT ;
    USE SIGNAL ;
    SHAPE ABUTMENT ;
    PORT
      LAYER M4 ;
      RECT 114.456 34.176 114.480 34.200 ;
    END
  END wd_in[338]
  PIN wd_in[339]
    DIRECTION INPUT ;
    USE SIGNAL ;
    SHAPE ABUTMENT ;
    PORT
      LAYER M4 ;
      RECT 114.456 34.368 114.480 34.392 ;
    END
  END wd_in[339]
  PIN w_mask_in[0]
    DIRECTION INPUT ;
    USE SIGNAL ;
    SHAPE ABUTMENT ;
    PORT
      LAYER M4 ;
      RECT 114.456 34.560 114.480 34.584 ;
    END
  END w_mask_in[0]
  PIN w_mask_in[1]
    DIRECTION INPUT ;
    USE SIGNAL ;
    SHAPE ABUTMENT ;
    PORT
      LAYER M4 ;
      RECT 114.456 34.752 114.480 34.776 ;
    END
  END w_mask_in[1]
  PIN w_mask_in[2]
    DIRECTION INPUT ;
    USE SIGNAL ;
    SHAPE ABUTMENT ;
    PORT
      LAYER M4 ;
      RECT 114.456 34.944 114.480 34.968 ;
    END
  END w_mask_in[2]
  PIN w_mask_in[3]
    DIRECTION INPUT ;
    USE SIGNAL ;
    SHAPE ABUTMENT ;
    PORT
      LAYER M4 ;
      RECT 114.456 35.136 114.480 35.160 ;
    END
  END w_mask_in[3]
  PIN w_mask_in[4]
    DIRECTION INPUT ;
    USE SIGNAL ;
    SHAPE ABUTMENT ;
    PORT
      LAYER M4 ;
      RECT 114.456 35.328 114.480 35.352 ;
    END
  END w_mask_in[4]
  PIN w_mask_in[5]
    DIRECTION INPUT ;
    USE SIGNAL ;
    SHAPE ABUTMENT ;
    PORT
      LAYER M4 ;
      RECT 114.456 35.520 114.480 35.544 ;
    END
  END w_mask_in[5]
  PIN w_mask_in[6]
    DIRECTION INPUT ;
    USE SIGNAL ;
    SHAPE ABUTMENT ;
    PORT
      LAYER M4 ;
      RECT 114.456 35.712 114.480 35.736 ;
    END
  END w_mask_in[6]
  PIN w_mask_in[7]
    DIRECTION INPUT ;
    USE SIGNAL ;
    SHAPE ABUTMENT ;
    PORT
      LAYER M4 ;
      RECT 114.456 35.904 114.480 35.928 ;
    END
  END w_mask_in[7]
  PIN w_mask_in[8]
    DIRECTION INPUT ;
    USE SIGNAL ;
    SHAPE ABUTMENT ;
    PORT
      LAYER M4 ;
      RECT 114.456 36.096 114.480 36.120 ;
    END
  END w_mask_in[8]
  PIN w_mask_in[9]
    DIRECTION INPUT ;
    USE SIGNAL ;
    SHAPE ABUTMENT ;
    PORT
      LAYER M4 ;
      RECT 114.456 36.288 114.480 36.312 ;
    END
  END w_mask_in[9]
  PIN w_mask_in[10]
    DIRECTION INPUT ;
    USE SIGNAL ;
    SHAPE ABUTMENT ;
    PORT
      LAYER M4 ;
      RECT 114.456 36.480 114.480 36.504 ;
    END
  END w_mask_in[10]
  PIN w_mask_in[11]
    DIRECTION INPUT ;
    USE SIGNAL ;
    SHAPE ABUTMENT ;
    PORT
      LAYER M4 ;
      RECT 114.456 36.672 114.480 36.696 ;
    END
  END w_mask_in[11]
  PIN w_mask_in[12]
    DIRECTION INPUT ;
    USE SIGNAL ;
    SHAPE ABUTMENT ;
    PORT
      LAYER M4 ;
      RECT 114.456 36.864 114.480 36.888 ;
    END
  END w_mask_in[12]
  PIN w_mask_in[13]
    DIRECTION INPUT ;
    USE SIGNAL ;
    SHAPE ABUTMENT ;
    PORT
      LAYER M4 ;
      RECT 114.456 37.056 114.480 37.080 ;
    END
  END w_mask_in[13]
  PIN w_mask_in[14]
    DIRECTION INPUT ;
    USE SIGNAL ;
    SHAPE ABUTMENT ;
    PORT
      LAYER M4 ;
      RECT 114.456 37.248 114.480 37.272 ;
    END
  END w_mask_in[14]
  PIN w_mask_in[15]
    DIRECTION INPUT ;
    USE SIGNAL ;
    SHAPE ABUTMENT ;
    PORT
      LAYER M4 ;
      RECT 114.456 37.440 114.480 37.464 ;
    END
  END w_mask_in[15]
  PIN w_mask_in[16]
    DIRECTION INPUT ;
    USE SIGNAL ;
    SHAPE ABUTMENT ;
    PORT
      LAYER M4 ;
      RECT 114.456 37.632 114.480 37.656 ;
    END
  END w_mask_in[16]
  PIN w_mask_in[17]
    DIRECTION INPUT ;
    USE SIGNAL ;
    SHAPE ABUTMENT ;
    PORT
      LAYER M4 ;
      RECT 114.456 37.824 114.480 37.848 ;
    END
  END w_mask_in[17]
  PIN w_mask_in[18]
    DIRECTION INPUT ;
    USE SIGNAL ;
    SHAPE ABUTMENT ;
    PORT
      LAYER M4 ;
      RECT 114.456 38.016 114.480 38.040 ;
    END
  END w_mask_in[18]
  PIN w_mask_in[19]
    DIRECTION INPUT ;
    USE SIGNAL ;
    SHAPE ABUTMENT ;
    PORT
      LAYER M4 ;
      RECT 114.456 38.208 114.480 38.232 ;
    END
  END w_mask_in[19]
  PIN w_mask_in[20]
    DIRECTION INPUT ;
    USE SIGNAL ;
    SHAPE ABUTMENT ;
    PORT
      LAYER M4 ;
      RECT 114.456 38.400 114.480 38.424 ;
    END
  END w_mask_in[20]
  PIN w_mask_in[21]
    DIRECTION INPUT ;
    USE SIGNAL ;
    SHAPE ABUTMENT ;
    PORT
      LAYER M4 ;
      RECT 114.456 38.592 114.480 38.616 ;
    END
  END w_mask_in[21]
  PIN w_mask_in[22]
    DIRECTION INPUT ;
    USE SIGNAL ;
    SHAPE ABUTMENT ;
    PORT
      LAYER M4 ;
      RECT 114.456 38.784 114.480 38.808 ;
    END
  END w_mask_in[22]
  PIN w_mask_in[23]
    DIRECTION INPUT ;
    USE SIGNAL ;
    SHAPE ABUTMENT ;
    PORT
      LAYER M4 ;
      RECT 114.456 38.976 114.480 39.000 ;
    END
  END w_mask_in[23]
  PIN w_mask_in[24]
    DIRECTION INPUT ;
    USE SIGNAL ;
    SHAPE ABUTMENT ;
    PORT
      LAYER M4 ;
      RECT 114.456 39.168 114.480 39.192 ;
    END
  END w_mask_in[24]
  PIN w_mask_in[25]
    DIRECTION INPUT ;
    USE SIGNAL ;
    SHAPE ABUTMENT ;
    PORT
      LAYER M4 ;
      RECT 114.456 39.360 114.480 39.384 ;
    END
  END w_mask_in[25]
  PIN w_mask_in[26]
    DIRECTION INPUT ;
    USE SIGNAL ;
    SHAPE ABUTMENT ;
    PORT
      LAYER M4 ;
      RECT 114.456 39.552 114.480 39.576 ;
    END
  END w_mask_in[26]
  PIN w_mask_in[27]
    DIRECTION INPUT ;
    USE SIGNAL ;
    SHAPE ABUTMENT ;
    PORT
      LAYER M4 ;
      RECT 114.456 39.744 114.480 39.768 ;
    END
  END w_mask_in[27]
  PIN w_mask_in[28]
    DIRECTION INPUT ;
    USE SIGNAL ;
    SHAPE ABUTMENT ;
    PORT
      LAYER M4 ;
      RECT 114.456 39.936 114.480 39.960 ;
    END
  END w_mask_in[28]
  PIN w_mask_in[29]
    DIRECTION INPUT ;
    USE SIGNAL ;
    SHAPE ABUTMENT ;
    PORT
      LAYER M4 ;
      RECT 114.456 40.128 114.480 40.152 ;
    END
  END w_mask_in[29]
  PIN w_mask_in[30]
    DIRECTION INPUT ;
    USE SIGNAL ;
    SHAPE ABUTMENT ;
    PORT
      LAYER M4 ;
      RECT 114.456 40.320 114.480 40.344 ;
    END
  END w_mask_in[30]
  PIN w_mask_in[31]
    DIRECTION INPUT ;
    USE SIGNAL ;
    SHAPE ABUTMENT ;
    PORT
      LAYER M4 ;
      RECT 114.456 40.512 114.480 40.536 ;
    END
  END w_mask_in[31]
  PIN w_mask_in[32]
    DIRECTION INPUT ;
    USE SIGNAL ;
    SHAPE ABUTMENT ;
    PORT
      LAYER M4 ;
      RECT 114.456 40.704 114.480 40.728 ;
    END
  END w_mask_in[32]
  PIN w_mask_in[33]
    DIRECTION INPUT ;
    USE SIGNAL ;
    SHAPE ABUTMENT ;
    PORT
      LAYER M4 ;
      RECT 114.456 40.896 114.480 40.920 ;
    END
  END w_mask_in[33]
  PIN w_mask_in[34]
    DIRECTION INPUT ;
    USE SIGNAL ;
    SHAPE ABUTMENT ;
    PORT
      LAYER M4 ;
      RECT 114.456 41.088 114.480 41.112 ;
    END
  END w_mask_in[34]
  PIN w_mask_in[35]
    DIRECTION INPUT ;
    USE SIGNAL ;
    SHAPE ABUTMENT ;
    PORT
      LAYER M4 ;
      RECT 114.456 41.280 114.480 41.304 ;
    END
  END w_mask_in[35]
  PIN w_mask_in[36]
    DIRECTION INPUT ;
    USE SIGNAL ;
    SHAPE ABUTMENT ;
    PORT
      LAYER M4 ;
      RECT 114.456 41.472 114.480 41.496 ;
    END
  END w_mask_in[36]
  PIN w_mask_in[37]
    DIRECTION INPUT ;
    USE SIGNAL ;
    SHAPE ABUTMENT ;
    PORT
      LAYER M4 ;
      RECT 114.456 41.664 114.480 41.688 ;
    END
  END w_mask_in[37]
  PIN w_mask_in[38]
    DIRECTION INPUT ;
    USE SIGNAL ;
    SHAPE ABUTMENT ;
    PORT
      LAYER M4 ;
      RECT 114.456 41.856 114.480 41.880 ;
    END
  END w_mask_in[38]
  PIN w_mask_in[39]
    DIRECTION INPUT ;
    USE SIGNAL ;
    SHAPE ABUTMENT ;
    PORT
      LAYER M4 ;
      RECT 114.456 42.048 114.480 42.072 ;
    END
  END w_mask_in[39]
  PIN w_mask_in[40]
    DIRECTION INPUT ;
    USE SIGNAL ;
    SHAPE ABUTMENT ;
    PORT
      LAYER M4 ;
      RECT 114.456 42.240 114.480 42.264 ;
    END
  END w_mask_in[40]
  PIN w_mask_in[41]
    DIRECTION INPUT ;
    USE SIGNAL ;
    SHAPE ABUTMENT ;
    PORT
      LAYER M4 ;
      RECT 114.456 42.432 114.480 42.456 ;
    END
  END w_mask_in[41]
  PIN w_mask_in[42]
    DIRECTION INPUT ;
    USE SIGNAL ;
    SHAPE ABUTMENT ;
    PORT
      LAYER M4 ;
      RECT 114.456 42.624 114.480 42.648 ;
    END
  END w_mask_in[42]
  PIN w_mask_in[43]
    DIRECTION INPUT ;
    USE SIGNAL ;
    SHAPE ABUTMENT ;
    PORT
      LAYER M4 ;
      RECT 114.456 42.816 114.480 42.840 ;
    END
  END w_mask_in[43]
  PIN w_mask_in[44]
    DIRECTION INPUT ;
    USE SIGNAL ;
    SHAPE ABUTMENT ;
    PORT
      LAYER M4 ;
      RECT 114.456 43.008 114.480 43.032 ;
    END
  END w_mask_in[44]
  PIN w_mask_in[45]
    DIRECTION INPUT ;
    USE SIGNAL ;
    SHAPE ABUTMENT ;
    PORT
      LAYER M4 ;
      RECT 114.456 43.200 114.480 43.224 ;
    END
  END w_mask_in[45]
  PIN w_mask_in[46]
    DIRECTION INPUT ;
    USE SIGNAL ;
    SHAPE ABUTMENT ;
    PORT
      LAYER M4 ;
      RECT 114.456 43.392 114.480 43.416 ;
    END
  END w_mask_in[46]
  PIN w_mask_in[47]
    DIRECTION INPUT ;
    USE SIGNAL ;
    SHAPE ABUTMENT ;
    PORT
      LAYER M4 ;
      RECT 114.456 43.584 114.480 43.608 ;
    END
  END w_mask_in[47]
  PIN w_mask_in[48]
    DIRECTION INPUT ;
    USE SIGNAL ;
    SHAPE ABUTMENT ;
    PORT
      LAYER M4 ;
      RECT 114.456 43.776 114.480 43.800 ;
    END
  END w_mask_in[48]
  PIN w_mask_in[49]
    DIRECTION INPUT ;
    USE SIGNAL ;
    SHAPE ABUTMENT ;
    PORT
      LAYER M4 ;
      RECT 114.456 43.968 114.480 43.992 ;
    END
  END w_mask_in[49]
  PIN w_mask_in[50]
    DIRECTION INPUT ;
    USE SIGNAL ;
    SHAPE ABUTMENT ;
    PORT
      LAYER M4 ;
      RECT 114.456 44.160 114.480 44.184 ;
    END
  END w_mask_in[50]
  PIN w_mask_in[51]
    DIRECTION INPUT ;
    USE SIGNAL ;
    SHAPE ABUTMENT ;
    PORT
      LAYER M4 ;
      RECT 114.456 44.352 114.480 44.376 ;
    END
  END w_mask_in[51]
  PIN w_mask_in[52]
    DIRECTION INPUT ;
    USE SIGNAL ;
    SHAPE ABUTMENT ;
    PORT
      LAYER M4 ;
      RECT 114.456 44.544 114.480 44.568 ;
    END
  END w_mask_in[52]
  PIN w_mask_in[53]
    DIRECTION INPUT ;
    USE SIGNAL ;
    SHAPE ABUTMENT ;
    PORT
      LAYER M4 ;
      RECT 114.456 44.736 114.480 44.760 ;
    END
  END w_mask_in[53]
  PIN w_mask_in[54]
    DIRECTION INPUT ;
    USE SIGNAL ;
    SHAPE ABUTMENT ;
    PORT
      LAYER M4 ;
      RECT 114.456 44.928 114.480 44.952 ;
    END
  END w_mask_in[54]
  PIN w_mask_in[55]
    DIRECTION INPUT ;
    USE SIGNAL ;
    SHAPE ABUTMENT ;
    PORT
      LAYER M4 ;
      RECT 114.456 45.120 114.480 45.144 ;
    END
  END w_mask_in[55]
  PIN w_mask_in[56]
    DIRECTION INPUT ;
    USE SIGNAL ;
    SHAPE ABUTMENT ;
    PORT
      LAYER M4 ;
      RECT 114.456 45.312 114.480 45.336 ;
    END
  END w_mask_in[56]
  PIN w_mask_in[57]
    DIRECTION INPUT ;
    USE SIGNAL ;
    SHAPE ABUTMENT ;
    PORT
      LAYER M4 ;
      RECT 114.456 45.504 114.480 45.528 ;
    END
  END w_mask_in[57]
  PIN w_mask_in[58]
    DIRECTION INPUT ;
    USE SIGNAL ;
    SHAPE ABUTMENT ;
    PORT
      LAYER M4 ;
      RECT 114.456 45.696 114.480 45.720 ;
    END
  END w_mask_in[58]
  PIN w_mask_in[59]
    DIRECTION INPUT ;
    USE SIGNAL ;
    SHAPE ABUTMENT ;
    PORT
      LAYER M4 ;
      RECT 114.456 45.888 114.480 45.912 ;
    END
  END w_mask_in[59]
  PIN w_mask_in[60]
    DIRECTION INPUT ;
    USE SIGNAL ;
    SHAPE ABUTMENT ;
    PORT
      LAYER M4 ;
      RECT 114.456 46.080 114.480 46.104 ;
    END
  END w_mask_in[60]
  PIN w_mask_in[61]
    DIRECTION INPUT ;
    USE SIGNAL ;
    SHAPE ABUTMENT ;
    PORT
      LAYER M4 ;
      RECT 114.456 46.272 114.480 46.296 ;
    END
  END w_mask_in[61]
  PIN w_mask_in[62]
    DIRECTION INPUT ;
    USE SIGNAL ;
    SHAPE ABUTMENT ;
    PORT
      LAYER M4 ;
      RECT 114.456 46.464 114.480 46.488 ;
    END
  END w_mask_in[62]
  PIN w_mask_in[63]
    DIRECTION INPUT ;
    USE SIGNAL ;
    SHAPE ABUTMENT ;
    PORT
      LAYER M4 ;
      RECT 114.456 46.656 114.480 46.680 ;
    END
  END w_mask_in[63]
  PIN w_mask_in[64]
    DIRECTION INPUT ;
    USE SIGNAL ;
    SHAPE ABUTMENT ;
    PORT
      LAYER M4 ;
      RECT 114.456 46.848 114.480 46.872 ;
    END
  END w_mask_in[64]
  PIN w_mask_in[65]
    DIRECTION INPUT ;
    USE SIGNAL ;
    SHAPE ABUTMENT ;
    PORT
      LAYER M4 ;
      RECT 114.456 47.040 114.480 47.064 ;
    END
  END w_mask_in[65]
  PIN w_mask_in[66]
    DIRECTION INPUT ;
    USE SIGNAL ;
    SHAPE ABUTMENT ;
    PORT
      LAYER M4 ;
      RECT 114.456 47.232 114.480 47.256 ;
    END
  END w_mask_in[66]
  PIN w_mask_in[67]
    DIRECTION INPUT ;
    USE SIGNAL ;
    SHAPE ABUTMENT ;
    PORT
      LAYER M4 ;
      RECT 114.456 47.424 114.480 47.448 ;
    END
  END w_mask_in[67]
  PIN w_mask_in[68]
    DIRECTION INPUT ;
    USE SIGNAL ;
    SHAPE ABUTMENT ;
    PORT
      LAYER M4 ;
      RECT 114.456 47.616 114.480 47.640 ;
    END
  END w_mask_in[68]
  PIN w_mask_in[69]
    DIRECTION INPUT ;
    USE SIGNAL ;
    SHAPE ABUTMENT ;
    PORT
      LAYER M4 ;
      RECT 114.456 47.808 114.480 47.832 ;
    END
  END w_mask_in[69]
  PIN w_mask_in[70]
    DIRECTION INPUT ;
    USE SIGNAL ;
    SHAPE ABUTMENT ;
    PORT
      LAYER M4 ;
      RECT 114.456 48.000 114.480 48.024 ;
    END
  END w_mask_in[70]
  PIN w_mask_in[71]
    DIRECTION INPUT ;
    USE SIGNAL ;
    SHAPE ABUTMENT ;
    PORT
      LAYER M4 ;
      RECT 114.456 48.192 114.480 48.216 ;
    END
  END w_mask_in[71]
  PIN w_mask_in[72]
    DIRECTION INPUT ;
    USE SIGNAL ;
    SHAPE ABUTMENT ;
    PORT
      LAYER M4 ;
      RECT 114.456 48.384 114.480 48.408 ;
    END
  END w_mask_in[72]
  PIN w_mask_in[73]
    DIRECTION INPUT ;
    USE SIGNAL ;
    SHAPE ABUTMENT ;
    PORT
      LAYER M4 ;
      RECT 114.456 48.576 114.480 48.600 ;
    END
  END w_mask_in[73]
  PIN w_mask_in[74]
    DIRECTION INPUT ;
    USE SIGNAL ;
    SHAPE ABUTMENT ;
    PORT
      LAYER M4 ;
      RECT 114.456 48.768 114.480 48.792 ;
    END
  END w_mask_in[74]
  PIN w_mask_in[75]
    DIRECTION INPUT ;
    USE SIGNAL ;
    SHAPE ABUTMENT ;
    PORT
      LAYER M4 ;
      RECT 114.456 48.960 114.480 48.984 ;
    END
  END w_mask_in[75]
  PIN w_mask_in[76]
    DIRECTION INPUT ;
    USE SIGNAL ;
    SHAPE ABUTMENT ;
    PORT
      LAYER M4 ;
      RECT 114.456 49.152 114.480 49.176 ;
    END
  END w_mask_in[76]
  PIN w_mask_in[77]
    DIRECTION INPUT ;
    USE SIGNAL ;
    SHAPE ABUTMENT ;
    PORT
      LAYER M4 ;
      RECT 114.456 49.344 114.480 49.368 ;
    END
  END w_mask_in[77]
  PIN w_mask_in[78]
    DIRECTION INPUT ;
    USE SIGNAL ;
    SHAPE ABUTMENT ;
    PORT
      LAYER M4 ;
      RECT 114.456 49.536 114.480 49.560 ;
    END
  END w_mask_in[78]
  PIN w_mask_in[79]
    DIRECTION INPUT ;
    USE SIGNAL ;
    SHAPE ABUTMENT ;
    PORT
      LAYER M4 ;
      RECT 114.456 49.728 114.480 49.752 ;
    END
  END w_mask_in[79]
  PIN w_mask_in[80]
    DIRECTION INPUT ;
    USE SIGNAL ;
    SHAPE ABUTMENT ;
    PORT
      LAYER M4 ;
      RECT 114.456 49.920 114.480 49.944 ;
    END
  END w_mask_in[80]
  PIN w_mask_in[81]
    DIRECTION INPUT ;
    USE SIGNAL ;
    SHAPE ABUTMENT ;
    PORT
      LAYER M4 ;
      RECT 114.456 50.112 114.480 50.136 ;
    END
  END w_mask_in[81]
  PIN w_mask_in[82]
    DIRECTION INPUT ;
    USE SIGNAL ;
    SHAPE ABUTMENT ;
    PORT
      LAYER M4 ;
      RECT 114.456 50.304 114.480 50.328 ;
    END
  END w_mask_in[82]
  PIN w_mask_in[83]
    DIRECTION INPUT ;
    USE SIGNAL ;
    SHAPE ABUTMENT ;
    PORT
      LAYER M4 ;
      RECT 114.456 50.496 114.480 50.520 ;
    END
  END w_mask_in[83]
  PIN w_mask_in[84]
    DIRECTION INPUT ;
    USE SIGNAL ;
    SHAPE ABUTMENT ;
    PORT
      LAYER M4 ;
      RECT 114.456 50.688 114.480 50.712 ;
    END
  END w_mask_in[84]
  PIN w_mask_in[85]
    DIRECTION INPUT ;
    USE SIGNAL ;
    SHAPE ABUTMENT ;
    PORT
      LAYER M4 ;
      RECT 114.456 50.880 114.480 50.904 ;
    END
  END w_mask_in[85]
  PIN w_mask_in[86]
    DIRECTION INPUT ;
    USE SIGNAL ;
    SHAPE ABUTMENT ;
    PORT
      LAYER M4 ;
      RECT 114.456 51.072 114.480 51.096 ;
    END
  END w_mask_in[86]
  PIN w_mask_in[87]
    DIRECTION INPUT ;
    USE SIGNAL ;
    SHAPE ABUTMENT ;
    PORT
      LAYER M4 ;
      RECT 114.456 51.264 114.480 51.288 ;
    END
  END w_mask_in[87]
  PIN w_mask_in[88]
    DIRECTION INPUT ;
    USE SIGNAL ;
    SHAPE ABUTMENT ;
    PORT
      LAYER M4 ;
      RECT 114.456 51.456 114.480 51.480 ;
    END
  END w_mask_in[88]
  PIN w_mask_in[89]
    DIRECTION INPUT ;
    USE SIGNAL ;
    SHAPE ABUTMENT ;
    PORT
      LAYER M4 ;
      RECT 114.456 51.648 114.480 51.672 ;
    END
  END w_mask_in[89]
  PIN w_mask_in[90]
    DIRECTION INPUT ;
    USE SIGNAL ;
    SHAPE ABUTMENT ;
    PORT
      LAYER M4 ;
      RECT 114.456 51.840 114.480 51.864 ;
    END
  END w_mask_in[90]
  PIN w_mask_in[91]
    DIRECTION INPUT ;
    USE SIGNAL ;
    SHAPE ABUTMENT ;
    PORT
      LAYER M4 ;
      RECT 114.456 52.032 114.480 52.056 ;
    END
  END w_mask_in[91]
  PIN w_mask_in[92]
    DIRECTION INPUT ;
    USE SIGNAL ;
    SHAPE ABUTMENT ;
    PORT
      LAYER M4 ;
      RECT 114.456 52.224 114.480 52.248 ;
    END
  END w_mask_in[92]
  PIN w_mask_in[93]
    DIRECTION INPUT ;
    USE SIGNAL ;
    SHAPE ABUTMENT ;
    PORT
      LAYER M4 ;
      RECT 114.456 52.416 114.480 52.440 ;
    END
  END w_mask_in[93]
  PIN w_mask_in[94]
    DIRECTION INPUT ;
    USE SIGNAL ;
    SHAPE ABUTMENT ;
    PORT
      LAYER M4 ;
      RECT 114.456 52.608 114.480 52.632 ;
    END
  END w_mask_in[94]
  PIN w_mask_in[95]
    DIRECTION INPUT ;
    USE SIGNAL ;
    SHAPE ABUTMENT ;
    PORT
      LAYER M4 ;
      RECT 114.456 52.800 114.480 52.824 ;
    END
  END w_mask_in[95]
  PIN w_mask_in[96]
    DIRECTION INPUT ;
    USE SIGNAL ;
    SHAPE ABUTMENT ;
    PORT
      LAYER M4 ;
      RECT 114.456 52.992 114.480 53.016 ;
    END
  END w_mask_in[96]
  PIN w_mask_in[97]
    DIRECTION INPUT ;
    USE SIGNAL ;
    SHAPE ABUTMENT ;
    PORT
      LAYER M4 ;
      RECT 114.456 53.184 114.480 53.208 ;
    END
  END w_mask_in[97]
  PIN w_mask_in[98]
    DIRECTION INPUT ;
    USE SIGNAL ;
    SHAPE ABUTMENT ;
    PORT
      LAYER M4 ;
      RECT 114.456 53.376 114.480 53.400 ;
    END
  END w_mask_in[98]
  PIN w_mask_in[99]
    DIRECTION INPUT ;
    USE SIGNAL ;
    SHAPE ABUTMENT ;
    PORT
      LAYER M4 ;
      RECT 114.456 53.568 114.480 53.592 ;
    END
  END w_mask_in[99]
  PIN w_mask_in[100]
    DIRECTION INPUT ;
    USE SIGNAL ;
    SHAPE ABUTMENT ;
    PORT
      LAYER M4 ;
      RECT 114.456 53.760 114.480 53.784 ;
    END
  END w_mask_in[100]
  PIN w_mask_in[101]
    DIRECTION INPUT ;
    USE SIGNAL ;
    SHAPE ABUTMENT ;
    PORT
      LAYER M4 ;
      RECT 114.456 53.952 114.480 53.976 ;
    END
  END w_mask_in[101]
  PIN w_mask_in[102]
    DIRECTION INPUT ;
    USE SIGNAL ;
    SHAPE ABUTMENT ;
    PORT
      LAYER M4 ;
      RECT 114.456 54.144 114.480 54.168 ;
    END
  END w_mask_in[102]
  PIN w_mask_in[103]
    DIRECTION INPUT ;
    USE SIGNAL ;
    SHAPE ABUTMENT ;
    PORT
      LAYER M4 ;
      RECT 114.456 54.336 114.480 54.360 ;
    END
  END w_mask_in[103]
  PIN w_mask_in[104]
    DIRECTION INPUT ;
    USE SIGNAL ;
    SHAPE ABUTMENT ;
    PORT
      LAYER M4 ;
      RECT 114.456 54.528 114.480 54.552 ;
    END
  END w_mask_in[104]
  PIN w_mask_in[105]
    DIRECTION INPUT ;
    USE SIGNAL ;
    SHAPE ABUTMENT ;
    PORT
      LAYER M4 ;
      RECT 114.456 54.720 114.480 54.744 ;
    END
  END w_mask_in[105]
  PIN w_mask_in[106]
    DIRECTION INPUT ;
    USE SIGNAL ;
    SHAPE ABUTMENT ;
    PORT
      LAYER M4 ;
      RECT 114.456 54.912 114.480 54.936 ;
    END
  END w_mask_in[106]
  PIN w_mask_in[107]
    DIRECTION INPUT ;
    USE SIGNAL ;
    SHAPE ABUTMENT ;
    PORT
      LAYER M4 ;
      RECT 114.456 55.104 114.480 55.128 ;
    END
  END w_mask_in[107]
  PIN w_mask_in[108]
    DIRECTION INPUT ;
    USE SIGNAL ;
    SHAPE ABUTMENT ;
    PORT
      LAYER M4 ;
      RECT 114.456 55.296 114.480 55.320 ;
    END
  END w_mask_in[108]
  PIN w_mask_in[109]
    DIRECTION INPUT ;
    USE SIGNAL ;
    SHAPE ABUTMENT ;
    PORT
      LAYER M4 ;
      RECT 114.456 55.488 114.480 55.512 ;
    END
  END w_mask_in[109]
  PIN w_mask_in[110]
    DIRECTION INPUT ;
    USE SIGNAL ;
    SHAPE ABUTMENT ;
    PORT
      LAYER M4 ;
      RECT 114.456 55.680 114.480 55.704 ;
    END
  END w_mask_in[110]
  PIN w_mask_in[111]
    DIRECTION INPUT ;
    USE SIGNAL ;
    SHAPE ABUTMENT ;
    PORT
      LAYER M4 ;
      RECT 114.456 55.872 114.480 55.896 ;
    END
  END w_mask_in[111]
  PIN w_mask_in[112]
    DIRECTION INPUT ;
    USE SIGNAL ;
    SHAPE ABUTMENT ;
    PORT
      LAYER M4 ;
      RECT 114.456 56.064 114.480 56.088 ;
    END
  END w_mask_in[112]
  PIN w_mask_in[113]
    DIRECTION INPUT ;
    USE SIGNAL ;
    SHAPE ABUTMENT ;
    PORT
      LAYER M4 ;
      RECT 114.456 56.256 114.480 56.280 ;
    END
  END w_mask_in[113]
  PIN w_mask_in[114]
    DIRECTION INPUT ;
    USE SIGNAL ;
    SHAPE ABUTMENT ;
    PORT
      LAYER M4 ;
      RECT 114.456 56.448 114.480 56.472 ;
    END
  END w_mask_in[114]
  PIN w_mask_in[115]
    DIRECTION INPUT ;
    USE SIGNAL ;
    SHAPE ABUTMENT ;
    PORT
      LAYER M4 ;
      RECT 114.456 56.640 114.480 56.664 ;
    END
  END w_mask_in[115]
  PIN w_mask_in[116]
    DIRECTION INPUT ;
    USE SIGNAL ;
    SHAPE ABUTMENT ;
    PORT
      LAYER M4 ;
      RECT 114.456 56.832 114.480 56.856 ;
    END
  END w_mask_in[116]
  PIN w_mask_in[117]
    DIRECTION INPUT ;
    USE SIGNAL ;
    SHAPE ABUTMENT ;
    PORT
      LAYER M4 ;
      RECT 114.456 57.024 114.480 57.048 ;
    END
  END w_mask_in[117]
  PIN w_mask_in[118]
    DIRECTION INPUT ;
    USE SIGNAL ;
    SHAPE ABUTMENT ;
    PORT
      LAYER M4 ;
      RECT 114.456 57.216 114.480 57.240 ;
    END
  END w_mask_in[118]
  PIN w_mask_in[119]
    DIRECTION INPUT ;
    USE SIGNAL ;
    SHAPE ABUTMENT ;
    PORT
      LAYER M4 ;
      RECT 114.456 57.408 114.480 57.432 ;
    END
  END w_mask_in[119]
  PIN w_mask_in[120]
    DIRECTION INPUT ;
    USE SIGNAL ;
    SHAPE ABUTMENT ;
    PORT
      LAYER M4 ;
      RECT 114.456 57.600 114.480 57.624 ;
    END
  END w_mask_in[120]
  PIN w_mask_in[121]
    DIRECTION INPUT ;
    USE SIGNAL ;
    SHAPE ABUTMENT ;
    PORT
      LAYER M4 ;
      RECT 114.456 57.792 114.480 57.816 ;
    END
  END w_mask_in[121]
  PIN w_mask_in[122]
    DIRECTION INPUT ;
    USE SIGNAL ;
    SHAPE ABUTMENT ;
    PORT
      LAYER M4 ;
      RECT 114.456 57.984 114.480 58.008 ;
    END
  END w_mask_in[122]
  PIN w_mask_in[123]
    DIRECTION INPUT ;
    USE SIGNAL ;
    SHAPE ABUTMENT ;
    PORT
      LAYER M4 ;
      RECT 114.456 58.176 114.480 58.200 ;
    END
  END w_mask_in[123]
  PIN w_mask_in[124]
    DIRECTION INPUT ;
    USE SIGNAL ;
    SHAPE ABUTMENT ;
    PORT
      LAYER M4 ;
      RECT 114.456 58.368 114.480 58.392 ;
    END
  END w_mask_in[124]
  PIN w_mask_in[125]
    DIRECTION INPUT ;
    USE SIGNAL ;
    SHAPE ABUTMENT ;
    PORT
      LAYER M4 ;
      RECT 114.456 58.560 114.480 58.584 ;
    END
  END w_mask_in[125]
  PIN w_mask_in[126]
    DIRECTION INPUT ;
    USE SIGNAL ;
    SHAPE ABUTMENT ;
    PORT
      LAYER M4 ;
      RECT 114.456 58.752 114.480 58.776 ;
    END
  END w_mask_in[126]
  PIN w_mask_in[127]
    DIRECTION INPUT ;
    USE SIGNAL ;
    SHAPE ABUTMENT ;
    PORT
      LAYER M4 ;
      RECT 114.456 58.944 114.480 58.968 ;
    END
  END w_mask_in[127]
  PIN w_mask_in[128]
    DIRECTION INPUT ;
    USE SIGNAL ;
    SHAPE ABUTMENT ;
    PORT
      LAYER M4 ;
      RECT 114.456 59.136 114.480 59.160 ;
    END
  END w_mask_in[128]
  PIN w_mask_in[129]
    DIRECTION INPUT ;
    USE SIGNAL ;
    SHAPE ABUTMENT ;
    PORT
      LAYER M4 ;
      RECT 114.456 59.328 114.480 59.352 ;
    END
  END w_mask_in[129]
  PIN w_mask_in[130]
    DIRECTION INPUT ;
    USE SIGNAL ;
    SHAPE ABUTMENT ;
    PORT
      LAYER M4 ;
      RECT 114.456 59.520 114.480 59.544 ;
    END
  END w_mask_in[130]
  PIN w_mask_in[131]
    DIRECTION INPUT ;
    USE SIGNAL ;
    SHAPE ABUTMENT ;
    PORT
      LAYER M4 ;
      RECT 114.456 59.712 114.480 59.736 ;
    END
  END w_mask_in[131]
  PIN w_mask_in[132]
    DIRECTION INPUT ;
    USE SIGNAL ;
    SHAPE ABUTMENT ;
    PORT
      LAYER M4 ;
      RECT 114.456 59.904 114.480 59.928 ;
    END
  END w_mask_in[132]
  PIN w_mask_in[133]
    DIRECTION INPUT ;
    USE SIGNAL ;
    SHAPE ABUTMENT ;
    PORT
      LAYER M4 ;
      RECT 114.456 60.096 114.480 60.120 ;
    END
  END w_mask_in[133]
  PIN w_mask_in[134]
    DIRECTION INPUT ;
    USE SIGNAL ;
    SHAPE ABUTMENT ;
    PORT
      LAYER M4 ;
      RECT 114.456 60.288 114.480 60.312 ;
    END
  END w_mask_in[134]
  PIN w_mask_in[135]
    DIRECTION INPUT ;
    USE SIGNAL ;
    SHAPE ABUTMENT ;
    PORT
      LAYER M4 ;
      RECT 114.456 60.480 114.480 60.504 ;
    END
  END w_mask_in[135]
  PIN w_mask_in[136]
    DIRECTION INPUT ;
    USE SIGNAL ;
    SHAPE ABUTMENT ;
    PORT
      LAYER M4 ;
      RECT 114.456 60.672 114.480 60.696 ;
    END
  END w_mask_in[136]
  PIN w_mask_in[137]
    DIRECTION INPUT ;
    USE SIGNAL ;
    SHAPE ABUTMENT ;
    PORT
      LAYER M4 ;
      RECT 114.456 60.864 114.480 60.888 ;
    END
  END w_mask_in[137]
  PIN w_mask_in[138]
    DIRECTION INPUT ;
    USE SIGNAL ;
    SHAPE ABUTMENT ;
    PORT
      LAYER M4 ;
      RECT 114.456 61.056 114.480 61.080 ;
    END
  END w_mask_in[138]
  PIN w_mask_in[139]
    DIRECTION INPUT ;
    USE SIGNAL ;
    SHAPE ABUTMENT ;
    PORT
      LAYER M4 ;
      RECT 114.456 61.248 114.480 61.272 ;
    END
  END w_mask_in[139]
  PIN w_mask_in[140]
    DIRECTION INPUT ;
    USE SIGNAL ;
    SHAPE ABUTMENT ;
    PORT
      LAYER M4 ;
      RECT 114.456 61.440 114.480 61.464 ;
    END
  END w_mask_in[140]
  PIN w_mask_in[141]
    DIRECTION INPUT ;
    USE SIGNAL ;
    SHAPE ABUTMENT ;
    PORT
      LAYER M4 ;
      RECT 114.456 61.632 114.480 61.656 ;
    END
  END w_mask_in[141]
  PIN w_mask_in[142]
    DIRECTION INPUT ;
    USE SIGNAL ;
    SHAPE ABUTMENT ;
    PORT
      LAYER M4 ;
      RECT 114.456 61.824 114.480 61.848 ;
    END
  END w_mask_in[142]
  PIN w_mask_in[143]
    DIRECTION INPUT ;
    USE SIGNAL ;
    SHAPE ABUTMENT ;
    PORT
      LAYER M4 ;
      RECT 114.456 62.016 114.480 62.040 ;
    END
  END w_mask_in[143]
  PIN w_mask_in[144]
    DIRECTION INPUT ;
    USE SIGNAL ;
    SHAPE ABUTMENT ;
    PORT
      LAYER M4 ;
      RECT 114.456 62.208 114.480 62.232 ;
    END
  END w_mask_in[144]
  PIN w_mask_in[145]
    DIRECTION INPUT ;
    USE SIGNAL ;
    SHAPE ABUTMENT ;
    PORT
      LAYER M4 ;
      RECT 114.456 62.400 114.480 62.424 ;
    END
  END w_mask_in[145]
  PIN w_mask_in[146]
    DIRECTION INPUT ;
    USE SIGNAL ;
    SHAPE ABUTMENT ;
    PORT
      LAYER M4 ;
      RECT 114.456 62.592 114.480 62.616 ;
    END
  END w_mask_in[146]
  PIN w_mask_in[147]
    DIRECTION INPUT ;
    USE SIGNAL ;
    SHAPE ABUTMENT ;
    PORT
      LAYER M4 ;
      RECT 114.456 62.784 114.480 62.808 ;
    END
  END w_mask_in[147]
  PIN w_mask_in[148]
    DIRECTION INPUT ;
    USE SIGNAL ;
    SHAPE ABUTMENT ;
    PORT
      LAYER M4 ;
      RECT 114.456 62.976 114.480 63.000 ;
    END
  END w_mask_in[148]
  PIN w_mask_in[149]
    DIRECTION INPUT ;
    USE SIGNAL ;
    SHAPE ABUTMENT ;
    PORT
      LAYER M4 ;
      RECT 114.456 63.168 114.480 63.192 ;
    END
  END w_mask_in[149]
  PIN w_mask_in[150]
    DIRECTION INPUT ;
    USE SIGNAL ;
    SHAPE ABUTMENT ;
    PORT
      LAYER M4 ;
      RECT 114.456 63.360 114.480 63.384 ;
    END
  END w_mask_in[150]
  PIN w_mask_in[151]
    DIRECTION INPUT ;
    USE SIGNAL ;
    SHAPE ABUTMENT ;
    PORT
      LAYER M4 ;
      RECT 114.456 63.552 114.480 63.576 ;
    END
  END w_mask_in[151]
  PIN w_mask_in[152]
    DIRECTION INPUT ;
    USE SIGNAL ;
    SHAPE ABUTMENT ;
    PORT
      LAYER M4 ;
      RECT 114.456 63.744 114.480 63.768 ;
    END
  END w_mask_in[152]
  PIN w_mask_in[153]
    DIRECTION INPUT ;
    USE SIGNAL ;
    SHAPE ABUTMENT ;
    PORT
      LAYER M4 ;
      RECT 114.456 63.936 114.480 63.960 ;
    END
  END w_mask_in[153]
  PIN w_mask_in[154]
    DIRECTION INPUT ;
    USE SIGNAL ;
    SHAPE ABUTMENT ;
    PORT
      LAYER M4 ;
      RECT 114.456 64.128 114.480 64.152 ;
    END
  END w_mask_in[154]
  PIN w_mask_in[155]
    DIRECTION INPUT ;
    USE SIGNAL ;
    SHAPE ABUTMENT ;
    PORT
      LAYER M4 ;
      RECT 114.456 64.320 114.480 64.344 ;
    END
  END w_mask_in[155]
  PIN w_mask_in[156]
    DIRECTION INPUT ;
    USE SIGNAL ;
    SHAPE ABUTMENT ;
    PORT
      LAYER M4 ;
      RECT 114.456 64.512 114.480 64.536 ;
    END
  END w_mask_in[156]
  PIN w_mask_in[157]
    DIRECTION INPUT ;
    USE SIGNAL ;
    SHAPE ABUTMENT ;
    PORT
      LAYER M4 ;
      RECT 114.456 64.704 114.480 64.728 ;
    END
  END w_mask_in[157]
  PIN w_mask_in[158]
    DIRECTION INPUT ;
    USE SIGNAL ;
    SHAPE ABUTMENT ;
    PORT
      LAYER M4 ;
      RECT 114.456 64.896 114.480 64.920 ;
    END
  END w_mask_in[158]
  PIN w_mask_in[159]
    DIRECTION INPUT ;
    USE SIGNAL ;
    SHAPE ABUTMENT ;
    PORT
      LAYER M4 ;
      RECT 114.456 65.088 114.480 65.112 ;
    END
  END w_mask_in[159]
  PIN w_mask_in[160]
    DIRECTION INPUT ;
    USE SIGNAL ;
    SHAPE ABUTMENT ;
    PORT
      LAYER M4 ;
      RECT 114.456 65.280 114.480 65.304 ;
    END
  END w_mask_in[160]
  PIN w_mask_in[161]
    DIRECTION INPUT ;
    USE SIGNAL ;
    SHAPE ABUTMENT ;
    PORT
      LAYER M4 ;
      RECT 114.456 65.472 114.480 65.496 ;
    END
  END w_mask_in[161]
  PIN w_mask_in[162]
    DIRECTION INPUT ;
    USE SIGNAL ;
    SHAPE ABUTMENT ;
    PORT
      LAYER M4 ;
      RECT 114.456 65.664 114.480 65.688 ;
    END
  END w_mask_in[162]
  PIN w_mask_in[163]
    DIRECTION INPUT ;
    USE SIGNAL ;
    SHAPE ABUTMENT ;
    PORT
      LAYER M4 ;
      RECT 114.456 65.856 114.480 65.880 ;
    END
  END w_mask_in[163]
  PIN w_mask_in[164]
    DIRECTION INPUT ;
    USE SIGNAL ;
    SHAPE ABUTMENT ;
    PORT
      LAYER M4 ;
      RECT 114.456 66.048 114.480 66.072 ;
    END
  END w_mask_in[164]
  PIN w_mask_in[165]
    DIRECTION INPUT ;
    USE SIGNAL ;
    SHAPE ABUTMENT ;
    PORT
      LAYER M4 ;
      RECT 114.456 66.240 114.480 66.264 ;
    END
  END w_mask_in[165]
  PIN w_mask_in[166]
    DIRECTION INPUT ;
    USE SIGNAL ;
    SHAPE ABUTMENT ;
    PORT
      LAYER M4 ;
      RECT 114.456 66.432 114.480 66.456 ;
    END
  END w_mask_in[166]
  PIN w_mask_in[167]
    DIRECTION INPUT ;
    USE SIGNAL ;
    SHAPE ABUTMENT ;
    PORT
      LAYER M4 ;
      RECT 114.456 66.624 114.480 66.648 ;
    END
  END w_mask_in[167]
  PIN w_mask_in[168]
    DIRECTION INPUT ;
    USE SIGNAL ;
    SHAPE ABUTMENT ;
    PORT
      LAYER M4 ;
      RECT 114.456 66.816 114.480 66.840 ;
    END
  END w_mask_in[168]
  PIN w_mask_in[169]
    DIRECTION INPUT ;
    USE SIGNAL ;
    SHAPE ABUTMENT ;
    PORT
      LAYER M4 ;
      RECT 114.456 67.008 114.480 67.032 ;
    END
  END w_mask_in[169]
  PIN w_mask_in[170]
    DIRECTION INPUT ;
    USE SIGNAL ;
    SHAPE ABUTMENT ;
    PORT
      LAYER M4 ;
      RECT 114.456 67.200 114.480 67.224 ;
    END
  END w_mask_in[170]
  PIN w_mask_in[171]
    DIRECTION INPUT ;
    USE SIGNAL ;
    SHAPE ABUTMENT ;
    PORT
      LAYER M4 ;
      RECT 114.456 67.392 114.480 67.416 ;
    END
  END w_mask_in[171]
  PIN w_mask_in[172]
    DIRECTION INPUT ;
    USE SIGNAL ;
    SHAPE ABUTMENT ;
    PORT
      LAYER M4 ;
      RECT 114.456 67.584 114.480 67.608 ;
    END
  END w_mask_in[172]
  PIN w_mask_in[173]
    DIRECTION INPUT ;
    USE SIGNAL ;
    SHAPE ABUTMENT ;
    PORT
      LAYER M4 ;
      RECT 114.456 67.776 114.480 67.800 ;
    END
  END w_mask_in[173]
  PIN w_mask_in[174]
    DIRECTION INPUT ;
    USE SIGNAL ;
    SHAPE ABUTMENT ;
    PORT
      LAYER M4 ;
      RECT 114.456 67.968 114.480 67.992 ;
    END
  END w_mask_in[174]
  PIN w_mask_in[175]
    DIRECTION INPUT ;
    USE SIGNAL ;
    SHAPE ABUTMENT ;
    PORT
      LAYER M4 ;
      RECT 114.456 68.160 114.480 68.184 ;
    END
  END w_mask_in[175]
  PIN w_mask_in[176]
    DIRECTION INPUT ;
    USE SIGNAL ;
    SHAPE ABUTMENT ;
    PORT
      LAYER M4 ;
      RECT 114.456 68.352 114.480 68.376 ;
    END
  END w_mask_in[176]
  PIN w_mask_in[177]
    DIRECTION INPUT ;
    USE SIGNAL ;
    SHAPE ABUTMENT ;
    PORT
      LAYER M4 ;
      RECT 114.456 68.544 114.480 68.568 ;
    END
  END w_mask_in[177]
  PIN w_mask_in[178]
    DIRECTION INPUT ;
    USE SIGNAL ;
    SHAPE ABUTMENT ;
    PORT
      LAYER M4 ;
      RECT 114.456 68.736 114.480 68.760 ;
    END
  END w_mask_in[178]
  PIN w_mask_in[179]
    DIRECTION INPUT ;
    USE SIGNAL ;
    SHAPE ABUTMENT ;
    PORT
      LAYER M4 ;
      RECT 114.456 68.928 114.480 68.952 ;
    END
  END w_mask_in[179]
  PIN w_mask_in[180]
    DIRECTION INPUT ;
    USE SIGNAL ;
    SHAPE ABUTMENT ;
    PORT
      LAYER M4 ;
      RECT 114.456 69.120 114.480 69.144 ;
    END
  END w_mask_in[180]
  PIN w_mask_in[181]
    DIRECTION INPUT ;
    USE SIGNAL ;
    SHAPE ABUTMENT ;
    PORT
      LAYER M4 ;
      RECT 114.456 69.312 114.480 69.336 ;
    END
  END w_mask_in[181]
  PIN w_mask_in[182]
    DIRECTION INPUT ;
    USE SIGNAL ;
    SHAPE ABUTMENT ;
    PORT
      LAYER M4 ;
      RECT 114.456 69.504 114.480 69.528 ;
    END
  END w_mask_in[182]
  PIN w_mask_in[183]
    DIRECTION INPUT ;
    USE SIGNAL ;
    SHAPE ABUTMENT ;
    PORT
      LAYER M4 ;
      RECT 114.456 69.696 114.480 69.720 ;
    END
  END w_mask_in[183]
  PIN w_mask_in[184]
    DIRECTION INPUT ;
    USE SIGNAL ;
    SHAPE ABUTMENT ;
    PORT
      LAYER M4 ;
      RECT 114.456 69.888 114.480 69.912 ;
    END
  END w_mask_in[184]
  PIN w_mask_in[185]
    DIRECTION INPUT ;
    USE SIGNAL ;
    SHAPE ABUTMENT ;
    PORT
      LAYER M4 ;
      RECT 114.456 70.080 114.480 70.104 ;
    END
  END w_mask_in[185]
  PIN w_mask_in[186]
    DIRECTION INPUT ;
    USE SIGNAL ;
    SHAPE ABUTMENT ;
    PORT
      LAYER M4 ;
      RECT 114.456 70.272 114.480 70.296 ;
    END
  END w_mask_in[186]
  PIN w_mask_in[187]
    DIRECTION INPUT ;
    USE SIGNAL ;
    SHAPE ABUTMENT ;
    PORT
      LAYER M4 ;
      RECT 114.456 70.464 114.480 70.488 ;
    END
  END w_mask_in[187]
  PIN w_mask_in[188]
    DIRECTION INPUT ;
    USE SIGNAL ;
    SHAPE ABUTMENT ;
    PORT
      LAYER M4 ;
      RECT 114.456 70.656 114.480 70.680 ;
    END
  END w_mask_in[188]
  PIN w_mask_in[189]
    DIRECTION INPUT ;
    USE SIGNAL ;
    SHAPE ABUTMENT ;
    PORT
      LAYER M4 ;
      RECT 114.456 70.848 114.480 70.872 ;
    END
  END w_mask_in[189]
  PIN w_mask_in[190]
    DIRECTION INPUT ;
    USE SIGNAL ;
    SHAPE ABUTMENT ;
    PORT
      LAYER M4 ;
      RECT 114.456 71.040 114.480 71.064 ;
    END
  END w_mask_in[190]
  PIN w_mask_in[191]
    DIRECTION INPUT ;
    USE SIGNAL ;
    SHAPE ABUTMENT ;
    PORT
      LAYER M4 ;
      RECT 114.456 71.232 114.480 71.256 ;
    END
  END w_mask_in[191]
  PIN w_mask_in[192]
    DIRECTION INPUT ;
    USE SIGNAL ;
    SHAPE ABUTMENT ;
    PORT
      LAYER M4 ;
      RECT 114.456 71.424 114.480 71.448 ;
    END
  END w_mask_in[192]
  PIN w_mask_in[193]
    DIRECTION INPUT ;
    USE SIGNAL ;
    SHAPE ABUTMENT ;
    PORT
      LAYER M4 ;
      RECT 114.456 71.616 114.480 71.640 ;
    END
  END w_mask_in[193]
  PIN w_mask_in[194]
    DIRECTION INPUT ;
    USE SIGNAL ;
    SHAPE ABUTMENT ;
    PORT
      LAYER M4 ;
      RECT 114.456 71.808 114.480 71.832 ;
    END
  END w_mask_in[194]
  PIN w_mask_in[195]
    DIRECTION INPUT ;
    USE SIGNAL ;
    SHAPE ABUTMENT ;
    PORT
      LAYER M4 ;
      RECT 114.456 72.000 114.480 72.024 ;
    END
  END w_mask_in[195]
  PIN w_mask_in[196]
    DIRECTION INPUT ;
    USE SIGNAL ;
    SHAPE ABUTMENT ;
    PORT
      LAYER M4 ;
      RECT 114.456 72.192 114.480 72.216 ;
    END
  END w_mask_in[196]
  PIN w_mask_in[197]
    DIRECTION INPUT ;
    USE SIGNAL ;
    SHAPE ABUTMENT ;
    PORT
      LAYER M4 ;
      RECT 114.456 72.384 114.480 72.408 ;
    END
  END w_mask_in[197]
  PIN w_mask_in[198]
    DIRECTION INPUT ;
    USE SIGNAL ;
    SHAPE ABUTMENT ;
    PORT
      LAYER M4 ;
      RECT 114.456 72.576 114.480 72.600 ;
    END
  END w_mask_in[198]
  PIN w_mask_in[199]
    DIRECTION INPUT ;
    USE SIGNAL ;
    SHAPE ABUTMENT ;
    PORT
      LAYER M4 ;
      RECT 114.456 72.768 114.480 72.792 ;
    END
  END w_mask_in[199]
  PIN w_mask_in[200]
    DIRECTION INPUT ;
    USE SIGNAL ;
    SHAPE ABUTMENT ;
    PORT
      LAYER M4 ;
      RECT 114.456 72.960 114.480 72.984 ;
    END
  END w_mask_in[200]
  PIN w_mask_in[201]
    DIRECTION INPUT ;
    USE SIGNAL ;
    SHAPE ABUTMENT ;
    PORT
      LAYER M4 ;
      RECT 114.456 73.152 114.480 73.176 ;
    END
  END w_mask_in[201]
  PIN w_mask_in[202]
    DIRECTION INPUT ;
    USE SIGNAL ;
    SHAPE ABUTMENT ;
    PORT
      LAYER M4 ;
      RECT 114.456 73.344 114.480 73.368 ;
    END
  END w_mask_in[202]
  PIN w_mask_in[203]
    DIRECTION INPUT ;
    USE SIGNAL ;
    SHAPE ABUTMENT ;
    PORT
      LAYER M4 ;
      RECT 114.456 73.536 114.480 73.560 ;
    END
  END w_mask_in[203]
  PIN w_mask_in[204]
    DIRECTION INPUT ;
    USE SIGNAL ;
    SHAPE ABUTMENT ;
    PORT
      LAYER M4 ;
      RECT 114.456 73.728 114.480 73.752 ;
    END
  END w_mask_in[204]
  PIN w_mask_in[205]
    DIRECTION INPUT ;
    USE SIGNAL ;
    SHAPE ABUTMENT ;
    PORT
      LAYER M4 ;
      RECT 114.456 73.920 114.480 73.944 ;
    END
  END w_mask_in[205]
  PIN w_mask_in[206]
    DIRECTION INPUT ;
    USE SIGNAL ;
    SHAPE ABUTMENT ;
    PORT
      LAYER M4 ;
      RECT 114.456 74.112 114.480 74.136 ;
    END
  END w_mask_in[206]
  PIN w_mask_in[207]
    DIRECTION INPUT ;
    USE SIGNAL ;
    SHAPE ABUTMENT ;
    PORT
      LAYER M4 ;
      RECT 114.456 74.304 114.480 74.328 ;
    END
  END w_mask_in[207]
  PIN w_mask_in[208]
    DIRECTION INPUT ;
    USE SIGNAL ;
    SHAPE ABUTMENT ;
    PORT
      LAYER M4 ;
      RECT 114.456 74.496 114.480 74.520 ;
    END
  END w_mask_in[208]
  PIN w_mask_in[209]
    DIRECTION INPUT ;
    USE SIGNAL ;
    SHAPE ABUTMENT ;
    PORT
      LAYER M4 ;
      RECT 114.456 74.688 114.480 74.712 ;
    END
  END w_mask_in[209]
  PIN w_mask_in[210]
    DIRECTION INPUT ;
    USE SIGNAL ;
    SHAPE ABUTMENT ;
    PORT
      LAYER M4 ;
      RECT 114.456 74.880 114.480 74.904 ;
    END
  END w_mask_in[210]
  PIN w_mask_in[211]
    DIRECTION INPUT ;
    USE SIGNAL ;
    SHAPE ABUTMENT ;
    PORT
      LAYER M4 ;
      RECT 114.456 75.072 114.480 75.096 ;
    END
  END w_mask_in[211]
  PIN w_mask_in[212]
    DIRECTION INPUT ;
    USE SIGNAL ;
    SHAPE ABUTMENT ;
    PORT
      LAYER M4 ;
      RECT 114.456 75.264 114.480 75.288 ;
    END
  END w_mask_in[212]
  PIN w_mask_in[213]
    DIRECTION INPUT ;
    USE SIGNAL ;
    SHAPE ABUTMENT ;
    PORT
      LAYER M4 ;
      RECT 114.456 75.456 114.480 75.480 ;
    END
  END w_mask_in[213]
  PIN w_mask_in[214]
    DIRECTION INPUT ;
    USE SIGNAL ;
    SHAPE ABUTMENT ;
    PORT
      LAYER M4 ;
      RECT 114.456 75.648 114.480 75.672 ;
    END
  END w_mask_in[214]
  PIN w_mask_in[215]
    DIRECTION INPUT ;
    USE SIGNAL ;
    SHAPE ABUTMENT ;
    PORT
      LAYER M4 ;
      RECT 114.456 75.840 114.480 75.864 ;
    END
  END w_mask_in[215]
  PIN w_mask_in[216]
    DIRECTION INPUT ;
    USE SIGNAL ;
    SHAPE ABUTMENT ;
    PORT
      LAYER M4 ;
      RECT 114.456 76.032 114.480 76.056 ;
    END
  END w_mask_in[216]
  PIN w_mask_in[217]
    DIRECTION INPUT ;
    USE SIGNAL ;
    SHAPE ABUTMENT ;
    PORT
      LAYER M4 ;
      RECT 114.456 76.224 114.480 76.248 ;
    END
  END w_mask_in[217]
  PIN w_mask_in[218]
    DIRECTION INPUT ;
    USE SIGNAL ;
    SHAPE ABUTMENT ;
    PORT
      LAYER M4 ;
      RECT 114.456 76.416 114.480 76.440 ;
    END
  END w_mask_in[218]
  PIN w_mask_in[219]
    DIRECTION INPUT ;
    USE SIGNAL ;
    SHAPE ABUTMENT ;
    PORT
      LAYER M4 ;
      RECT 114.456 76.608 114.480 76.632 ;
    END
  END w_mask_in[219]
  PIN w_mask_in[220]
    DIRECTION INPUT ;
    USE SIGNAL ;
    SHAPE ABUTMENT ;
    PORT
      LAYER M4 ;
      RECT 114.456 76.800 114.480 76.824 ;
    END
  END w_mask_in[220]
  PIN w_mask_in[221]
    DIRECTION INPUT ;
    USE SIGNAL ;
    SHAPE ABUTMENT ;
    PORT
      LAYER M4 ;
      RECT 114.456 76.992 114.480 77.016 ;
    END
  END w_mask_in[221]
  PIN w_mask_in[222]
    DIRECTION INPUT ;
    USE SIGNAL ;
    SHAPE ABUTMENT ;
    PORT
      LAYER M4 ;
      RECT 114.456 77.184 114.480 77.208 ;
    END
  END w_mask_in[222]
  PIN w_mask_in[223]
    DIRECTION INPUT ;
    USE SIGNAL ;
    SHAPE ABUTMENT ;
    PORT
      LAYER M4 ;
      RECT 114.456 77.376 114.480 77.400 ;
    END
  END w_mask_in[223]
  PIN w_mask_in[224]
    DIRECTION INPUT ;
    USE SIGNAL ;
    SHAPE ABUTMENT ;
    PORT
      LAYER M4 ;
      RECT 114.456 77.568 114.480 77.592 ;
    END
  END w_mask_in[224]
  PIN w_mask_in[225]
    DIRECTION INPUT ;
    USE SIGNAL ;
    SHAPE ABUTMENT ;
    PORT
      LAYER M4 ;
      RECT 114.456 77.760 114.480 77.784 ;
    END
  END w_mask_in[225]
  PIN w_mask_in[226]
    DIRECTION INPUT ;
    USE SIGNAL ;
    SHAPE ABUTMENT ;
    PORT
      LAYER M4 ;
      RECT 114.456 77.952 114.480 77.976 ;
    END
  END w_mask_in[226]
  PIN w_mask_in[227]
    DIRECTION INPUT ;
    USE SIGNAL ;
    SHAPE ABUTMENT ;
    PORT
      LAYER M4 ;
      RECT 114.456 78.144 114.480 78.168 ;
    END
  END w_mask_in[227]
  PIN w_mask_in[228]
    DIRECTION INPUT ;
    USE SIGNAL ;
    SHAPE ABUTMENT ;
    PORT
      LAYER M4 ;
      RECT 114.456 78.336 114.480 78.360 ;
    END
  END w_mask_in[228]
  PIN w_mask_in[229]
    DIRECTION INPUT ;
    USE SIGNAL ;
    SHAPE ABUTMENT ;
    PORT
      LAYER M4 ;
      RECT 114.456 78.528 114.480 78.552 ;
    END
  END w_mask_in[229]
  PIN w_mask_in[230]
    DIRECTION INPUT ;
    USE SIGNAL ;
    SHAPE ABUTMENT ;
    PORT
      LAYER M4 ;
      RECT 114.456 78.720 114.480 78.744 ;
    END
  END w_mask_in[230]
  PIN w_mask_in[231]
    DIRECTION INPUT ;
    USE SIGNAL ;
    SHAPE ABUTMENT ;
    PORT
      LAYER M4 ;
      RECT 114.456 78.912 114.480 78.936 ;
    END
  END w_mask_in[231]
  PIN w_mask_in[232]
    DIRECTION INPUT ;
    USE SIGNAL ;
    SHAPE ABUTMENT ;
    PORT
      LAYER M4 ;
      RECT 114.456 79.104 114.480 79.128 ;
    END
  END w_mask_in[232]
  PIN w_mask_in[233]
    DIRECTION INPUT ;
    USE SIGNAL ;
    SHAPE ABUTMENT ;
    PORT
      LAYER M4 ;
      RECT 114.456 79.296 114.480 79.320 ;
    END
  END w_mask_in[233]
  PIN w_mask_in[234]
    DIRECTION INPUT ;
    USE SIGNAL ;
    SHAPE ABUTMENT ;
    PORT
      LAYER M4 ;
      RECT 114.456 79.488 114.480 79.512 ;
    END
  END w_mask_in[234]
  PIN w_mask_in[235]
    DIRECTION INPUT ;
    USE SIGNAL ;
    SHAPE ABUTMENT ;
    PORT
      LAYER M4 ;
      RECT 114.456 79.680 114.480 79.704 ;
    END
  END w_mask_in[235]
  PIN w_mask_in[236]
    DIRECTION INPUT ;
    USE SIGNAL ;
    SHAPE ABUTMENT ;
    PORT
      LAYER M4 ;
      RECT 114.456 79.872 114.480 79.896 ;
    END
  END w_mask_in[236]
  PIN w_mask_in[237]
    DIRECTION INPUT ;
    USE SIGNAL ;
    SHAPE ABUTMENT ;
    PORT
      LAYER M4 ;
      RECT 114.456 80.064 114.480 80.088 ;
    END
  END w_mask_in[237]
  PIN w_mask_in[238]
    DIRECTION INPUT ;
    USE SIGNAL ;
    SHAPE ABUTMENT ;
    PORT
      LAYER M4 ;
      RECT 114.456 80.256 114.480 80.280 ;
    END
  END w_mask_in[238]
  PIN w_mask_in[239]
    DIRECTION INPUT ;
    USE SIGNAL ;
    SHAPE ABUTMENT ;
    PORT
      LAYER M4 ;
      RECT 114.456 80.448 114.480 80.472 ;
    END
  END w_mask_in[239]
  PIN w_mask_in[240]
    DIRECTION INPUT ;
    USE SIGNAL ;
    SHAPE ABUTMENT ;
    PORT
      LAYER M4 ;
      RECT 114.456 80.640 114.480 80.664 ;
    END
  END w_mask_in[240]
  PIN w_mask_in[241]
    DIRECTION INPUT ;
    USE SIGNAL ;
    SHAPE ABUTMENT ;
    PORT
      LAYER M4 ;
      RECT 114.456 80.832 114.480 80.856 ;
    END
  END w_mask_in[241]
  PIN w_mask_in[242]
    DIRECTION INPUT ;
    USE SIGNAL ;
    SHAPE ABUTMENT ;
    PORT
      LAYER M4 ;
      RECT 114.456 81.024 114.480 81.048 ;
    END
  END w_mask_in[242]
  PIN w_mask_in[243]
    DIRECTION INPUT ;
    USE SIGNAL ;
    SHAPE ABUTMENT ;
    PORT
      LAYER M4 ;
      RECT 114.456 81.216 114.480 81.240 ;
    END
  END w_mask_in[243]
  PIN w_mask_in[244]
    DIRECTION INPUT ;
    USE SIGNAL ;
    SHAPE ABUTMENT ;
    PORT
      LAYER M4 ;
      RECT 114.456 81.408 114.480 81.432 ;
    END
  END w_mask_in[244]
  PIN w_mask_in[245]
    DIRECTION INPUT ;
    USE SIGNAL ;
    SHAPE ABUTMENT ;
    PORT
      LAYER M4 ;
      RECT 114.456 81.600 114.480 81.624 ;
    END
  END w_mask_in[245]
  PIN w_mask_in[246]
    DIRECTION INPUT ;
    USE SIGNAL ;
    SHAPE ABUTMENT ;
    PORT
      LAYER M4 ;
      RECT 114.456 81.792 114.480 81.816 ;
    END
  END w_mask_in[246]
  PIN w_mask_in[247]
    DIRECTION INPUT ;
    USE SIGNAL ;
    SHAPE ABUTMENT ;
    PORT
      LAYER M4 ;
      RECT 114.456 81.984 114.480 82.008 ;
    END
  END w_mask_in[247]
  PIN w_mask_in[248]
    DIRECTION INPUT ;
    USE SIGNAL ;
    SHAPE ABUTMENT ;
    PORT
      LAYER M4 ;
      RECT 114.456 82.176 114.480 82.200 ;
    END
  END w_mask_in[248]
  PIN w_mask_in[249]
    DIRECTION INPUT ;
    USE SIGNAL ;
    SHAPE ABUTMENT ;
    PORT
      LAYER M4 ;
      RECT 114.456 82.368 114.480 82.392 ;
    END
  END w_mask_in[249]
  PIN w_mask_in[250]
    DIRECTION INPUT ;
    USE SIGNAL ;
    SHAPE ABUTMENT ;
    PORT
      LAYER M4 ;
      RECT 114.456 82.560 114.480 82.584 ;
    END
  END w_mask_in[250]
  PIN w_mask_in[251]
    DIRECTION INPUT ;
    USE SIGNAL ;
    SHAPE ABUTMENT ;
    PORT
      LAYER M4 ;
      RECT 114.456 82.752 114.480 82.776 ;
    END
  END w_mask_in[251]
  PIN w_mask_in[252]
    DIRECTION INPUT ;
    USE SIGNAL ;
    SHAPE ABUTMENT ;
    PORT
      LAYER M4 ;
      RECT 114.456 82.944 114.480 82.968 ;
    END
  END w_mask_in[252]
  PIN w_mask_in[253]
    DIRECTION INPUT ;
    USE SIGNAL ;
    SHAPE ABUTMENT ;
    PORT
      LAYER M4 ;
      RECT 114.456 83.136 114.480 83.160 ;
    END
  END w_mask_in[253]
  PIN w_mask_in[254]
    DIRECTION INPUT ;
    USE SIGNAL ;
    SHAPE ABUTMENT ;
    PORT
      LAYER M4 ;
      RECT 114.456 83.328 114.480 83.352 ;
    END
  END w_mask_in[254]
  PIN w_mask_in[255]
    DIRECTION INPUT ;
    USE SIGNAL ;
    SHAPE ABUTMENT ;
    PORT
      LAYER M4 ;
      RECT 114.456 83.520 114.480 83.544 ;
    END
  END w_mask_in[255]
  PIN w_mask_in[256]
    DIRECTION INPUT ;
    USE SIGNAL ;
    SHAPE ABUTMENT ;
    PORT
      LAYER M4 ;
      RECT 114.456 83.712 114.480 83.736 ;
    END
  END w_mask_in[256]
  PIN w_mask_in[257]
    DIRECTION INPUT ;
    USE SIGNAL ;
    SHAPE ABUTMENT ;
    PORT
      LAYER M4 ;
      RECT 114.456 83.904 114.480 83.928 ;
    END
  END w_mask_in[257]
  PIN w_mask_in[258]
    DIRECTION INPUT ;
    USE SIGNAL ;
    SHAPE ABUTMENT ;
    PORT
      LAYER M4 ;
      RECT 114.456 84.096 114.480 84.120 ;
    END
  END w_mask_in[258]
  PIN w_mask_in[259]
    DIRECTION INPUT ;
    USE SIGNAL ;
    SHAPE ABUTMENT ;
    PORT
      LAYER M4 ;
      RECT 114.456 84.288 114.480 84.312 ;
    END
  END w_mask_in[259]
  PIN w_mask_in[260]
    DIRECTION INPUT ;
    USE SIGNAL ;
    SHAPE ABUTMENT ;
    PORT
      LAYER M4 ;
      RECT 114.456 84.480 114.480 84.504 ;
    END
  END w_mask_in[260]
  PIN w_mask_in[261]
    DIRECTION INPUT ;
    USE SIGNAL ;
    SHAPE ABUTMENT ;
    PORT
      LAYER M4 ;
      RECT 114.456 84.672 114.480 84.696 ;
    END
  END w_mask_in[261]
  PIN w_mask_in[262]
    DIRECTION INPUT ;
    USE SIGNAL ;
    SHAPE ABUTMENT ;
    PORT
      LAYER M4 ;
      RECT 114.456 84.864 114.480 84.888 ;
    END
  END w_mask_in[262]
  PIN w_mask_in[263]
    DIRECTION INPUT ;
    USE SIGNAL ;
    SHAPE ABUTMENT ;
    PORT
      LAYER M4 ;
      RECT 114.456 85.056 114.480 85.080 ;
    END
  END w_mask_in[263]
  PIN w_mask_in[264]
    DIRECTION INPUT ;
    USE SIGNAL ;
    SHAPE ABUTMENT ;
    PORT
      LAYER M4 ;
      RECT 114.456 85.248 114.480 85.272 ;
    END
  END w_mask_in[264]
  PIN w_mask_in[265]
    DIRECTION INPUT ;
    USE SIGNAL ;
    SHAPE ABUTMENT ;
    PORT
      LAYER M4 ;
      RECT 114.456 85.440 114.480 85.464 ;
    END
  END w_mask_in[265]
  PIN w_mask_in[266]
    DIRECTION INPUT ;
    USE SIGNAL ;
    SHAPE ABUTMENT ;
    PORT
      LAYER M4 ;
      RECT 114.456 85.632 114.480 85.656 ;
    END
  END w_mask_in[266]
  PIN w_mask_in[267]
    DIRECTION INPUT ;
    USE SIGNAL ;
    SHAPE ABUTMENT ;
    PORT
      LAYER M4 ;
      RECT 114.456 85.824 114.480 85.848 ;
    END
  END w_mask_in[267]
  PIN w_mask_in[268]
    DIRECTION INPUT ;
    USE SIGNAL ;
    SHAPE ABUTMENT ;
    PORT
      LAYER M4 ;
      RECT 114.456 86.016 114.480 86.040 ;
    END
  END w_mask_in[268]
  PIN w_mask_in[269]
    DIRECTION INPUT ;
    USE SIGNAL ;
    SHAPE ABUTMENT ;
    PORT
      LAYER M4 ;
      RECT 114.456 86.208 114.480 86.232 ;
    END
  END w_mask_in[269]
  PIN w_mask_in[270]
    DIRECTION INPUT ;
    USE SIGNAL ;
    SHAPE ABUTMENT ;
    PORT
      LAYER M4 ;
      RECT 114.456 86.400 114.480 86.424 ;
    END
  END w_mask_in[270]
  PIN w_mask_in[271]
    DIRECTION INPUT ;
    USE SIGNAL ;
    SHAPE ABUTMENT ;
    PORT
      LAYER M4 ;
      RECT 114.456 86.592 114.480 86.616 ;
    END
  END w_mask_in[271]
  PIN w_mask_in[272]
    DIRECTION INPUT ;
    USE SIGNAL ;
    SHAPE ABUTMENT ;
    PORT
      LAYER M4 ;
      RECT 114.456 86.784 114.480 86.808 ;
    END
  END w_mask_in[272]
  PIN w_mask_in[273]
    DIRECTION INPUT ;
    USE SIGNAL ;
    SHAPE ABUTMENT ;
    PORT
      LAYER M4 ;
      RECT 114.456 86.976 114.480 87.000 ;
    END
  END w_mask_in[273]
  PIN w_mask_in[274]
    DIRECTION INPUT ;
    USE SIGNAL ;
    SHAPE ABUTMENT ;
    PORT
      LAYER M4 ;
      RECT 114.456 87.168 114.480 87.192 ;
    END
  END w_mask_in[274]
  PIN w_mask_in[275]
    DIRECTION INPUT ;
    USE SIGNAL ;
    SHAPE ABUTMENT ;
    PORT
      LAYER M4 ;
      RECT 114.456 87.360 114.480 87.384 ;
    END
  END w_mask_in[275]
  PIN w_mask_in[276]
    DIRECTION INPUT ;
    USE SIGNAL ;
    SHAPE ABUTMENT ;
    PORT
      LAYER M4 ;
      RECT 114.456 87.552 114.480 87.576 ;
    END
  END w_mask_in[276]
  PIN w_mask_in[277]
    DIRECTION INPUT ;
    USE SIGNAL ;
    SHAPE ABUTMENT ;
    PORT
      LAYER M4 ;
      RECT 114.456 87.744 114.480 87.768 ;
    END
  END w_mask_in[277]
  PIN w_mask_in[278]
    DIRECTION INPUT ;
    USE SIGNAL ;
    SHAPE ABUTMENT ;
    PORT
      LAYER M4 ;
      RECT 114.456 87.936 114.480 87.960 ;
    END
  END w_mask_in[278]
  PIN w_mask_in[279]
    DIRECTION INPUT ;
    USE SIGNAL ;
    SHAPE ABUTMENT ;
    PORT
      LAYER M4 ;
      RECT 114.456 88.128 114.480 88.152 ;
    END
  END w_mask_in[279]
  PIN w_mask_in[280]
    DIRECTION INPUT ;
    USE SIGNAL ;
    SHAPE ABUTMENT ;
    PORT
      LAYER M4 ;
      RECT 114.456 88.320 114.480 88.344 ;
    END
  END w_mask_in[280]
  PIN w_mask_in[281]
    DIRECTION INPUT ;
    USE SIGNAL ;
    SHAPE ABUTMENT ;
    PORT
      LAYER M4 ;
      RECT 114.456 88.512 114.480 88.536 ;
    END
  END w_mask_in[281]
  PIN w_mask_in[282]
    DIRECTION INPUT ;
    USE SIGNAL ;
    SHAPE ABUTMENT ;
    PORT
      LAYER M4 ;
      RECT 114.456 88.704 114.480 88.728 ;
    END
  END w_mask_in[282]
  PIN w_mask_in[283]
    DIRECTION INPUT ;
    USE SIGNAL ;
    SHAPE ABUTMENT ;
    PORT
      LAYER M4 ;
      RECT 114.456 88.896 114.480 88.920 ;
    END
  END w_mask_in[283]
  PIN w_mask_in[284]
    DIRECTION INPUT ;
    USE SIGNAL ;
    SHAPE ABUTMENT ;
    PORT
      LAYER M4 ;
      RECT 114.456 89.088 114.480 89.112 ;
    END
  END w_mask_in[284]
  PIN w_mask_in[285]
    DIRECTION INPUT ;
    USE SIGNAL ;
    SHAPE ABUTMENT ;
    PORT
      LAYER M4 ;
      RECT 114.456 89.280 114.480 89.304 ;
    END
  END w_mask_in[285]
  PIN w_mask_in[286]
    DIRECTION INPUT ;
    USE SIGNAL ;
    SHAPE ABUTMENT ;
    PORT
      LAYER M4 ;
      RECT 114.456 89.472 114.480 89.496 ;
    END
  END w_mask_in[286]
  PIN w_mask_in[287]
    DIRECTION INPUT ;
    USE SIGNAL ;
    SHAPE ABUTMENT ;
    PORT
      LAYER M4 ;
      RECT 114.456 89.664 114.480 89.688 ;
    END
  END w_mask_in[287]
  PIN w_mask_in[288]
    DIRECTION INPUT ;
    USE SIGNAL ;
    SHAPE ABUTMENT ;
    PORT
      LAYER M4 ;
      RECT 114.456 89.856 114.480 89.880 ;
    END
  END w_mask_in[288]
  PIN w_mask_in[289]
    DIRECTION INPUT ;
    USE SIGNAL ;
    SHAPE ABUTMENT ;
    PORT
      LAYER M4 ;
      RECT 114.456 90.048 114.480 90.072 ;
    END
  END w_mask_in[289]
  PIN w_mask_in[290]
    DIRECTION INPUT ;
    USE SIGNAL ;
    SHAPE ABUTMENT ;
    PORT
      LAYER M4 ;
      RECT 114.456 90.240 114.480 90.264 ;
    END
  END w_mask_in[290]
  PIN w_mask_in[291]
    DIRECTION INPUT ;
    USE SIGNAL ;
    SHAPE ABUTMENT ;
    PORT
      LAYER M4 ;
      RECT 114.456 90.432 114.480 90.456 ;
    END
  END w_mask_in[291]
  PIN w_mask_in[292]
    DIRECTION INPUT ;
    USE SIGNAL ;
    SHAPE ABUTMENT ;
    PORT
      LAYER M4 ;
      RECT 114.456 90.624 114.480 90.648 ;
    END
  END w_mask_in[292]
  PIN w_mask_in[293]
    DIRECTION INPUT ;
    USE SIGNAL ;
    SHAPE ABUTMENT ;
    PORT
      LAYER M4 ;
      RECT 114.456 90.816 114.480 90.840 ;
    END
  END w_mask_in[293]
  PIN w_mask_in[294]
    DIRECTION INPUT ;
    USE SIGNAL ;
    SHAPE ABUTMENT ;
    PORT
      LAYER M4 ;
      RECT 114.456 91.008 114.480 91.032 ;
    END
  END w_mask_in[294]
  PIN w_mask_in[295]
    DIRECTION INPUT ;
    USE SIGNAL ;
    SHAPE ABUTMENT ;
    PORT
      LAYER M4 ;
      RECT 114.456 91.200 114.480 91.224 ;
    END
  END w_mask_in[295]
  PIN w_mask_in[296]
    DIRECTION INPUT ;
    USE SIGNAL ;
    SHAPE ABUTMENT ;
    PORT
      LAYER M4 ;
      RECT 114.456 91.392 114.480 91.416 ;
    END
  END w_mask_in[296]
  PIN w_mask_in[297]
    DIRECTION INPUT ;
    USE SIGNAL ;
    SHAPE ABUTMENT ;
    PORT
      LAYER M4 ;
      RECT 114.456 91.584 114.480 91.608 ;
    END
  END w_mask_in[297]
  PIN w_mask_in[298]
    DIRECTION INPUT ;
    USE SIGNAL ;
    SHAPE ABUTMENT ;
    PORT
      LAYER M4 ;
      RECT 114.456 91.776 114.480 91.800 ;
    END
  END w_mask_in[298]
  PIN w_mask_in[299]
    DIRECTION INPUT ;
    USE SIGNAL ;
    SHAPE ABUTMENT ;
    PORT
      LAYER M4 ;
      RECT 114.456 91.968 114.480 91.992 ;
    END
  END w_mask_in[299]
  PIN w_mask_in[300]
    DIRECTION INPUT ;
    USE SIGNAL ;
    SHAPE ABUTMENT ;
    PORT
      LAYER M4 ;
      RECT 114.456 92.160 114.480 92.184 ;
    END
  END w_mask_in[300]
  PIN w_mask_in[301]
    DIRECTION INPUT ;
    USE SIGNAL ;
    SHAPE ABUTMENT ;
    PORT
      LAYER M4 ;
      RECT 114.456 92.352 114.480 92.376 ;
    END
  END w_mask_in[301]
  PIN w_mask_in[302]
    DIRECTION INPUT ;
    USE SIGNAL ;
    SHAPE ABUTMENT ;
    PORT
      LAYER M4 ;
      RECT 114.456 92.544 114.480 92.568 ;
    END
  END w_mask_in[302]
  PIN w_mask_in[303]
    DIRECTION INPUT ;
    USE SIGNAL ;
    SHAPE ABUTMENT ;
    PORT
      LAYER M4 ;
      RECT 114.456 92.736 114.480 92.760 ;
    END
  END w_mask_in[303]
  PIN w_mask_in[304]
    DIRECTION INPUT ;
    USE SIGNAL ;
    SHAPE ABUTMENT ;
    PORT
      LAYER M4 ;
      RECT 114.456 92.928 114.480 92.952 ;
    END
  END w_mask_in[304]
  PIN w_mask_in[305]
    DIRECTION INPUT ;
    USE SIGNAL ;
    SHAPE ABUTMENT ;
    PORT
      LAYER M4 ;
      RECT 114.456 93.120 114.480 93.144 ;
    END
  END w_mask_in[305]
  PIN w_mask_in[306]
    DIRECTION INPUT ;
    USE SIGNAL ;
    SHAPE ABUTMENT ;
    PORT
      LAYER M4 ;
      RECT 114.456 93.312 114.480 93.336 ;
    END
  END w_mask_in[306]
  PIN w_mask_in[307]
    DIRECTION INPUT ;
    USE SIGNAL ;
    SHAPE ABUTMENT ;
    PORT
      LAYER M4 ;
      RECT 114.456 93.504 114.480 93.528 ;
    END
  END w_mask_in[307]
  PIN w_mask_in[308]
    DIRECTION INPUT ;
    USE SIGNAL ;
    SHAPE ABUTMENT ;
    PORT
      LAYER M4 ;
      RECT 114.456 93.696 114.480 93.720 ;
    END
  END w_mask_in[308]
  PIN w_mask_in[309]
    DIRECTION INPUT ;
    USE SIGNAL ;
    SHAPE ABUTMENT ;
    PORT
      LAYER M4 ;
      RECT 114.456 93.888 114.480 93.912 ;
    END
  END w_mask_in[309]
  PIN w_mask_in[310]
    DIRECTION INPUT ;
    USE SIGNAL ;
    SHAPE ABUTMENT ;
    PORT
      LAYER M4 ;
      RECT 114.456 94.080 114.480 94.104 ;
    END
  END w_mask_in[310]
  PIN w_mask_in[311]
    DIRECTION INPUT ;
    USE SIGNAL ;
    SHAPE ABUTMENT ;
    PORT
      LAYER M4 ;
      RECT 114.456 94.272 114.480 94.296 ;
    END
  END w_mask_in[311]
  PIN w_mask_in[312]
    DIRECTION INPUT ;
    USE SIGNAL ;
    SHAPE ABUTMENT ;
    PORT
      LAYER M4 ;
      RECT 114.456 94.464 114.480 94.488 ;
    END
  END w_mask_in[312]
  PIN w_mask_in[313]
    DIRECTION INPUT ;
    USE SIGNAL ;
    SHAPE ABUTMENT ;
    PORT
      LAYER M4 ;
      RECT 114.456 94.656 114.480 94.680 ;
    END
  END w_mask_in[313]
  PIN w_mask_in[314]
    DIRECTION INPUT ;
    USE SIGNAL ;
    SHAPE ABUTMENT ;
    PORT
      LAYER M4 ;
      RECT 114.456 94.848 114.480 94.872 ;
    END
  END w_mask_in[314]
  PIN w_mask_in[315]
    DIRECTION INPUT ;
    USE SIGNAL ;
    SHAPE ABUTMENT ;
    PORT
      LAYER M4 ;
      RECT 114.456 95.040 114.480 95.064 ;
    END
  END w_mask_in[315]
  PIN w_mask_in[316]
    DIRECTION INPUT ;
    USE SIGNAL ;
    SHAPE ABUTMENT ;
    PORT
      LAYER M4 ;
      RECT 114.456 95.232 114.480 95.256 ;
    END
  END w_mask_in[316]
  PIN w_mask_in[317]
    DIRECTION INPUT ;
    USE SIGNAL ;
    SHAPE ABUTMENT ;
    PORT
      LAYER M4 ;
      RECT 114.456 95.424 114.480 95.448 ;
    END
  END w_mask_in[317]
  PIN w_mask_in[318]
    DIRECTION INPUT ;
    USE SIGNAL ;
    SHAPE ABUTMENT ;
    PORT
      LAYER M4 ;
      RECT 114.456 95.616 114.480 95.640 ;
    END
  END w_mask_in[318]
  PIN w_mask_in[319]
    DIRECTION INPUT ;
    USE SIGNAL ;
    SHAPE ABUTMENT ;
    PORT
      LAYER M4 ;
      RECT 114.456 95.808 114.480 95.832 ;
    END
  END w_mask_in[319]
  PIN w_mask_in[320]
    DIRECTION INPUT ;
    USE SIGNAL ;
    SHAPE ABUTMENT ;
    PORT
      LAYER M4 ;
      RECT 114.456 96.000 114.480 96.024 ;
    END
  END w_mask_in[320]
  PIN w_mask_in[321]
    DIRECTION INPUT ;
    USE SIGNAL ;
    SHAPE ABUTMENT ;
    PORT
      LAYER M4 ;
      RECT 114.456 96.192 114.480 96.216 ;
    END
  END w_mask_in[321]
  PIN w_mask_in[322]
    DIRECTION INPUT ;
    USE SIGNAL ;
    SHAPE ABUTMENT ;
    PORT
      LAYER M4 ;
      RECT 114.456 96.384 114.480 96.408 ;
    END
  END w_mask_in[322]
  PIN w_mask_in[323]
    DIRECTION INPUT ;
    USE SIGNAL ;
    SHAPE ABUTMENT ;
    PORT
      LAYER M4 ;
      RECT 114.456 96.576 114.480 96.600 ;
    END
  END w_mask_in[323]
  PIN w_mask_in[324]
    DIRECTION INPUT ;
    USE SIGNAL ;
    SHAPE ABUTMENT ;
    PORT
      LAYER M4 ;
      RECT 114.456 96.768 114.480 96.792 ;
    END
  END w_mask_in[324]
  PIN w_mask_in[325]
    DIRECTION INPUT ;
    USE SIGNAL ;
    SHAPE ABUTMENT ;
    PORT
      LAYER M4 ;
      RECT 114.456 96.960 114.480 96.984 ;
    END
  END w_mask_in[325]
  PIN w_mask_in[326]
    DIRECTION INPUT ;
    USE SIGNAL ;
    SHAPE ABUTMENT ;
    PORT
      LAYER M4 ;
      RECT 114.456 97.152 114.480 97.176 ;
    END
  END w_mask_in[326]
  PIN w_mask_in[327]
    DIRECTION INPUT ;
    USE SIGNAL ;
    SHAPE ABUTMENT ;
    PORT
      LAYER M4 ;
      RECT 114.456 97.344 114.480 97.368 ;
    END
  END w_mask_in[327]
  PIN w_mask_in[328]
    DIRECTION INPUT ;
    USE SIGNAL ;
    SHAPE ABUTMENT ;
    PORT
      LAYER M4 ;
      RECT 114.456 97.536 114.480 97.560 ;
    END
  END w_mask_in[328]
  PIN w_mask_in[329]
    DIRECTION INPUT ;
    USE SIGNAL ;
    SHAPE ABUTMENT ;
    PORT
      LAYER M4 ;
      RECT 114.456 97.728 114.480 97.752 ;
    END
  END w_mask_in[329]
  PIN w_mask_in[330]
    DIRECTION INPUT ;
    USE SIGNAL ;
    SHAPE ABUTMENT ;
    PORT
      LAYER M4 ;
      RECT 114.456 97.920 114.480 97.944 ;
    END
  END w_mask_in[330]
  PIN w_mask_in[331]
    DIRECTION INPUT ;
    USE SIGNAL ;
    SHAPE ABUTMENT ;
    PORT
      LAYER M4 ;
      RECT 114.456 98.112 114.480 98.136 ;
    END
  END w_mask_in[331]
  PIN w_mask_in[332]
    DIRECTION INPUT ;
    USE SIGNAL ;
    SHAPE ABUTMENT ;
    PORT
      LAYER M4 ;
      RECT 114.456 98.304 114.480 98.328 ;
    END
  END w_mask_in[332]
  PIN w_mask_in[333]
    DIRECTION INPUT ;
    USE SIGNAL ;
    SHAPE ABUTMENT ;
    PORT
      LAYER M4 ;
      RECT 114.456 98.496 114.480 98.520 ;
    END
  END w_mask_in[333]
  PIN w_mask_in[334]
    DIRECTION INPUT ;
    USE SIGNAL ;
    SHAPE ABUTMENT ;
    PORT
      LAYER M4 ;
      RECT 114.456 98.688 114.480 98.712 ;
    END
  END w_mask_in[334]
  PIN w_mask_in[335]
    DIRECTION INPUT ;
    USE SIGNAL ;
    SHAPE ABUTMENT ;
    PORT
      LAYER M4 ;
      RECT 114.456 98.880 114.480 98.904 ;
    END
  END w_mask_in[335]
  PIN w_mask_in[336]
    DIRECTION INPUT ;
    USE SIGNAL ;
    SHAPE ABUTMENT ;
    PORT
      LAYER M4 ;
      RECT 114.456 99.072 114.480 99.096 ;
    END
  END w_mask_in[336]
  PIN w_mask_in[337]
    DIRECTION INPUT ;
    USE SIGNAL ;
    SHAPE ABUTMENT ;
    PORT
      LAYER M4 ;
      RECT 114.456 99.264 114.480 99.288 ;
    END
  END w_mask_in[337]
  PIN w_mask_in[338]
    DIRECTION INPUT ;
    USE SIGNAL ;
    SHAPE ABUTMENT ;
    PORT
      LAYER M4 ;
      RECT 114.456 99.456 114.480 99.480 ;
    END
  END w_mask_in[338]
  PIN w_mask_in[339]
    DIRECTION INPUT ;
    USE SIGNAL ;
    SHAPE ABUTMENT ;
    PORT
      LAYER M4 ;
      RECT 114.456 99.648 114.480 99.672 ;
    END
  END w_mask_in[339]
  PIN VDD
    DIRECTION INOUT ;
    USE POWER ;
    PORT
      LAYER M4 ;
      RECT 0.300 0.384 114.180 0.480 ;
      RECT 0.300 1.152 114.180 1.248 ;
      RECT 0.300 1.920 114.180 2.016 ;
      RECT 0.300 2.688 114.180 2.784 ;
      RECT 0.300 3.456 114.180 3.552 ;
      RECT 0.300 4.224 114.180 4.320 ;
      RECT 0.300 4.992 114.180 5.088 ;
      RECT 0.300 5.760 114.180 5.856 ;
      RECT 0.300 6.528 114.180 6.624 ;
      RECT 0.300 7.296 114.180 7.392 ;
      RECT 0.300 8.064 114.180 8.160 ;
      RECT 0.300 8.832 114.180 8.928 ;
      RECT 0.300 9.600 114.180 9.696 ;
      RECT 0.300 10.368 114.180 10.464 ;
      RECT 0.300 11.136 114.180 11.232 ;
      RECT 0.300 11.904 114.180 12.000 ;
      RECT 0.300 12.672 114.180 12.768 ;
      RECT 0.300 13.440 114.180 13.536 ;
      RECT 0.300 14.208 114.180 14.304 ;
      RECT 0.300 14.976 114.180 15.072 ;
      RECT 0.300 15.744 114.180 15.840 ;
      RECT 0.300 16.512 114.180 16.608 ;
      RECT 0.300 17.280 114.180 17.376 ;
      RECT 0.300 18.048 114.180 18.144 ;
      RECT 0.300 18.816 114.180 18.912 ;
      RECT 0.300 19.584 114.180 19.680 ;
      RECT 0.300 20.352 114.180 20.448 ;
      RECT 0.300 21.120 114.180 21.216 ;
      RECT 0.300 21.888 114.180 21.984 ;
      RECT 0.300 22.656 114.180 22.752 ;
      RECT 0.300 23.424 114.180 23.520 ;
      RECT 0.300 24.192 114.180 24.288 ;
      RECT 0.300 24.960 114.180 25.056 ;
      RECT 0.300 25.728 114.180 25.824 ;
      RECT 0.300 26.496 114.180 26.592 ;
      RECT 0.300 27.264 114.180 27.360 ;
      RECT 0.300 28.032 114.180 28.128 ;
      RECT 0.300 28.800 114.180 28.896 ;
      RECT 0.300 29.568 114.180 29.664 ;
      RECT 0.300 30.336 114.180 30.432 ;
      RECT 0.300 31.104 114.180 31.200 ;
      RECT 0.300 31.872 114.180 31.968 ;
      RECT 0.300 32.640 114.180 32.736 ;
      RECT 0.300 33.408 114.180 33.504 ;
      RECT 0.300 34.176 114.180 34.272 ;
      RECT 0.300 34.944 114.180 35.040 ;
      RECT 0.300 35.712 114.180 35.808 ;
      RECT 0.300 36.480 114.180 36.576 ;
      RECT 0.300 37.248 114.180 37.344 ;
      RECT 0.300 38.016 114.180 38.112 ;
      RECT 0.300 38.784 114.180 38.880 ;
      RECT 0.300 39.552 114.180 39.648 ;
      RECT 0.300 40.320 114.180 40.416 ;
      RECT 0.300 41.088 114.180 41.184 ;
      RECT 0.300 41.856 114.180 41.952 ;
      RECT 0.300 42.624 114.180 42.720 ;
      RECT 0.300 43.392 114.180 43.488 ;
      RECT 0.300 44.160 114.180 44.256 ;
      RECT 0.300 44.928 114.180 45.024 ;
      RECT 0.300 45.696 114.180 45.792 ;
      RECT 0.300 46.464 114.180 46.560 ;
      RECT 0.300 47.232 114.180 47.328 ;
      RECT 0.300 48.000 114.180 48.096 ;
      RECT 0.300 48.768 114.180 48.864 ;
      RECT 0.300 49.536 114.180 49.632 ;
      RECT 0.300 50.304 114.180 50.400 ;
      RECT 0.300 51.072 114.180 51.168 ;
      RECT 0.300 51.840 114.180 51.936 ;
      RECT 0.300 52.608 114.180 52.704 ;
      RECT 0.300 53.376 114.180 53.472 ;
      RECT 0.300 54.144 114.180 54.240 ;
      RECT 0.300 54.912 114.180 55.008 ;
      RECT 0.300 55.680 114.180 55.776 ;
      RECT 0.300 56.448 114.180 56.544 ;
      RECT 0.300 57.216 114.180 57.312 ;
      RECT 0.300 57.984 114.180 58.080 ;
      RECT 0.300 58.752 114.180 58.848 ;
      RECT 0.300 59.520 114.180 59.616 ;
      RECT 0.300 60.288 114.180 60.384 ;
      RECT 0.300 61.056 114.180 61.152 ;
      RECT 0.300 61.824 114.180 61.920 ;
      RECT 0.300 62.592 114.180 62.688 ;
      RECT 0.300 63.360 114.180 63.456 ;
      RECT 0.300 64.128 114.180 64.224 ;
      RECT 0.300 64.896 114.180 64.992 ;
      RECT 0.300 65.664 114.180 65.760 ;
      RECT 0.300 66.432 114.180 66.528 ;
      RECT 0.300 67.200 114.180 67.296 ;
      RECT 0.300 67.968 114.180 68.064 ;
      RECT 0.300 68.736 114.180 68.832 ;
      RECT 0.300 69.504 114.180 69.600 ;
      RECT 0.300 70.272 114.180 70.368 ;
      RECT 0.300 71.040 114.180 71.136 ;
      RECT 0.300 71.808 114.180 71.904 ;
      RECT 0.300 72.576 114.180 72.672 ;
      RECT 0.300 73.344 114.180 73.440 ;
      RECT 0.300 74.112 114.180 74.208 ;
      RECT 0.300 74.880 114.180 74.976 ;
      RECT 0.300 75.648 114.180 75.744 ;
      RECT 0.300 76.416 114.180 76.512 ;
      RECT 0.300 77.184 114.180 77.280 ;
      RECT 0.300 77.952 114.180 78.048 ;
      RECT 0.300 78.720 114.180 78.816 ;
      RECT 0.300 79.488 114.180 79.584 ;
      RECT 0.300 80.256 114.180 80.352 ;
      RECT 0.300 81.024 114.180 81.120 ;
      RECT 0.300 81.792 114.180 81.888 ;
      RECT 0.300 82.560 114.180 82.656 ;
      RECT 0.300 83.328 114.180 83.424 ;
      RECT 0.300 84.096 114.180 84.192 ;
      RECT 0.300 84.864 114.180 84.960 ;
      RECT 0.300 85.632 114.180 85.728 ;
      RECT 0.300 86.400 114.180 86.496 ;
      RECT 0.300 87.168 114.180 87.264 ;
      RECT 0.300 87.936 114.180 88.032 ;
      RECT 0.300 88.704 114.180 88.800 ;
      RECT 0.300 89.472 114.180 89.568 ;
      RECT 0.300 90.240 114.180 90.336 ;
      RECT 0.300 91.008 114.180 91.104 ;
      RECT 0.300 91.776 114.180 91.872 ;
      RECT 0.300 92.544 114.180 92.640 ;
      RECT 0.300 93.312 114.180 93.408 ;
      RECT 0.300 94.080 114.180 94.176 ;
      RECT 0.300 94.848 114.180 94.944 ;
      RECT 0.300 95.616 114.180 95.712 ;
      RECT 0.300 96.384 114.180 96.480 ;
      RECT 0.300 97.152 114.180 97.248 ;
      RECT 0.300 97.920 114.180 98.016 ;
      RECT 0.300 98.688 114.180 98.784 ;
      RECT 0.300 99.456 114.180 99.552 ;
      RECT 0.300 100.224 114.180 100.320 ;
    END
  END VDD
  PIN VSS
    DIRECTION INOUT ;
    USE GROUND ;
    PORT
      LAYER M4 ;
      RECT 0.300 0.768 114.180 0.864 ;
      RECT 0.300 1.536 114.180 1.632 ;
      RECT 0.300 2.304 114.180 2.400 ;
      RECT 0.300 3.072 114.180 3.168 ;
      RECT 0.300 3.840 114.180 3.936 ;
      RECT 0.300 4.608 114.180 4.704 ;
      RECT 0.300 5.376 114.180 5.472 ;
      RECT 0.300 6.144 114.180 6.240 ;
      RECT 0.300 6.912 114.180 7.008 ;
      RECT 0.300 7.680 114.180 7.776 ;
      RECT 0.300 8.448 114.180 8.544 ;
      RECT 0.300 9.216 114.180 9.312 ;
      RECT 0.300 9.984 114.180 10.080 ;
      RECT 0.300 10.752 114.180 10.848 ;
      RECT 0.300 11.520 114.180 11.616 ;
      RECT 0.300 12.288 114.180 12.384 ;
      RECT 0.300 13.056 114.180 13.152 ;
      RECT 0.300 13.824 114.180 13.920 ;
      RECT 0.300 14.592 114.180 14.688 ;
      RECT 0.300 15.360 114.180 15.456 ;
      RECT 0.300 16.128 114.180 16.224 ;
      RECT 0.300 16.896 114.180 16.992 ;
      RECT 0.300 17.664 114.180 17.760 ;
      RECT 0.300 18.432 114.180 18.528 ;
      RECT 0.300 19.200 114.180 19.296 ;
      RECT 0.300 19.968 114.180 20.064 ;
      RECT 0.300 20.736 114.180 20.832 ;
      RECT 0.300 21.504 114.180 21.600 ;
      RECT 0.300 22.272 114.180 22.368 ;
      RECT 0.300 23.040 114.180 23.136 ;
      RECT 0.300 23.808 114.180 23.904 ;
      RECT 0.300 24.576 114.180 24.672 ;
      RECT 0.300 25.344 114.180 25.440 ;
      RECT 0.300 26.112 114.180 26.208 ;
      RECT 0.300 26.880 114.180 26.976 ;
      RECT 0.300 27.648 114.180 27.744 ;
      RECT 0.300 28.416 114.180 28.512 ;
      RECT 0.300 29.184 114.180 29.280 ;
      RECT 0.300 29.952 114.180 30.048 ;
      RECT 0.300 30.720 114.180 30.816 ;
      RECT 0.300 31.488 114.180 31.584 ;
      RECT 0.300 32.256 114.180 32.352 ;
      RECT 0.300 33.024 114.180 33.120 ;
      RECT 0.300 33.792 114.180 33.888 ;
      RECT 0.300 34.560 114.180 34.656 ;
      RECT 0.300 35.328 114.180 35.424 ;
      RECT 0.300 36.096 114.180 36.192 ;
      RECT 0.300 36.864 114.180 36.960 ;
      RECT 0.300 37.632 114.180 37.728 ;
      RECT 0.300 38.400 114.180 38.496 ;
      RECT 0.300 39.168 114.180 39.264 ;
      RECT 0.300 39.936 114.180 40.032 ;
      RECT 0.300 40.704 114.180 40.800 ;
      RECT 0.300 41.472 114.180 41.568 ;
      RECT 0.300 42.240 114.180 42.336 ;
      RECT 0.300 43.008 114.180 43.104 ;
      RECT 0.300 43.776 114.180 43.872 ;
      RECT 0.300 44.544 114.180 44.640 ;
      RECT 0.300 45.312 114.180 45.408 ;
      RECT 0.300 46.080 114.180 46.176 ;
      RECT 0.300 46.848 114.180 46.944 ;
      RECT 0.300 47.616 114.180 47.712 ;
      RECT 0.300 48.384 114.180 48.480 ;
      RECT 0.300 49.152 114.180 49.248 ;
      RECT 0.300 49.920 114.180 50.016 ;
      RECT 0.300 50.688 114.180 50.784 ;
      RECT 0.300 51.456 114.180 51.552 ;
      RECT 0.300 52.224 114.180 52.320 ;
      RECT 0.300 52.992 114.180 53.088 ;
      RECT 0.300 53.760 114.180 53.856 ;
      RECT 0.300 54.528 114.180 54.624 ;
      RECT 0.300 55.296 114.180 55.392 ;
      RECT 0.300 56.064 114.180 56.160 ;
      RECT 0.300 56.832 114.180 56.928 ;
      RECT 0.300 57.600 114.180 57.696 ;
      RECT 0.300 58.368 114.180 58.464 ;
      RECT 0.300 59.136 114.180 59.232 ;
      RECT 0.300 59.904 114.180 60.000 ;
      RECT 0.300 60.672 114.180 60.768 ;
      RECT 0.300 61.440 114.180 61.536 ;
      RECT 0.300 62.208 114.180 62.304 ;
      RECT 0.300 62.976 114.180 63.072 ;
      RECT 0.300 63.744 114.180 63.840 ;
      RECT 0.300 64.512 114.180 64.608 ;
      RECT 0.300 65.280 114.180 65.376 ;
      RECT 0.300 66.048 114.180 66.144 ;
      RECT 0.300 66.816 114.180 66.912 ;
      RECT 0.300 67.584 114.180 67.680 ;
      RECT 0.300 68.352 114.180 68.448 ;
      RECT 0.300 69.120 114.180 69.216 ;
      RECT 0.300 69.888 114.180 69.984 ;
      RECT 0.300 70.656 114.180 70.752 ;
      RECT 0.300 71.424 114.180 71.520 ;
      RECT 0.300 72.192 114.180 72.288 ;
      RECT 0.300 72.960 114.180 73.056 ;
      RECT 0.300 73.728 114.180 73.824 ;
      RECT 0.300 74.496 114.180 74.592 ;
      RECT 0.300 75.264 114.180 75.360 ;
      RECT 0.300 76.032 114.180 76.128 ;
      RECT 0.300 76.800 114.180 76.896 ;
      RECT 0.300 77.568 114.180 77.664 ;
      RECT 0.300 78.336 114.180 78.432 ;
      RECT 0.300 79.104 114.180 79.200 ;
      RECT 0.300 79.872 114.180 79.968 ;
      RECT 0.300 80.640 114.180 80.736 ;
      RECT 0.300 81.408 114.180 81.504 ;
      RECT 0.300 82.176 114.180 82.272 ;
      RECT 0.300 82.944 114.180 83.040 ;
      RECT 0.300 83.712 114.180 83.808 ;
      RECT 0.300 84.480 114.180 84.576 ;
      RECT 0.300 85.248 114.180 85.344 ;
      RECT 0.300 86.016 114.180 86.112 ;
      RECT 0.300 86.784 114.180 86.880 ;
      RECT 0.300 87.552 114.180 87.648 ;
      RECT 0.300 88.320 114.180 88.416 ;
      RECT 0.300 89.088 114.180 89.184 ;
      RECT 0.300 89.856 114.180 89.952 ;
      RECT 0.300 90.624 114.180 90.720 ;
      RECT 0.300 91.392 114.180 91.488 ;
      RECT 0.300 92.160 114.180 92.256 ;
      RECT 0.300 92.928 114.180 93.024 ;
      RECT 0.300 93.696 114.180 93.792 ;
      RECT 0.300 94.464 114.180 94.560 ;
      RECT 0.300 95.232 114.180 95.328 ;
      RECT 0.300 96.000 114.180 96.096 ;
      RECT 0.300 96.768 114.180 96.864 ;
      RECT 0.300 97.536 114.180 97.632 ;
      RECT 0.300 98.304 114.180 98.400 ;
      RECT 0.300 99.072 114.180 99.168 ;
      RECT 0.300 99.840 114.180 99.936 ;
      RECT 0.300 100.608 114.180 100.704 ;
    END
  END VSS
  OBS
    LAYER M1 ;
    RECT 0 0 114.480 100.710 ;
    LAYER M2 ;
    RECT 0 0 114.480 100.710 ;
    LAYER M3 ;
    RECT 0 0 114.480 100.710 ;
    LAYER M4 ;
    RECT 0.072 0 114.408 100.710 ;
  END
END ot_sram_1r1w2c_16x340_p192

END LIBRARY
